VERSION 5.8 ;
BUSBITCHARS "[]" ;
DIVIDERCHAR "/" ;
UNITS
    DATABASE MICRONS 1000 ;
END UNITS

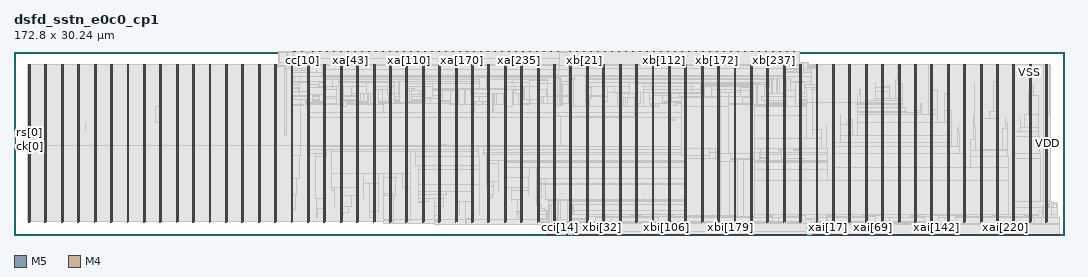
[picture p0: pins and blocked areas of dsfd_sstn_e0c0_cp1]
MACRO dsfd_sstn_e0c0_cp1
  FOREIGN dsfd_sstn_e0c0_cp1 0 0 ;
  CLASS BLOCK ;
  SIZE 172.8 BY 30.24 ;
  PIN c0[0]
    DIRECTION INPUT ;
    USE SIGNAL ;
    PORT
      LAYER M5 ;
        RECT  44.832 30.156 44.856 30.24 ;
    END
  END c0[0]
  PIN c0[1]
    DIRECTION INPUT ;
    USE SIGNAL ;
    PORT
      LAYER M5 ;
        RECT  44.976 30.156 45 30.24 ;
    END
  END c0[1]
  PIN cc[0]
    DIRECTION OUTPUT ;
    USE SIGNAL ;
    PORT
      LAYER M5 ;
        RECT  46.08 30.156 46.104 30.24 ;
    END
  END cc[0]
  PIN cc[10]
    DIRECTION OUTPUT ;
    USE SIGNAL ;
    PORT
      LAYER M5 ;
        RECT  47.52 30.156 47.544 30.24 ;
    END
  END cc[10]
  PIN cc[11]
    DIRECTION OUTPUT ;
    USE SIGNAL ;
    PORT
      LAYER M5 ;
        RECT  47.664 30.156 47.688 30.24 ;
    END
  END cc[11]
  PIN cc[12]
    DIRECTION OUTPUT ;
    USE SIGNAL ;
    PORT
      LAYER M5 ;
        RECT  47.808 30.156 47.832 30.24 ;
    END
  END cc[12]
  PIN cc[13]
    DIRECTION OUTPUT ;
    USE SIGNAL ;
    PORT
      LAYER M5 ;
        RECT  47.952 30.156 47.976 30.24 ;
    END
  END cc[13]
  PIN cc[14]
    DIRECTION OUTPUT ;
    USE SIGNAL ;
    PORT
      LAYER M5 ;
        RECT  48.096 30.156 48.12 30.24 ;
    END
  END cc[14]
  PIN cc[1]
    DIRECTION OUTPUT ;
    USE SIGNAL ;
    PORT
      LAYER M5 ;
        RECT  46.224 30.156 46.248 30.24 ;
    END
  END cc[1]
  PIN cc[2]
    DIRECTION OUTPUT ;
    USE SIGNAL ;
    PORT
      LAYER M5 ;
        RECT  46.368 30.156 46.392 30.24 ;
    END
  END cc[2]
  PIN cc[3]
    DIRECTION OUTPUT ;
    USE SIGNAL ;
    PORT
      LAYER M5 ;
        RECT  46.512 30.156 46.536 30.24 ;
    END
  END cc[3]
  PIN cc[4]
    DIRECTION OUTPUT ;
    USE SIGNAL ;
    PORT
      LAYER M5 ;
        RECT  46.656 30.156 46.68 30.24 ;
    END
  END cc[4]
  PIN cc[5]
    DIRECTION OUTPUT ;
    USE SIGNAL ;
    PORT
      LAYER M5 ;
        RECT  46.8 30.156 46.824 30.24 ;
    END
  END cc[5]
  PIN cc[6]
    DIRECTION OUTPUT ;
    USE SIGNAL ;
    PORT
      LAYER M5 ;
        RECT  46.944 30.156 46.968 30.24 ;
    END
  END cc[6]
  PIN cc[7]
    DIRECTION OUTPUT ;
    USE SIGNAL ;
    PORT
      LAYER M5 ;
        RECT  47.088 30.156 47.112 30.24 ;
    END
  END cc[7]
  PIN cc[8]
    DIRECTION OUTPUT ;
    USE SIGNAL ;
    PORT
      LAYER M5 ;
        RECT  47.232 30.156 47.256 30.24 ;
    END
  END cc[8]
  PIN cc[9]
    DIRECTION OUTPUT ;
    USE SIGNAL ;
    PORT
      LAYER M5 ;
        RECT  47.376 30.156 47.4 30.24 ;
    END
  END cc[9]
  PIN cci[0]
    DIRECTION INPUT ;
    USE SIGNAL ;
    PORT
      LAYER M5 ;
        RECT  87.792 0 87.816 0.084 ;
    END
  END cci[0]
  PIN cci[10]
    DIRECTION INPUT ;
    USE SIGNAL ;
    PORT
      LAYER M5 ;
        RECT  89.232 0 89.256 0.084 ;
    END
  END cci[10]
  PIN cci[11]
    DIRECTION INPUT ;
    USE SIGNAL ;
    PORT
      LAYER M5 ;
        RECT  89.376 0 89.4 0.084 ;
    END
  END cci[11]
  PIN cci[12]
    DIRECTION INPUT ;
    USE SIGNAL ;
    PORT
      LAYER M5 ;
        RECT  89.52 0 89.544 0.084 ;
    END
  END cci[12]
  PIN cci[13]
    DIRECTION INPUT ;
    USE SIGNAL ;
    PORT
      LAYER M5 ;
        RECT  89.664 0 89.688 0.084 ;
    END
  END cci[13]
  PIN cci[14]
    DIRECTION INPUT ;
    USE SIGNAL ;
    PORT
      LAYER M5 ;
        RECT  89.808 0 89.832 0.084 ;
    END
  END cci[14]
  PIN cci[1]
    DIRECTION INPUT ;
    USE SIGNAL ;
    PORT
      LAYER M5 ;
        RECT  87.936 0 87.96 0.084 ;
    END
  END cci[1]
  PIN cci[2]
    DIRECTION INPUT ;
    USE SIGNAL ;
    PORT
      LAYER M5 ;
        RECT  88.08 0 88.104 0.084 ;
    END
  END cci[2]
  PIN cci[3]
    DIRECTION INPUT ;
    USE SIGNAL ;
    PORT
      LAYER M5 ;
        RECT  88.224 0 88.248 0.084 ;
    END
  END cci[3]
  PIN cci[4]
    DIRECTION INPUT ;
    USE SIGNAL ;
    PORT
      LAYER M5 ;
        RECT  88.368 0 88.392 0.084 ;
    END
  END cci[4]
  PIN cci[5]
    DIRECTION INPUT ;
    USE SIGNAL ;
    PORT
      LAYER M5 ;
        RECT  88.512 0 88.536 0.084 ;
    END
  END cci[5]
  PIN cci[6]
    DIRECTION INPUT ;
    USE SIGNAL ;
    PORT
      LAYER M5 ;
        RECT  88.656 0 88.68 0.084 ;
    END
  END cci[6]
  PIN cci[7]
    DIRECTION INPUT ;
    USE SIGNAL ;
    PORT
      LAYER M5 ;
        RECT  88.8 0 88.824 0.084 ;
    END
  END cci[7]
  PIN cci[8]
    DIRECTION INPUT ;
    USE SIGNAL ;
    PORT
      LAYER M5 ;
        RECT  88.944 0 88.968 0.084 ;
    END
  END cci[8]
  PIN cci[9]
    DIRECTION INPUT ;
    USE SIGNAL ;
    PORT
      LAYER M5 ;
        RECT  89.088 0 89.112 0.084 ;
    END
  END cci[9]
  PIN ck[0]
    DIRECTION INPUT ;
    USE SIGNAL ;
    PORT
      LAYER M4 ;
        RECT  0 14.592 0.084 14.616 ;
    END
    PORT
      LAYER M4 ;
        RECT  0.06 14.592 0.097 14.616 ;
    END
  END ck[0]
  PIN e0[0]
    DIRECTION INPUT ;
    USE SIGNAL ;
    PORT
      LAYER M5 ;
        RECT  43.584 30.156 43.608 30.24 ;
    END
  END e0[0]
  PIN e0[1]
    DIRECTION INPUT ;
    USE SIGNAL ;
    PORT
      LAYER M5 ;
        RECT  43.728 30.156 43.752 30.24 ;
    END
  END e0[1]
  PIN rs[0]
    DIRECTION INPUT ;
    USE SIGNAL ;
    PORT
      LAYER M4 ;
        RECT  0 15.6 0.084 15.624 ;
    END
    PORT
      LAYER M4 ;
        RECT  0.06 15.6 0.097 15.624 ;
    END
  END rs[0]
  PIN so[0]
    DIRECTION OUTPUT ;
    USE SIGNAL ;
    PORT
      LAYER M5 ;
        RECT  90.912 0 90.936 0.084 ;
    END
  END so[0]
  PIN so[1]
    DIRECTION OUTPUT ;
    USE SIGNAL ;
    PORT
      LAYER M5 ;
        RECT  91.056 0 91.08 0.084 ;
    END
  END so[1]
  PIN xa[0]
    DIRECTION OUTPUT ;
    USE SIGNAL ;
    PORT
      LAYER M5 ;
        RECT  49.2 30.156 49.224 30.24 ;
    END
  END xa[0]
  PIN xa[100]
    DIRECTION OUTPUT ;
    USE SIGNAL ;
    PORT
      LAYER M5 ;
        RECT  63.6 30.156 63.624 30.24 ;
    END
  END xa[100]
  PIN xa[101]
    DIRECTION OUTPUT ;
    USE SIGNAL ;
    PORT
      LAYER M5 ;
        RECT  63.744 30.156 63.768 30.24 ;
    END
  END xa[101]
  PIN xa[102]
    DIRECTION OUTPUT ;
    USE SIGNAL ;
    PORT
      LAYER M5 ;
        RECT  63.888 30.156 63.912 30.24 ;
    END
  END xa[102]
  PIN xa[103]
    DIRECTION OUTPUT ;
    USE SIGNAL ;
    PORT
      LAYER M5 ;
        RECT  64.032 30.156 64.056 30.24 ;
    END
  END xa[103]
  PIN xa[104]
    DIRECTION OUTPUT ;
    USE SIGNAL ;
    PORT
      LAYER M5 ;
        RECT  64.176 30.156 64.2 30.24 ;
    END
  END xa[104]
  PIN xa[105]
    DIRECTION OUTPUT ;
    USE SIGNAL ;
    PORT
      LAYER M5 ;
        RECT  64.32 30.156 64.344 30.24 ;
    END
  END xa[105]
  PIN xa[106]
    DIRECTION OUTPUT ;
    USE SIGNAL ;
    PORT
      LAYER M5 ;
        RECT  64.464 30.156 64.488 30.24 ;
    END
  END xa[106]
  PIN xa[107]
    DIRECTION OUTPUT ;
    USE SIGNAL ;
    PORT
      LAYER M5 ;
        RECT  64.608 30.156 64.632 30.24 ;
    END
  END xa[107]
  PIN xa[108]
    DIRECTION OUTPUT ;
    USE SIGNAL ;
    PORT
      LAYER M5 ;
        RECT  64.752 30.156 64.776 30.24 ;
    END
  END xa[108]
  PIN xa[109]
    DIRECTION OUTPUT ;
    USE SIGNAL ;
    PORT
      LAYER M5 ;
        RECT  64.896 30.156 64.92 30.24 ;
    END
  END xa[109]
  PIN xa[10]
    DIRECTION OUTPUT ;
    USE SIGNAL ;
    PORT
      LAYER M5 ;
        RECT  50.64 30.156 50.664 30.24 ;
    END
  END xa[10]
  PIN xa[110]
    DIRECTION OUTPUT ;
    USE SIGNAL ;
    PORT
      LAYER M5 ;
        RECT  65.04 30.156 65.064 30.24 ;
    END
  END xa[110]
  PIN xa[111]
    DIRECTION OUTPUT ;
    USE SIGNAL ;
    PORT
      LAYER M5 ;
        RECT  65.184 30.156 65.208 30.24 ;
    END
  END xa[111]
  PIN xa[112]
    DIRECTION OUTPUT ;
    USE SIGNAL ;
    PORT
      LAYER M5 ;
        RECT  65.328 30.156 65.352 30.24 ;
    END
  END xa[112]
  PIN xa[113]
    DIRECTION OUTPUT ;
    USE SIGNAL ;
    PORT
      LAYER M5 ;
        RECT  65.472 30.156 65.496 30.24 ;
    END
  END xa[113]
  PIN xa[114]
    DIRECTION OUTPUT ;
    USE SIGNAL ;
    PORT
      LAYER M5 ;
        RECT  65.616 30.156 65.64 30.24 ;
    END
  END xa[114]
  PIN xa[115]
    DIRECTION OUTPUT ;
    USE SIGNAL ;
    PORT
      LAYER M5 ;
        RECT  65.76 30.156 65.784 30.24 ;
    END
  END xa[115]
  PIN xa[116]
    DIRECTION OUTPUT ;
    USE SIGNAL ;
    PORT
      LAYER M5 ;
        RECT  65.904 30.156 65.928 30.24 ;
    END
  END xa[116]
  PIN xa[117]
    DIRECTION OUTPUT ;
    USE SIGNAL ;
    PORT
      LAYER M5 ;
        RECT  66.048 30.156 66.072 30.24 ;
    END
  END xa[117]
  PIN xa[118]
    DIRECTION OUTPUT ;
    USE SIGNAL ;
    PORT
      LAYER M5 ;
        RECT  66.192 30.156 66.216 30.24 ;
    END
  END xa[118]
  PIN xa[119]
    DIRECTION OUTPUT ;
    USE SIGNAL ;
    PORT
      LAYER M5 ;
        RECT  66.336 30.156 66.36 30.24 ;
    END
  END xa[119]
  PIN xa[11]
    DIRECTION OUTPUT ;
    USE SIGNAL ;
    PORT
      LAYER M5 ;
        RECT  50.784 30.156 50.808 30.24 ;
    END
  END xa[11]
  PIN xa[120]
    DIRECTION OUTPUT ;
    USE SIGNAL ;
    PORT
      LAYER M5 ;
        RECT  66.48 30.156 66.504 30.24 ;
    END
  END xa[120]
  PIN xa[121]
    DIRECTION OUTPUT ;
    USE SIGNAL ;
    PORT
      LAYER M5 ;
        RECT  66.624 30.156 66.648 30.24 ;
    END
  END xa[121]
  PIN xa[122]
    DIRECTION OUTPUT ;
    USE SIGNAL ;
    PORT
      LAYER M5 ;
        RECT  66.768 30.156 66.792 30.24 ;
    END
  END xa[122]
  PIN xa[123]
    DIRECTION OUTPUT ;
    USE SIGNAL ;
    PORT
      LAYER M5 ;
        RECT  66.912 30.156 66.936 30.24 ;
    END
  END xa[123]
  PIN xa[124]
    DIRECTION OUTPUT ;
    USE SIGNAL ;
    PORT
      LAYER M5 ;
        RECT  67.056 30.156 67.08 30.24 ;
    END
  END xa[124]
  PIN xa[125]
    DIRECTION OUTPUT ;
    USE SIGNAL ;
    PORT
      LAYER M5 ;
        RECT  67.2 30.156 67.224 30.24 ;
    END
  END xa[125]
  PIN xa[126]
    DIRECTION OUTPUT ;
    USE SIGNAL ;
    PORT
      LAYER M5 ;
        RECT  67.344 30.156 67.368 30.24 ;
    END
  END xa[126]
  PIN xa[127]
    DIRECTION OUTPUT ;
    USE SIGNAL ;
    PORT
      LAYER M5 ;
        RECT  67.488 30.156 67.512 30.24 ;
    END
  END xa[127]
  PIN xa[128]
    DIRECTION OUTPUT ;
    USE SIGNAL ;
    PORT
      LAYER M5 ;
        RECT  67.632 30.156 67.656 30.24 ;
    END
  END xa[128]
  PIN xa[129]
    DIRECTION OUTPUT ;
    USE SIGNAL ;
    PORT
      LAYER M5 ;
        RECT  67.776 30.156 67.8 30.24 ;
    END
  END xa[129]
  PIN xa[12]
    DIRECTION OUTPUT ;
    USE SIGNAL ;
    PORT
      LAYER M5 ;
        RECT  50.928 30.156 50.952 30.24 ;
    END
  END xa[12]
  PIN xa[130]
    DIRECTION OUTPUT ;
    USE SIGNAL ;
    PORT
      LAYER M5 ;
        RECT  67.92 30.156 67.944 30.24 ;
    END
  END xa[130]
  PIN xa[131]
    DIRECTION OUTPUT ;
    USE SIGNAL ;
    PORT
      LAYER M5 ;
        RECT  68.064 30.156 68.088 30.24 ;
    END
  END xa[131]
  PIN xa[132]
    DIRECTION OUTPUT ;
    USE SIGNAL ;
    PORT
      LAYER M5 ;
        RECT  68.208 30.156 68.232 30.24 ;
    END
  END xa[132]
  PIN xa[133]
    DIRECTION OUTPUT ;
    USE SIGNAL ;
    PORT
      LAYER M5 ;
        RECT  68.352 30.156 68.376 30.24 ;
    END
  END xa[133]
  PIN xa[134]
    DIRECTION OUTPUT ;
    USE SIGNAL ;
    PORT
      LAYER M5 ;
        RECT  68.496 30.156 68.52 30.24 ;
    END
  END xa[134]
  PIN xa[135]
    DIRECTION OUTPUT ;
    USE SIGNAL ;
    PORT
      LAYER M5 ;
        RECT  68.64 30.156 68.664 30.24 ;
    END
  END xa[135]
  PIN xa[136]
    DIRECTION OUTPUT ;
    USE SIGNAL ;
    PORT
      LAYER M5 ;
        RECT  68.784 30.156 68.808 30.24 ;
    END
  END xa[136]
  PIN xa[137]
    DIRECTION OUTPUT ;
    USE SIGNAL ;
    PORT
      LAYER M5 ;
        RECT  68.928 30.156 68.952 30.24 ;
    END
  END xa[137]
  PIN xa[138]
    DIRECTION OUTPUT ;
    USE SIGNAL ;
    PORT
      LAYER M5 ;
        RECT  69.072 30.156 69.096 30.24 ;
    END
  END xa[138]
  PIN xa[139]
    DIRECTION OUTPUT ;
    USE SIGNAL ;
    PORT
      LAYER M5 ;
        RECT  69.216 30.156 69.24 30.24 ;
    END
  END xa[139]
  PIN xa[13]
    DIRECTION OUTPUT ;
    USE SIGNAL ;
    PORT
      LAYER M5 ;
        RECT  51.072 30.156 51.096 30.24 ;
    END
  END xa[13]
  PIN xa[140]
    DIRECTION OUTPUT ;
    USE SIGNAL ;
    PORT
      LAYER M5 ;
        RECT  69.36 30.156 69.384 30.24 ;
    END
  END xa[140]
  PIN xa[141]
    DIRECTION OUTPUT ;
    USE SIGNAL ;
    PORT
      LAYER M5 ;
        RECT  69.504 30.156 69.528 30.24 ;
    END
  END xa[141]
  PIN xa[142]
    DIRECTION OUTPUT ;
    USE SIGNAL ;
    PORT
      LAYER M5 ;
        RECT  69.648 30.156 69.672 30.24 ;
    END
  END xa[142]
  PIN xa[143]
    DIRECTION OUTPUT ;
    USE SIGNAL ;
    PORT
      LAYER M5 ;
        RECT  69.792 30.156 69.816 30.24 ;
    END
  END xa[143]
  PIN xa[144]
    DIRECTION OUTPUT ;
    USE SIGNAL ;
    PORT
      LAYER M5 ;
        RECT  69.936 30.156 69.96 30.24 ;
    END
  END xa[144]
  PIN xa[145]
    DIRECTION OUTPUT ;
    USE SIGNAL ;
    PORT
      LAYER M5 ;
        RECT  70.08 30.156 70.104 30.24 ;
    END
  END xa[145]
  PIN xa[146]
    DIRECTION OUTPUT ;
    USE SIGNAL ;
    PORT
      LAYER M5 ;
        RECT  70.224 30.156 70.248 30.24 ;
    END
  END xa[146]
  PIN xa[147]
    DIRECTION OUTPUT ;
    USE SIGNAL ;
    PORT
      LAYER M5 ;
        RECT  70.368 30.156 70.392 30.24 ;
    END
  END xa[147]
  PIN xa[148]
    DIRECTION OUTPUT ;
    USE SIGNAL ;
    PORT
      LAYER M5 ;
        RECT  70.512 30.156 70.536 30.24 ;
    END
  END xa[148]
  PIN xa[149]
    DIRECTION OUTPUT ;
    USE SIGNAL ;
    PORT
      LAYER M5 ;
        RECT  70.656 30.156 70.68 30.24 ;
    END
  END xa[149]
  PIN xa[14]
    DIRECTION OUTPUT ;
    USE SIGNAL ;
    PORT
      LAYER M5 ;
        RECT  51.216 30.156 51.24 30.24 ;
    END
  END xa[14]
  PIN xa[150]
    DIRECTION OUTPUT ;
    USE SIGNAL ;
    PORT
      LAYER M5 ;
        RECT  70.8 30.156 70.824 30.24 ;
    END
  END xa[150]
  PIN xa[151]
    DIRECTION OUTPUT ;
    USE SIGNAL ;
    PORT
      LAYER M5 ;
        RECT  70.944 30.156 70.968 30.24 ;
    END
  END xa[151]
  PIN xa[152]
    DIRECTION OUTPUT ;
    USE SIGNAL ;
    PORT
      LAYER M5 ;
        RECT  71.088 30.156 71.112 30.24 ;
    END
  END xa[152]
  PIN xa[153]
    DIRECTION OUTPUT ;
    USE SIGNAL ;
    PORT
      LAYER M5 ;
        RECT  71.232 30.156 71.256 30.24 ;
    END
  END xa[153]
  PIN xa[154]
    DIRECTION OUTPUT ;
    USE SIGNAL ;
    PORT
      LAYER M5 ;
        RECT  71.376 30.156 71.4 30.24 ;
    END
  END xa[154]
  PIN xa[155]
    DIRECTION OUTPUT ;
    USE SIGNAL ;
    PORT
      LAYER M5 ;
        RECT  71.52 30.156 71.544 30.24 ;
    END
  END xa[155]
  PIN xa[156]
    DIRECTION OUTPUT ;
    USE SIGNAL ;
    PORT
      LAYER M5 ;
        RECT  71.664 30.156 71.688 30.24 ;
    END
  END xa[156]
  PIN xa[157]
    DIRECTION OUTPUT ;
    USE SIGNAL ;
    PORT
      LAYER M5 ;
        RECT  71.808 30.156 71.832 30.24 ;
    END
  END xa[157]
  PIN xa[158]
    DIRECTION OUTPUT ;
    USE SIGNAL ;
    PORT
      LAYER M5 ;
        RECT  71.952 30.156 71.976 30.24 ;
    END
  END xa[158]
  PIN xa[159]
    DIRECTION OUTPUT ;
    USE SIGNAL ;
    PORT
      LAYER M5 ;
        RECT  72.096 30.156 72.12 30.24 ;
    END
  END xa[159]
  PIN xa[15]
    DIRECTION OUTPUT ;
    USE SIGNAL ;
    PORT
      LAYER M5 ;
        RECT  51.36 30.156 51.384 30.24 ;
    END
  END xa[15]
  PIN xa[160]
    DIRECTION OUTPUT ;
    USE SIGNAL ;
    PORT
      LAYER M5 ;
        RECT  72.24 30.156 72.264 30.24 ;
    END
  END xa[160]
  PIN xa[161]
    DIRECTION OUTPUT ;
    USE SIGNAL ;
    PORT
      LAYER M5 ;
        RECT  72.384 30.156 72.408 30.24 ;
    END
  END xa[161]
  PIN xa[162]
    DIRECTION OUTPUT ;
    USE SIGNAL ;
    PORT
      LAYER M5 ;
        RECT  72.528 30.156 72.552 30.24 ;
    END
  END xa[162]
  PIN xa[163]
    DIRECTION OUTPUT ;
    USE SIGNAL ;
    PORT
      LAYER M5 ;
        RECT  72.672 30.156 72.696 30.24 ;
    END
  END xa[163]
  PIN xa[164]
    DIRECTION OUTPUT ;
    USE SIGNAL ;
    PORT
      LAYER M5 ;
        RECT  72.816 30.156 72.84 30.24 ;
    END
  END xa[164]
  PIN xa[165]
    DIRECTION OUTPUT ;
    USE SIGNAL ;
    PORT
      LAYER M5 ;
        RECT  72.96 30.156 72.984 30.24 ;
    END
  END xa[165]
  PIN xa[166]
    DIRECTION OUTPUT ;
    USE SIGNAL ;
    PORT
      LAYER M5 ;
        RECT  73.104 30.156 73.128 30.24 ;
    END
  END xa[166]
  PIN xa[167]
    DIRECTION OUTPUT ;
    USE SIGNAL ;
    PORT
      LAYER M5 ;
        RECT  73.248 30.156 73.272 30.24 ;
    END
  END xa[167]
  PIN xa[168]
    DIRECTION OUTPUT ;
    USE SIGNAL ;
    PORT
      LAYER M5 ;
        RECT  73.392 30.156 73.416 30.24 ;
    END
  END xa[168]
  PIN xa[169]
    DIRECTION OUTPUT ;
    USE SIGNAL ;
    PORT
      LAYER M5 ;
        RECT  73.536 30.156 73.56 30.24 ;
    END
  END xa[169]
  PIN xa[16]
    DIRECTION OUTPUT ;
    USE SIGNAL ;
    PORT
      LAYER M5 ;
        RECT  51.504 30.156 51.528 30.24 ;
    END
  END xa[16]
  PIN xa[170]
    DIRECTION OUTPUT ;
    USE SIGNAL ;
    PORT
      LAYER M5 ;
        RECT  73.68 30.156 73.704 30.24 ;
    END
  END xa[170]
  PIN xa[171]
    DIRECTION OUTPUT ;
    USE SIGNAL ;
    PORT
      LAYER M5 ;
        RECT  73.824 30.156 73.848 30.24 ;
    END
  END xa[171]
  PIN xa[172]
    DIRECTION OUTPUT ;
    USE SIGNAL ;
    PORT
      LAYER M5 ;
        RECT  73.968 30.156 73.992 30.24 ;
    END
  END xa[172]
  PIN xa[173]
    DIRECTION OUTPUT ;
    USE SIGNAL ;
    PORT
      LAYER M5 ;
        RECT  74.112 30.156 74.136 30.24 ;
    END
  END xa[173]
  PIN xa[174]
    DIRECTION OUTPUT ;
    USE SIGNAL ;
    PORT
      LAYER M5 ;
        RECT  74.256 30.156 74.28 30.24 ;
    END
  END xa[174]
  PIN xa[175]
    DIRECTION OUTPUT ;
    USE SIGNAL ;
    PORT
      LAYER M5 ;
        RECT  74.4 30.156 74.424 30.24 ;
    END
  END xa[175]
  PIN xa[176]
    DIRECTION OUTPUT ;
    USE SIGNAL ;
    PORT
      LAYER M5 ;
        RECT  74.544 30.156 74.568 30.24 ;
    END
  END xa[176]
  PIN xa[177]
    DIRECTION OUTPUT ;
    USE SIGNAL ;
    PORT
      LAYER M5 ;
        RECT  74.688 30.156 74.712 30.24 ;
    END
  END xa[177]
  PIN xa[178]
    DIRECTION OUTPUT ;
    USE SIGNAL ;
    PORT
      LAYER M5 ;
        RECT  74.832 30.156 74.856 30.24 ;
    END
  END xa[178]
  PIN xa[179]
    DIRECTION OUTPUT ;
    USE SIGNAL ;
    PORT
      LAYER M5 ;
        RECT  74.976 30.156 75 30.24 ;
    END
  END xa[179]
  PIN xa[17]
    DIRECTION OUTPUT ;
    USE SIGNAL ;
    PORT
      LAYER M5 ;
        RECT  51.648 30.156 51.672 30.24 ;
    END
  END xa[17]
  PIN xa[180]
    DIRECTION OUTPUT ;
    USE SIGNAL ;
    PORT
      LAYER M5 ;
        RECT  75.12 30.156 75.144 30.24 ;
    END
  END xa[180]
  PIN xa[181]
    DIRECTION OUTPUT ;
    USE SIGNAL ;
    PORT
      LAYER M5 ;
        RECT  75.264 30.156 75.288 30.24 ;
    END
  END xa[181]
  PIN xa[182]
    DIRECTION OUTPUT ;
    USE SIGNAL ;
    PORT
      LAYER M5 ;
        RECT  75.408 30.156 75.432 30.24 ;
    END
  END xa[182]
  PIN xa[183]
    DIRECTION OUTPUT ;
    USE SIGNAL ;
    PORT
      LAYER M5 ;
        RECT  75.552 30.156 75.576 30.24 ;
    END
  END xa[183]
  PIN xa[184]
    DIRECTION OUTPUT ;
    USE SIGNAL ;
    PORT
      LAYER M5 ;
        RECT  75.696 30.156 75.72 30.24 ;
    END
  END xa[184]
  PIN xa[185]
    DIRECTION OUTPUT ;
    USE SIGNAL ;
    PORT
      LAYER M5 ;
        RECT  75.84 30.156 75.864 30.24 ;
    END
  END xa[185]
  PIN xa[186]
    DIRECTION OUTPUT ;
    USE SIGNAL ;
    PORT
      LAYER M5 ;
        RECT  75.984 30.156 76.008 30.24 ;
    END
  END xa[186]
  PIN xa[187]
    DIRECTION OUTPUT ;
    USE SIGNAL ;
    PORT
      LAYER M5 ;
        RECT  76.128 30.156 76.152 30.24 ;
    END
  END xa[187]
  PIN xa[188]
    DIRECTION OUTPUT ;
    USE SIGNAL ;
    PORT
      LAYER M5 ;
        RECT  76.272 30.156 76.296 30.24 ;
    END
  END xa[188]
  PIN xa[189]
    DIRECTION OUTPUT ;
    USE SIGNAL ;
    PORT
      LAYER M5 ;
        RECT  76.416 30.156 76.44 30.24 ;
    END
  END xa[189]
  PIN xa[18]
    DIRECTION OUTPUT ;
    USE SIGNAL ;
    PORT
      LAYER M5 ;
        RECT  51.792 30.156 51.816 30.24 ;
    END
  END xa[18]
  PIN xa[190]
    DIRECTION OUTPUT ;
    USE SIGNAL ;
    PORT
      LAYER M5 ;
        RECT  76.56 30.156 76.584 30.24 ;
    END
  END xa[190]
  PIN xa[191]
    DIRECTION OUTPUT ;
    USE SIGNAL ;
    PORT
      LAYER M5 ;
        RECT  76.704 30.156 76.728 30.24 ;
    END
  END xa[191]
  PIN xa[192]
    DIRECTION OUTPUT ;
    USE SIGNAL ;
    PORT
      LAYER M5 ;
        RECT  76.848 30.156 76.872 30.24 ;
    END
  END xa[192]
  PIN xa[193]
    DIRECTION OUTPUT ;
    USE SIGNAL ;
    PORT
      LAYER M5 ;
        RECT  76.992 30.156 77.016 30.24 ;
    END
  END xa[193]
  PIN xa[194]
    DIRECTION OUTPUT ;
    USE SIGNAL ;
    PORT
      LAYER M5 ;
        RECT  77.136 30.156 77.16 30.24 ;
    END
  END xa[194]
  PIN xa[195]
    DIRECTION OUTPUT ;
    USE SIGNAL ;
    PORT
      LAYER M5 ;
        RECT  77.28 30.156 77.304 30.24 ;
    END
  END xa[195]
  PIN xa[196]
    DIRECTION OUTPUT ;
    USE SIGNAL ;
    PORT
      LAYER M5 ;
        RECT  77.424 30.156 77.448 30.24 ;
    END
  END xa[196]
  PIN xa[197]
    DIRECTION OUTPUT ;
    USE SIGNAL ;
    PORT
      LAYER M5 ;
        RECT  77.568 30.156 77.592 30.24 ;
    END
  END xa[197]
  PIN xa[198]
    DIRECTION OUTPUT ;
    USE SIGNAL ;
    PORT
      LAYER M5 ;
        RECT  77.712 30.156 77.736 30.24 ;
    END
  END xa[198]
  PIN xa[199]
    DIRECTION OUTPUT ;
    USE SIGNAL ;
    PORT
      LAYER M5 ;
        RECT  77.856 30.156 77.88 30.24 ;
    END
  END xa[199]
  PIN xa[19]
    DIRECTION OUTPUT ;
    USE SIGNAL ;
    PORT
      LAYER M5 ;
        RECT  51.936 30.156 51.96 30.24 ;
    END
  END xa[19]
  PIN xa[1]
    DIRECTION OUTPUT ;
    USE SIGNAL ;
    PORT
      LAYER M5 ;
        RECT  49.344 30.156 49.368 30.24 ;
    END
  END xa[1]
  PIN xa[200]
    DIRECTION OUTPUT ;
    USE SIGNAL ;
    PORT
      LAYER M5 ;
        RECT  78 30.156 78.024 30.24 ;
    END
  END xa[200]
  PIN xa[201]
    DIRECTION OUTPUT ;
    USE SIGNAL ;
    PORT
      LAYER M5 ;
        RECT  78.144 30.156 78.168 30.24 ;
    END
  END xa[201]
  PIN xa[202]
    DIRECTION OUTPUT ;
    USE SIGNAL ;
    PORT
      LAYER M5 ;
        RECT  78.288 30.156 78.312 30.24 ;
    END
  END xa[202]
  PIN xa[203]
    DIRECTION OUTPUT ;
    USE SIGNAL ;
    PORT
      LAYER M5 ;
        RECT  78.432 30.156 78.456 30.24 ;
    END
  END xa[203]
  PIN xa[204]
    DIRECTION OUTPUT ;
    USE SIGNAL ;
    PORT
      LAYER M5 ;
        RECT  78.576 30.156 78.6 30.24 ;
    END
  END xa[204]
  PIN xa[205]
    DIRECTION OUTPUT ;
    USE SIGNAL ;
    PORT
      LAYER M5 ;
        RECT  78.72 30.156 78.744 30.24 ;
    END
  END xa[205]
  PIN xa[206]
    DIRECTION OUTPUT ;
    USE SIGNAL ;
    PORT
      LAYER M5 ;
        RECT  78.864 30.156 78.888 30.24 ;
    END
  END xa[206]
  PIN xa[207]
    DIRECTION OUTPUT ;
    USE SIGNAL ;
    PORT
      LAYER M5 ;
        RECT  79.008 30.156 79.032 30.24 ;
    END
  END xa[207]
  PIN xa[208]
    DIRECTION OUTPUT ;
    USE SIGNAL ;
    PORT
      LAYER M5 ;
        RECT  79.152 30.156 79.176 30.24 ;
    END
  END xa[208]
  PIN xa[209]
    DIRECTION OUTPUT ;
    USE SIGNAL ;
    PORT
      LAYER M5 ;
        RECT  79.296 30.156 79.32 30.24 ;
    END
  END xa[209]
  PIN xa[20]
    DIRECTION OUTPUT ;
    USE SIGNAL ;
    PORT
      LAYER M5 ;
        RECT  52.08 30.156 52.104 30.24 ;
    END
  END xa[20]
  PIN xa[210]
    DIRECTION OUTPUT ;
    USE SIGNAL ;
    PORT
      LAYER M5 ;
        RECT  79.44 30.156 79.464 30.24 ;
    END
  END xa[210]
  PIN xa[211]
    DIRECTION OUTPUT ;
    USE SIGNAL ;
    PORT
      LAYER M5 ;
        RECT  79.584 30.156 79.608 30.24 ;
    END
  END xa[211]
  PIN xa[212]
    DIRECTION OUTPUT ;
    USE SIGNAL ;
    PORT
      LAYER M5 ;
        RECT  79.728 30.156 79.752 30.24 ;
    END
  END xa[212]
  PIN xa[213]
    DIRECTION OUTPUT ;
    USE SIGNAL ;
    PORT
      LAYER M5 ;
        RECT  79.872 30.156 79.896 30.24 ;
    END
  END xa[213]
  PIN xa[214]
    DIRECTION OUTPUT ;
    USE SIGNAL ;
    PORT
      LAYER M5 ;
        RECT  80.016 30.156 80.04 30.24 ;
    END
  END xa[214]
  PIN xa[215]
    DIRECTION OUTPUT ;
    USE SIGNAL ;
    PORT
      LAYER M5 ;
        RECT  80.16 30.156 80.184 30.24 ;
    END
  END xa[215]
  PIN xa[216]
    DIRECTION OUTPUT ;
    USE SIGNAL ;
    PORT
      LAYER M5 ;
        RECT  80.304 30.156 80.328 30.24 ;
    END
  END xa[216]
  PIN xa[217]
    DIRECTION OUTPUT ;
    USE SIGNAL ;
    PORT
      LAYER M5 ;
        RECT  80.448 30.156 80.472 30.24 ;
    END
  END xa[217]
  PIN xa[218]
    DIRECTION OUTPUT ;
    USE SIGNAL ;
    PORT
      LAYER M5 ;
        RECT  80.592 30.156 80.616 30.24 ;
    END
  END xa[218]
  PIN xa[219]
    DIRECTION OUTPUT ;
    USE SIGNAL ;
    PORT
      LAYER M5 ;
        RECT  80.736 30.156 80.76 30.24 ;
    END
  END xa[219]
  PIN xa[21]
    DIRECTION OUTPUT ;
    USE SIGNAL ;
    PORT
      LAYER M5 ;
        RECT  52.224 30.156 52.248 30.24 ;
    END
  END xa[21]
  PIN xa[220]
    DIRECTION OUTPUT ;
    USE SIGNAL ;
    PORT
      LAYER M5 ;
        RECT  80.88 30.156 80.904 30.24 ;
    END
  END xa[220]
  PIN xa[221]
    DIRECTION OUTPUT ;
    USE SIGNAL ;
    PORT
      LAYER M5 ;
        RECT  81.024 30.156 81.048 30.24 ;
    END
  END xa[221]
  PIN xa[222]
    DIRECTION OUTPUT ;
    USE SIGNAL ;
    PORT
      LAYER M5 ;
        RECT  81.168 30.156 81.192 30.24 ;
    END
  END xa[222]
  PIN xa[223]
    DIRECTION OUTPUT ;
    USE SIGNAL ;
    PORT
      LAYER M5 ;
        RECT  81.312 30.156 81.336 30.24 ;
    END
  END xa[223]
  PIN xa[224]
    DIRECTION OUTPUT ;
    USE SIGNAL ;
    PORT
      LAYER M5 ;
        RECT  81.456 30.156 81.48 30.24 ;
    END
  END xa[224]
  PIN xa[225]
    DIRECTION OUTPUT ;
    USE SIGNAL ;
    PORT
      LAYER M5 ;
        RECT  81.6 30.156 81.624 30.24 ;
    END
  END xa[225]
  PIN xa[226]
    DIRECTION OUTPUT ;
    USE SIGNAL ;
    PORT
      LAYER M5 ;
        RECT  81.744 30.156 81.768 30.24 ;
    END
  END xa[226]
  PIN xa[227]
    DIRECTION OUTPUT ;
    USE SIGNAL ;
    PORT
      LAYER M5 ;
        RECT  81.888 30.156 81.912 30.24 ;
    END
  END xa[227]
  PIN xa[228]
    DIRECTION OUTPUT ;
    USE SIGNAL ;
    PORT
      LAYER M5 ;
        RECT  82.032 30.156 82.056 30.24 ;
    END
  END xa[228]
  PIN xa[229]
    DIRECTION OUTPUT ;
    USE SIGNAL ;
    PORT
      LAYER M5 ;
        RECT  82.176 30.156 82.2 30.24 ;
    END
  END xa[229]
  PIN xa[22]
    DIRECTION OUTPUT ;
    USE SIGNAL ;
    PORT
      LAYER M5 ;
        RECT  52.368 30.156 52.392 30.24 ;
    END
  END xa[22]
  PIN xa[230]
    DIRECTION OUTPUT ;
    USE SIGNAL ;
    PORT
      LAYER M5 ;
        RECT  82.32 30.156 82.344 30.24 ;
    END
  END xa[230]
  PIN xa[231]
    DIRECTION OUTPUT ;
    USE SIGNAL ;
    PORT
      LAYER M5 ;
        RECT  82.464 30.156 82.488 30.24 ;
    END
  END xa[231]
  PIN xa[232]
    DIRECTION OUTPUT ;
    USE SIGNAL ;
    PORT
      LAYER M5 ;
        RECT  82.608 30.156 82.632 30.24 ;
    END
  END xa[232]
  PIN xa[233]
    DIRECTION OUTPUT ;
    USE SIGNAL ;
    PORT
      LAYER M5 ;
        RECT  82.752 30.156 82.776 30.24 ;
    END
  END xa[233]
  PIN xa[234]
    DIRECTION OUTPUT ;
    USE SIGNAL ;
    PORT
      LAYER M5 ;
        RECT  82.896 30.156 82.92 30.24 ;
    END
  END xa[234]
  PIN xa[235]
    DIRECTION OUTPUT ;
    USE SIGNAL ;
    PORT
      LAYER M5 ;
        RECT  83.04 30.156 83.064 30.24 ;
    END
  END xa[235]
  PIN xa[236]
    DIRECTION OUTPUT ;
    USE SIGNAL ;
    PORT
      LAYER M5 ;
        RECT  83.184 30.156 83.208 30.24 ;
    END
  END xa[236]
  PIN xa[237]
    DIRECTION OUTPUT ;
    USE SIGNAL ;
    PORT
      LAYER M5 ;
        RECT  83.328 30.156 83.352 30.24 ;
    END
  END xa[237]
  PIN xa[238]
    DIRECTION OUTPUT ;
    USE SIGNAL ;
    PORT
      LAYER M5 ;
        RECT  83.472 30.156 83.496 30.24 ;
    END
  END xa[238]
  PIN xa[239]
    DIRECTION OUTPUT ;
    USE SIGNAL ;
    PORT
      LAYER M5 ;
        RECT  83.616 30.156 83.64 30.24 ;
    END
  END xa[239]
  PIN xa[23]
    DIRECTION OUTPUT ;
    USE SIGNAL ;
    PORT
      LAYER M5 ;
        RECT  52.512 30.156 52.536 30.24 ;
    END
  END xa[23]
  PIN xa[240]
    DIRECTION OUTPUT ;
    USE SIGNAL ;
    PORT
      LAYER M5 ;
        RECT  83.76 30.156 83.784 30.24 ;
    END
  END xa[240]
  PIN xa[241]
    DIRECTION OUTPUT ;
    USE SIGNAL ;
    PORT
      LAYER M5 ;
        RECT  83.904 30.156 83.928 30.24 ;
    END
  END xa[241]
  PIN xa[242]
    DIRECTION OUTPUT ;
    USE SIGNAL ;
    PORT
      LAYER M5 ;
        RECT  84.048 30.156 84.072 30.24 ;
    END
  END xa[242]
  PIN xa[243]
    DIRECTION OUTPUT ;
    USE SIGNAL ;
    PORT
      LAYER M5 ;
        RECT  84.192 30.156 84.216 30.24 ;
    END
  END xa[243]
  PIN xa[244]
    DIRECTION OUTPUT ;
    USE SIGNAL ;
    PORT
      LAYER M5 ;
        RECT  84.336 30.156 84.36 30.24 ;
    END
  END xa[244]
  PIN xa[245]
    DIRECTION OUTPUT ;
    USE SIGNAL ;
    PORT
      LAYER M5 ;
        RECT  84.48 30.156 84.504 30.24 ;
    END
  END xa[245]
  PIN xa[246]
    DIRECTION OUTPUT ;
    USE SIGNAL ;
    PORT
      LAYER M5 ;
        RECT  84.624 30.156 84.648 30.24 ;
    END
  END xa[246]
  PIN xa[247]
    DIRECTION OUTPUT ;
    USE SIGNAL ;
    PORT
      LAYER M5 ;
        RECT  84.768 30.156 84.792 30.24 ;
    END
  END xa[247]
  PIN xa[248]
    DIRECTION OUTPUT ;
    USE SIGNAL ;
    PORT
      LAYER M5 ;
        RECT  84.912 30.156 84.936 30.24 ;
    END
  END xa[248]
  PIN xa[249]
    DIRECTION OUTPUT ;
    USE SIGNAL ;
    PORT
      LAYER M5 ;
        RECT  85.056 30.156 85.08 30.24 ;
    END
  END xa[249]
  PIN xa[24]
    DIRECTION OUTPUT ;
    USE SIGNAL ;
    PORT
      LAYER M5 ;
        RECT  52.656 30.156 52.68 30.24 ;
    END
  END xa[24]
  PIN xa[250]
    DIRECTION OUTPUT ;
    USE SIGNAL ;
    PORT
      LAYER M5 ;
        RECT  85.2 30.156 85.224 30.24 ;
    END
  END xa[250]
  PIN xa[251]
    DIRECTION OUTPUT ;
    USE SIGNAL ;
    PORT
      LAYER M5 ;
        RECT  85.344 30.156 85.368 30.24 ;
    END
  END xa[251]
  PIN xa[252]
    DIRECTION OUTPUT ;
    USE SIGNAL ;
    PORT
      LAYER M5 ;
        RECT  85.488 30.156 85.512 30.24 ;
    END
  END xa[252]
  PIN xa[253]
    DIRECTION OUTPUT ;
    USE SIGNAL ;
    PORT
      LAYER M5 ;
        RECT  85.632 30.156 85.656 30.24 ;
    END
  END xa[253]
  PIN xa[254]
    DIRECTION OUTPUT ;
    USE SIGNAL ;
    PORT
      LAYER M5 ;
        RECT  85.776 30.156 85.8 30.24 ;
    END
  END xa[254]
  PIN xa[255]
    DIRECTION OUTPUT ;
    USE SIGNAL ;
    PORT
      LAYER M5 ;
        RECT  85.92 30.156 85.944 30.24 ;
    END
  END xa[255]
  PIN xa[256]
    DIRECTION OUTPUT ;
    USE SIGNAL ;
    PORT
      LAYER M5 ;
        RECT  86.064 30.156 86.088 30.24 ;
    END
  END xa[256]
  PIN xa[257]
    DIRECTION OUTPUT ;
    USE SIGNAL ;
    PORT
      LAYER M5 ;
        RECT  86.208 30.156 86.232 30.24 ;
    END
  END xa[257]
  PIN xa[258]
    DIRECTION OUTPUT ;
    USE SIGNAL ;
    PORT
      LAYER M5 ;
        RECT  86.352 30.156 86.376 30.24 ;
    END
  END xa[258]
  PIN xa[259]
    DIRECTION OUTPUT ;
    USE SIGNAL ;
    PORT
      LAYER M5 ;
        RECT  86.496 30.156 86.52 30.24 ;
    END
  END xa[259]
  PIN xa[25]
    DIRECTION OUTPUT ;
    USE SIGNAL ;
    PORT
      LAYER M5 ;
        RECT  52.8 30.156 52.824 30.24 ;
    END
  END xa[25]
  PIN xa[260]
    DIRECTION OUTPUT ;
    USE SIGNAL ;
    PORT
      LAYER M5 ;
        RECT  86.64 30.156 86.664 30.24 ;
    END
  END xa[260]
  PIN xa[261]
    DIRECTION OUTPUT ;
    USE SIGNAL ;
    PORT
      LAYER M5 ;
        RECT  86.784 30.156 86.808 30.24 ;
    END
  END xa[261]
  PIN xa[262]
    DIRECTION OUTPUT ;
    USE SIGNAL ;
    PORT
      LAYER M5 ;
        RECT  86.928 30.156 86.952 30.24 ;
    END
  END xa[262]
  PIN xa[263]
    DIRECTION OUTPUT ;
    USE SIGNAL ;
    PORT
      LAYER M5 ;
        RECT  87.072 30.156 87.096 30.24 ;
    END
  END xa[263]
  PIN xa[264]
    DIRECTION OUTPUT ;
    USE SIGNAL ;
    PORT
      LAYER M5 ;
        RECT  87.216 30.156 87.24 30.24 ;
    END
  END xa[264]
  PIN xa[265]
    DIRECTION OUTPUT ;
    USE SIGNAL ;
    PORT
      LAYER M5 ;
        RECT  87.36 30.156 87.384 30.24 ;
    END
  END xa[265]
  PIN xa[266]
    DIRECTION OUTPUT ;
    USE SIGNAL ;
    PORT
      LAYER M5 ;
        RECT  87.504 30.156 87.528 30.24 ;
    END
  END xa[266]
  PIN xa[267]
    DIRECTION OUTPUT ;
    USE SIGNAL ;
    PORT
      LAYER M5 ;
        RECT  87.648 30.156 87.672 30.24 ;
    END
  END xa[267]
  PIN xa[268]
    DIRECTION OUTPUT ;
    USE SIGNAL ;
    PORT
      LAYER M5 ;
        RECT  87.792 30.156 87.816 30.24 ;
    END
  END xa[268]
  PIN xa[269]
    DIRECTION OUTPUT ;
    USE SIGNAL ;
    PORT
      LAYER M5 ;
        RECT  87.936 30.156 87.96 30.24 ;
    END
  END xa[269]
  PIN xa[26]
    DIRECTION OUTPUT ;
    USE SIGNAL ;
    PORT
      LAYER M5 ;
        RECT  52.944 30.156 52.968 30.24 ;
    END
  END xa[26]
  PIN xa[270]
    DIRECTION OUTPUT ;
    USE SIGNAL ;
    PORT
      LAYER M5 ;
        RECT  88.08 30.156 88.104 30.24 ;
    END
  END xa[270]
  PIN xa[271]
    DIRECTION OUTPUT ;
    USE SIGNAL ;
    PORT
      LAYER M5 ;
        RECT  88.224 30.156 88.248 30.24 ;
    END
  END xa[271]
  PIN xa[272]
    DIRECTION OUTPUT ;
    USE SIGNAL ;
    PORT
      LAYER M5 ;
        RECT  88.368 30.156 88.392 30.24 ;
    END
  END xa[272]
  PIN xa[273]
    DIRECTION OUTPUT ;
    USE SIGNAL ;
    PORT
      LAYER M5 ;
        RECT  88.512 30.156 88.536 30.24 ;
    END
  END xa[273]
  PIN xa[274]
    DIRECTION OUTPUT ;
    USE SIGNAL ;
    PORT
      LAYER M5 ;
        RECT  88.656 30.156 88.68 30.24 ;
    END
  END xa[274]
  PIN xa[275]
    DIRECTION OUTPUT ;
    USE SIGNAL ;
    PORT
      LAYER M5 ;
        RECT  88.8 30.156 88.824 30.24 ;
    END
  END xa[275]
  PIN xa[276]
    DIRECTION OUTPUT ;
    USE SIGNAL ;
    PORT
      LAYER M5 ;
        RECT  88.944 30.156 88.968 30.24 ;
    END
  END xa[276]
  PIN xa[277]
    DIRECTION OUTPUT ;
    USE SIGNAL ;
    PORT
      LAYER M5 ;
        RECT  89.088 30.156 89.112 30.24 ;
    END
  END xa[277]
  PIN xa[278]
    DIRECTION OUTPUT ;
    USE SIGNAL ;
    PORT
      LAYER M5 ;
        RECT  89.232 30.156 89.256 30.24 ;
    END
  END xa[278]
  PIN xa[279]
    DIRECTION OUTPUT ;
    USE SIGNAL ;
    PORT
      LAYER M5 ;
        RECT  89.376 30.156 89.4 30.24 ;
    END
  END xa[279]
  PIN xa[27]
    DIRECTION OUTPUT ;
    USE SIGNAL ;
    PORT
      LAYER M5 ;
        RECT  53.088 30.156 53.112 30.24 ;
    END
  END xa[27]
  PIN xa[280]
    DIRECTION OUTPUT ;
    USE SIGNAL ;
    PORT
      LAYER M5 ;
        RECT  89.52 30.156 89.544 30.24 ;
    END
  END xa[280]
  PIN xa[281]
    DIRECTION OUTPUT ;
    USE SIGNAL ;
    PORT
      LAYER M5 ;
        RECT  89.664 30.156 89.688 30.24 ;
    END
  END xa[281]
  PIN xa[282]
    DIRECTION OUTPUT ;
    USE SIGNAL ;
    PORT
      LAYER M5 ;
        RECT  89.808 30.156 89.832 30.24 ;
    END
  END xa[282]
  PIN xa[28]
    DIRECTION OUTPUT ;
    USE SIGNAL ;
    PORT
      LAYER M5 ;
        RECT  53.232 30.156 53.256 30.24 ;
    END
  END xa[28]
  PIN xa[29]
    DIRECTION OUTPUT ;
    USE SIGNAL ;
    PORT
      LAYER M5 ;
        RECT  53.376 30.156 53.4 30.24 ;
    END
  END xa[29]
  PIN xa[2]
    DIRECTION OUTPUT ;
    USE SIGNAL ;
    PORT
      LAYER M5 ;
        RECT  49.488 30.156 49.512 30.24 ;
    END
  END xa[2]
  PIN xa[30]
    DIRECTION OUTPUT ;
    USE SIGNAL ;
    PORT
      LAYER M5 ;
        RECT  53.52 30.156 53.544 30.24 ;
    END
  END xa[30]
  PIN xa[31]
    DIRECTION OUTPUT ;
    USE SIGNAL ;
    PORT
      LAYER M5 ;
        RECT  53.664 30.156 53.688 30.24 ;
    END
  END xa[31]
  PIN xa[32]
    DIRECTION OUTPUT ;
    USE SIGNAL ;
    PORT
      LAYER M5 ;
        RECT  53.808 30.156 53.832 30.24 ;
    END
  END xa[32]
  PIN xa[33]
    DIRECTION OUTPUT ;
    USE SIGNAL ;
    PORT
      LAYER M5 ;
        RECT  53.952 30.156 53.976 30.24 ;
    END
  END xa[33]
  PIN xa[34]
    DIRECTION OUTPUT ;
    USE SIGNAL ;
    PORT
      LAYER M5 ;
        RECT  54.096 30.156 54.12 30.24 ;
    END
  END xa[34]
  PIN xa[35]
    DIRECTION OUTPUT ;
    USE SIGNAL ;
    PORT
      LAYER M5 ;
        RECT  54.24 30.156 54.264 30.24 ;
    END
  END xa[35]
  PIN xa[36]
    DIRECTION OUTPUT ;
    USE SIGNAL ;
    PORT
      LAYER M5 ;
        RECT  54.384 30.156 54.408 30.24 ;
    END
  END xa[36]
  PIN xa[37]
    DIRECTION OUTPUT ;
    USE SIGNAL ;
    PORT
      LAYER M5 ;
        RECT  54.528 30.156 54.552 30.24 ;
    END
  END xa[37]
  PIN xa[38]
    DIRECTION OUTPUT ;
    USE SIGNAL ;
    PORT
      LAYER M5 ;
        RECT  54.672 30.156 54.696 30.24 ;
    END
  END xa[38]
  PIN xa[39]
    DIRECTION OUTPUT ;
    USE SIGNAL ;
    PORT
      LAYER M5 ;
        RECT  54.816 30.156 54.84 30.24 ;
    END
  END xa[39]
  PIN xa[3]
    DIRECTION OUTPUT ;
    USE SIGNAL ;
    PORT
      LAYER M5 ;
        RECT  49.632 30.156 49.656 30.24 ;
    END
  END xa[3]
  PIN xa[40]
    DIRECTION OUTPUT ;
    USE SIGNAL ;
    PORT
      LAYER M5 ;
        RECT  54.96 30.156 54.984 30.24 ;
    END
  END xa[40]
  PIN xa[41]
    DIRECTION OUTPUT ;
    USE SIGNAL ;
    PORT
      LAYER M5 ;
        RECT  55.104 30.156 55.128 30.24 ;
    END
  END xa[41]
  PIN xa[42]
    DIRECTION OUTPUT ;
    USE SIGNAL ;
    PORT
      LAYER M5 ;
        RECT  55.248 30.156 55.272 30.24 ;
    END
  END xa[42]
  PIN xa[43]
    DIRECTION OUTPUT ;
    USE SIGNAL ;
    PORT
      LAYER M5 ;
        RECT  55.392 30.156 55.416 30.24 ;
    END
  END xa[43]
  PIN xa[44]
    DIRECTION OUTPUT ;
    USE SIGNAL ;
    PORT
      LAYER M5 ;
        RECT  55.536 30.156 55.56 30.24 ;
    END
  END xa[44]
  PIN xa[45]
    DIRECTION OUTPUT ;
    USE SIGNAL ;
    PORT
      LAYER M5 ;
        RECT  55.68 30.156 55.704 30.24 ;
    END
  END xa[45]
  PIN xa[46]
    DIRECTION OUTPUT ;
    USE SIGNAL ;
    PORT
      LAYER M5 ;
        RECT  55.824 30.156 55.848 30.24 ;
    END
  END xa[46]
  PIN xa[47]
    DIRECTION OUTPUT ;
    USE SIGNAL ;
    PORT
      LAYER M5 ;
        RECT  55.968 30.156 55.992 30.24 ;
    END
  END xa[47]
  PIN xa[48]
    DIRECTION OUTPUT ;
    USE SIGNAL ;
    PORT
      LAYER M5 ;
        RECT  56.112 30.156 56.136 30.24 ;
    END
  END xa[48]
  PIN xa[49]
    DIRECTION OUTPUT ;
    USE SIGNAL ;
    PORT
      LAYER M5 ;
        RECT  56.256 30.156 56.28 30.24 ;
    END
  END xa[49]
  PIN xa[4]
    DIRECTION OUTPUT ;
    USE SIGNAL ;
    PORT
      LAYER M5 ;
        RECT  49.776 30.156 49.8 30.24 ;
    END
  END xa[4]
  PIN xa[50]
    DIRECTION OUTPUT ;
    USE SIGNAL ;
    PORT
      LAYER M5 ;
        RECT  56.4 30.156 56.424 30.24 ;
    END
  END xa[50]
  PIN xa[51]
    DIRECTION OUTPUT ;
    USE SIGNAL ;
    PORT
      LAYER M5 ;
        RECT  56.544 30.156 56.568 30.24 ;
    END
  END xa[51]
  PIN xa[52]
    DIRECTION OUTPUT ;
    USE SIGNAL ;
    PORT
      LAYER M5 ;
        RECT  56.688 30.156 56.712 30.24 ;
    END
  END xa[52]
  PIN xa[53]
    DIRECTION OUTPUT ;
    USE SIGNAL ;
    PORT
      LAYER M5 ;
        RECT  56.832 30.156 56.856 30.24 ;
    END
  END xa[53]
  PIN xa[54]
    DIRECTION OUTPUT ;
    USE SIGNAL ;
    PORT
      LAYER M5 ;
        RECT  56.976 30.156 57 30.24 ;
    END
  END xa[54]
  PIN xa[55]
    DIRECTION OUTPUT ;
    USE SIGNAL ;
    PORT
      LAYER M5 ;
        RECT  57.12 30.156 57.144 30.24 ;
    END
  END xa[55]
  PIN xa[56]
    DIRECTION OUTPUT ;
    USE SIGNAL ;
    PORT
      LAYER M5 ;
        RECT  57.264 30.156 57.288 30.24 ;
    END
  END xa[56]
  PIN xa[57]
    DIRECTION OUTPUT ;
    USE SIGNAL ;
    PORT
      LAYER M5 ;
        RECT  57.408 30.156 57.432 30.24 ;
    END
  END xa[57]
  PIN xa[58]
    DIRECTION OUTPUT ;
    USE SIGNAL ;
    PORT
      LAYER M5 ;
        RECT  57.552 30.156 57.576 30.24 ;
    END
  END xa[58]
  PIN xa[59]
    DIRECTION OUTPUT ;
    USE SIGNAL ;
    PORT
      LAYER M5 ;
        RECT  57.696 30.156 57.72 30.24 ;
    END
  END xa[59]
  PIN xa[5]
    DIRECTION OUTPUT ;
    USE SIGNAL ;
    PORT
      LAYER M5 ;
        RECT  49.92 30.156 49.944 30.24 ;
    END
  END xa[5]
  PIN xa[60]
    DIRECTION OUTPUT ;
    USE SIGNAL ;
    PORT
      LAYER M5 ;
        RECT  57.84 30.156 57.864 30.24 ;
    END
  END xa[60]
  PIN xa[61]
    DIRECTION OUTPUT ;
    USE SIGNAL ;
    PORT
      LAYER M5 ;
        RECT  57.984 30.156 58.008 30.24 ;
    END
  END xa[61]
  PIN xa[62]
    DIRECTION OUTPUT ;
    USE SIGNAL ;
    PORT
      LAYER M5 ;
        RECT  58.128 30.156 58.152 30.24 ;
    END
  END xa[62]
  PIN xa[63]
    DIRECTION OUTPUT ;
    USE SIGNAL ;
    PORT
      LAYER M5 ;
        RECT  58.272 30.156 58.296 30.24 ;
    END
  END xa[63]
  PIN xa[64]
    DIRECTION OUTPUT ;
    USE SIGNAL ;
    PORT
      LAYER M5 ;
        RECT  58.416 30.156 58.44 30.24 ;
    END
  END xa[64]
  PIN xa[65]
    DIRECTION OUTPUT ;
    USE SIGNAL ;
    PORT
      LAYER M5 ;
        RECT  58.56 30.156 58.584 30.24 ;
    END
  END xa[65]
  PIN xa[66]
    DIRECTION OUTPUT ;
    USE SIGNAL ;
    PORT
      LAYER M5 ;
        RECT  58.704 30.156 58.728 30.24 ;
    END
  END xa[66]
  PIN xa[67]
    DIRECTION OUTPUT ;
    USE SIGNAL ;
    PORT
      LAYER M5 ;
        RECT  58.848 30.156 58.872 30.24 ;
    END
  END xa[67]
  PIN xa[68]
    DIRECTION OUTPUT ;
    USE SIGNAL ;
    PORT
      LAYER M5 ;
        RECT  58.992 30.156 59.016 30.24 ;
    END
  END xa[68]
  PIN xa[69]
    DIRECTION OUTPUT ;
    USE SIGNAL ;
    PORT
      LAYER M5 ;
        RECT  59.136 30.156 59.16 30.24 ;
    END
  END xa[69]
  PIN xa[6]
    DIRECTION OUTPUT ;
    USE SIGNAL ;
    PORT
      LAYER M5 ;
        RECT  50.064 30.156 50.088 30.24 ;
    END
  END xa[6]
  PIN xa[70]
    DIRECTION OUTPUT ;
    USE SIGNAL ;
    PORT
      LAYER M5 ;
        RECT  59.28 30.156 59.304 30.24 ;
    END
  END xa[70]
  PIN xa[71]
    DIRECTION OUTPUT ;
    USE SIGNAL ;
    PORT
      LAYER M5 ;
        RECT  59.424 30.156 59.448 30.24 ;
    END
  END xa[71]
  PIN xa[72]
    DIRECTION OUTPUT ;
    USE SIGNAL ;
    PORT
      LAYER M5 ;
        RECT  59.568 30.156 59.592 30.24 ;
    END
  END xa[72]
  PIN xa[73]
    DIRECTION OUTPUT ;
    USE SIGNAL ;
    PORT
      LAYER M5 ;
        RECT  59.712 30.156 59.736 30.24 ;
    END
  END xa[73]
  PIN xa[74]
    DIRECTION OUTPUT ;
    USE SIGNAL ;
    PORT
      LAYER M5 ;
        RECT  59.856 30.156 59.88 30.24 ;
    END
  END xa[74]
  PIN xa[75]
    DIRECTION OUTPUT ;
    USE SIGNAL ;
    PORT
      LAYER M5 ;
        RECT  60 30.156 60.024 30.24 ;
    END
  END xa[75]
  PIN xa[76]
    DIRECTION OUTPUT ;
    USE SIGNAL ;
    PORT
      LAYER M5 ;
        RECT  60.144 30.156 60.168 30.24 ;
    END
  END xa[76]
  PIN xa[77]
    DIRECTION OUTPUT ;
    USE SIGNAL ;
    PORT
      LAYER M5 ;
        RECT  60.288 30.156 60.312 30.24 ;
    END
  END xa[77]
  PIN xa[78]
    DIRECTION OUTPUT ;
    USE SIGNAL ;
    PORT
      LAYER M5 ;
        RECT  60.432 30.156 60.456 30.24 ;
    END
  END xa[78]
  PIN xa[79]
    DIRECTION OUTPUT ;
    USE SIGNAL ;
    PORT
      LAYER M5 ;
        RECT  60.576 30.156 60.6 30.24 ;
    END
  END xa[79]
  PIN xa[7]
    DIRECTION OUTPUT ;
    USE SIGNAL ;
    PORT
      LAYER M5 ;
        RECT  50.208 30.156 50.232 30.24 ;
    END
  END xa[7]
  PIN xa[80]
    DIRECTION OUTPUT ;
    USE SIGNAL ;
    PORT
      LAYER M5 ;
        RECT  60.72 30.156 60.744 30.24 ;
    END
  END xa[80]
  PIN xa[81]
    DIRECTION OUTPUT ;
    USE SIGNAL ;
    PORT
      LAYER M5 ;
        RECT  60.864 30.156 60.888 30.24 ;
    END
  END xa[81]
  PIN xa[82]
    DIRECTION OUTPUT ;
    USE SIGNAL ;
    PORT
      LAYER M5 ;
        RECT  61.008 30.156 61.032 30.24 ;
    END
  END xa[82]
  PIN xa[83]
    DIRECTION OUTPUT ;
    USE SIGNAL ;
    PORT
      LAYER M5 ;
        RECT  61.152 30.156 61.176 30.24 ;
    END
  END xa[83]
  PIN xa[84]
    DIRECTION OUTPUT ;
    USE SIGNAL ;
    PORT
      LAYER M5 ;
        RECT  61.296 30.156 61.32 30.24 ;
    END
  END xa[84]
  PIN xa[85]
    DIRECTION OUTPUT ;
    USE SIGNAL ;
    PORT
      LAYER M5 ;
        RECT  61.44 30.156 61.464 30.24 ;
    END
  END xa[85]
  PIN xa[86]
    DIRECTION OUTPUT ;
    USE SIGNAL ;
    PORT
      LAYER M5 ;
        RECT  61.584 30.156 61.608 30.24 ;
    END
  END xa[86]
  PIN xa[87]
    DIRECTION OUTPUT ;
    USE SIGNAL ;
    PORT
      LAYER M5 ;
        RECT  61.728 30.156 61.752 30.24 ;
    END
  END xa[87]
  PIN xa[88]
    DIRECTION OUTPUT ;
    USE SIGNAL ;
    PORT
      LAYER M5 ;
        RECT  61.872 30.156 61.896 30.24 ;
    END
  END xa[88]
  PIN xa[89]
    DIRECTION OUTPUT ;
    USE SIGNAL ;
    PORT
      LAYER M5 ;
        RECT  62.016 30.156 62.04 30.24 ;
    END
  END xa[89]
  PIN xa[8]
    DIRECTION OUTPUT ;
    USE SIGNAL ;
    PORT
      LAYER M5 ;
        RECT  50.352 30.156 50.376 30.24 ;
    END
  END xa[8]
  PIN xa[90]
    DIRECTION OUTPUT ;
    USE SIGNAL ;
    PORT
      LAYER M5 ;
        RECT  62.16 30.156 62.184 30.24 ;
    END
  END xa[90]
  PIN xa[91]
    DIRECTION OUTPUT ;
    USE SIGNAL ;
    PORT
      LAYER M5 ;
        RECT  62.304 30.156 62.328 30.24 ;
    END
  END xa[91]
  PIN xa[92]
    DIRECTION OUTPUT ;
    USE SIGNAL ;
    PORT
      LAYER M5 ;
        RECT  62.448 30.156 62.472 30.24 ;
    END
  END xa[92]
  PIN xa[93]
    DIRECTION OUTPUT ;
    USE SIGNAL ;
    PORT
      LAYER M5 ;
        RECT  62.592 30.156 62.616 30.24 ;
    END
  END xa[93]
  PIN xa[94]
    DIRECTION OUTPUT ;
    USE SIGNAL ;
    PORT
      LAYER M5 ;
        RECT  62.736 30.156 62.76 30.24 ;
    END
  END xa[94]
  PIN xa[95]
    DIRECTION OUTPUT ;
    USE SIGNAL ;
    PORT
      LAYER M5 ;
        RECT  62.88 30.156 62.904 30.24 ;
    END
  END xa[95]
  PIN xa[96]
    DIRECTION OUTPUT ;
    USE SIGNAL ;
    PORT
      LAYER M5 ;
        RECT  63.024 30.156 63.048 30.24 ;
    END
  END xa[96]
  PIN xa[97]
    DIRECTION OUTPUT ;
    USE SIGNAL ;
    PORT
      LAYER M5 ;
        RECT  63.168 30.156 63.192 30.24 ;
    END
  END xa[97]
  PIN xa[98]
    DIRECTION OUTPUT ;
    USE SIGNAL ;
    PORT
      LAYER M5 ;
        RECT  63.312 30.156 63.336 30.24 ;
    END
  END xa[98]
  PIN xa[99]
    DIRECTION OUTPUT ;
    USE SIGNAL ;
    PORT
      LAYER M5 ;
        RECT  63.456 30.156 63.48 30.24 ;
    END
  END xa[99]
  PIN xa[9]
    DIRECTION OUTPUT ;
    USE SIGNAL ;
    PORT
      LAYER M5 ;
        RECT  50.496 30.156 50.52 30.24 ;
    END
  END xa[9]
  PIN xai[0]
    DIRECTION INPUT ;
    USE SIGNAL ;
    PORT
      LAYER M5 ;
        RECT  131.424 0 131.448 0.084 ;
    END
  END xai[0]
  PIN xai[100]
    DIRECTION INPUT ;
    USE SIGNAL ;
    PORT
      LAYER M5 ;
        RECT  145.824 0 145.848 0.084 ;
    END
  END xai[100]
  PIN xai[101]
    DIRECTION INPUT ;
    USE SIGNAL ;
    PORT
      LAYER M5 ;
        RECT  145.968 0 145.992 0.084 ;
    END
  END xai[101]
  PIN xai[102]
    DIRECTION INPUT ;
    USE SIGNAL ;
    PORT
      LAYER M5 ;
        RECT  146.112 0 146.136 0.084 ;
    END
  END xai[102]
  PIN xai[103]
    DIRECTION INPUT ;
    USE SIGNAL ;
    PORT
      LAYER M5 ;
        RECT  146.256 0 146.28 0.084 ;
    END
  END xai[103]
  PIN xai[104]
    DIRECTION INPUT ;
    USE SIGNAL ;
    PORT
      LAYER M5 ;
        RECT  146.4 0 146.424 0.084 ;
    END
  END xai[104]
  PIN xai[105]
    DIRECTION INPUT ;
    USE SIGNAL ;
    PORT
      LAYER M5 ;
        RECT  146.544 0 146.568 0.084 ;
    END
  END xai[105]
  PIN xai[106]
    DIRECTION INPUT ;
    USE SIGNAL ;
    PORT
      LAYER M5 ;
        RECT  146.688 0 146.712 0.084 ;
    END
  END xai[106]
  PIN xai[107]
    DIRECTION INPUT ;
    USE SIGNAL ;
    PORT
      LAYER M5 ;
        RECT  146.832 0 146.856 0.084 ;
    END
  END xai[107]
  PIN xai[108]
    DIRECTION INPUT ;
    USE SIGNAL ;
    PORT
      LAYER M5 ;
        RECT  146.976 0 147 0.084 ;
    END
  END xai[108]
  PIN xai[109]
    DIRECTION INPUT ;
    USE SIGNAL ;
    PORT
      LAYER M5 ;
        RECT  147.12 0 147.144 0.084 ;
    END
  END xai[109]
  PIN xai[10]
    DIRECTION INPUT ;
    USE SIGNAL ;
    PORT
      LAYER M5 ;
        RECT  132.864 0 132.888 0.084 ;
    END
  END xai[10]
  PIN xai[110]
    DIRECTION INPUT ;
    USE SIGNAL ;
    PORT
      LAYER M5 ;
        RECT  147.264 0 147.288 0.084 ;
    END
  END xai[110]
  PIN xai[111]
    DIRECTION INPUT ;
    USE SIGNAL ;
    PORT
      LAYER M5 ;
        RECT  147.408 0 147.432 0.084 ;
    END
  END xai[111]
  PIN xai[112]
    DIRECTION INPUT ;
    USE SIGNAL ;
    PORT
      LAYER M5 ;
        RECT  147.552 0 147.576 0.084 ;
    END
  END xai[112]
  PIN xai[113]
    DIRECTION INPUT ;
    USE SIGNAL ;
    PORT
      LAYER M5 ;
        RECT  147.696 0 147.72 0.084 ;
    END
  END xai[113]
  PIN xai[114]
    DIRECTION INPUT ;
    USE SIGNAL ;
    PORT
      LAYER M5 ;
        RECT  147.84 0 147.864 0.084 ;
    END
  END xai[114]
  PIN xai[115]
    DIRECTION INPUT ;
    USE SIGNAL ;
    PORT
      LAYER M5 ;
        RECT  147.984 0 148.008 0.084 ;
    END
  END xai[115]
  PIN xai[116]
    DIRECTION INPUT ;
    USE SIGNAL ;
    PORT
      LAYER M5 ;
        RECT  148.128 0 148.152 0.084 ;
    END
  END xai[116]
  PIN xai[117]
    DIRECTION INPUT ;
    USE SIGNAL ;
    PORT
      LAYER M5 ;
        RECT  148.272 0 148.296 0.084 ;
    END
  END xai[117]
  PIN xai[118]
    DIRECTION INPUT ;
    USE SIGNAL ;
    PORT
      LAYER M5 ;
        RECT  148.416 0 148.44 0.084 ;
    END
  END xai[118]
  PIN xai[119]
    DIRECTION INPUT ;
    USE SIGNAL ;
    PORT
      LAYER M5 ;
        RECT  148.56 0 148.584 0.084 ;
    END
  END xai[119]
  PIN xai[11]
    DIRECTION INPUT ;
    USE SIGNAL ;
    PORT
      LAYER M5 ;
        RECT  133.008 0 133.032 0.084 ;
    END
  END xai[11]
  PIN xai[120]
    DIRECTION INPUT ;
    USE SIGNAL ;
    PORT
      LAYER M5 ;
        RECT  148.704 0 148.728 0.084 ;
    END
  END xai[120]
  PIN xai[121]
    DIRECTION INPUT ;
    USE SIGNAL ;
    PORT
      LAYER M5 ;
        RECT  148.848 0 148.872 0.084 ;
    END
  END xai[121]
  PIN xai[122]
    DIRECTION INPUT ;
    USE SIGNAL ;
    PORT
      LAYER M5 ;
        RECT  148.992 0 149.016 0.084 ;
    END
  END xai[122]
  PIN xai[123]
    DIRECTION INPUT ;
    USE SIGNAL ;
    PORT
      LAYER M5 ;
        RECT  149.136 0 149.16 0.084 ;
    END
  END xai[123]
  PIN xai[124]
    DIRECTION INPUT ;
    USE SIGNAL ;
    PORT
      LAYER M5 ;
        RECT  149.28 0 149.304 0.084 ;
    END
  END xai[124]
  PIN xai[125]
    DIRECTION INPUT ;
    USE SIGNAL ;
    PORT
      LAYER M5 ;
        RECT  149.424 0 149.448 0.084 ;
    END
  END xai[125]
  PIN xai[126]
    DIRECTION INPUT ;
    USE SIGNAL ;
    PORT
      LAYER M5 ;
        RECT  149.568 0 149.592 0.084 ;
    END
  END xai[126]
  PIN xai[127]
    DIRECTION INPUT ;
    USE SIGNAL ;
    PORT
      LAYER M5 ;
        RECT  149.712 0 149.736 0.084 ;
    END
  END xai[127]
  PIN xai[128]
    DIRECTION INPUT ;
    USE SIGNAL ;
    PORT
      LAYER M5 ;
        RECT  149.856 0 149.88 0.084 ;
    END
  END xai[128]
  PIN xai[129]
    DIRECTION INPUT ;
    USE SIGNAL ;
    PORT
      LAYER M5 ;
        RECT  150 0 150.024 0.084 ;
    END
  END xai[129]
  PIN xai[12]
    DIRECTION INPUT ;
    USE SIGNAL ;
    PORT
      LAYER M5 ;
        RECT  133.152 0 133.176 0.084 ;
    END
  END xai[12]
  PIN xai[130]
    DIRECTION INPUT ;
    USE SIGNAL ;
    PORT
      LAYER M5 ;
        RECT  150.144 0 150.168 0.084 ;
    END
  END xai[130]
  PIN xai[131]
    DIRECTION INPUT ;
    USE SIGNAL ;
    PORT
      LAYER M5 ;
        RECT  150.288 0 150.312 0.084 ;
    END
  END xai[131]
  PIN xai[132]
    DIRECTION INPUT ;
    USE SIGNAL ;
    PORT
      LAYER M5 ;
        RECT  150.432 0 150.456 0.084 ;
    END
  END xai[132]
  PIN xai[133]
    DIRECTION INPUT ;
    USE SIGNAL ;
    PORT
      LAYER M5 ;
        RECT  150.576 0 150.6 0.084 ;
    END
  END xai[133]
  PIN xai[134]
    DIRECTION INPUT ;
    USE SIGNAL ;
    PORT
      LAYER M5 ;
        RECT  150.72 0 150.744 0.084 ;
    END
  END xai[134]
  PIN xai[135]
    DIRECTION INPUT ;
    USE SIGNAL ;
    PORT
      LAYER M5 ;
        RECT  150.864 0 150.888 0.084 ;
    END
  END xai[135]
  PIN xai[136]
    DIRECTION INPUT ;
    USE SIGNAL ;
    PORT
      LAYER M5 ;
        RECT  151.008 0 151.032 0.084 ;
    END
  END xai[136]
  PIN xai[137]
    DIRECTION INPUT ;
    USE SIGNAL ;
    PORT
      LAYER M5 ;
        RECT  151.152 0 151.176 0.084 ;
    END
  END xai[137]
  PIN xai[138]
    DIRECTION INPUT ;
    USE SIGNAL ;
    PORT
      LAYER M5 ;
        RECT  151.296 0 151.32 0.084 ;
    END
  END xai[138]
  PIN xai[139]
    DIRECTION INPUT ;
    USE SIGNAL ;
    PORT
      LAYER M5 ;
        RECT  151.44 0 151.464 0.084 ;
    END
  END xai[139]
  PIN xai[13]
    DIRECTION INPUT ;
    USE SIGNAL ;
    PORT
      LAYER M5 ;
        RECT  133.296 0 133.32 0.084 ;
    END
  END xai[13]
  PIN xai[140]
    DIRECTION INPUT ;
    USE SIGNAL ;
    PORT
      LAYER M5 ;
        RECT  151.584 0 151.608 0.084 ;
    END
  END xai[140]
  PIN xai[141]
    DIRECTION INPUT ;
    USE SIGNAL ;
    PORT
      LAYER M5 ;
        RECT  151.728 0 151.752 0.084 ;
    END
  END xai[141]
  PIN xai[142]
    DIRECTION INPUT ;
    USE SIGNAL ;
    PORT
      LAYER M5 ;
        RECT  151.872 0 151.896 0.084 ;
    END
  END xai[142]
  PIN xai[143]
    DIRECTION INPUT ;
    USE SIGNAL ;
    PORT
      LAYER M5 ;
        RECT  152.016 0 152.04 0.084 ;
    END
  END xai[143]
  PIN xai[144]
    DIRECTION INPUT ;
    USE SIGNAL ;
    PORT
      LAYER M5 ;
        RECT  152.16 0 152.184 0.084 ;
    END
  END xai[144]
  PIN xai[145]
    DIRECTION INPUT ;
    USE SIGNAL ;
    PORT
      LAYER M5 ;
        RECT  152.304 0 152.328 0.084 ;
    END
  END xai[145]
  PIN xai[146]
    DIRECTION INPUT ;
    USE SIGNAL ;
    PORT
      LAYER M5 ;
        RECT  152.448 0 152.472 0.084 ;
    END
  END xai[146]
  PIN xai[147]
    DIRECTION INPUT ;
    USE SIGNAL ;
    PORT
      LAYER M5 ;
        RECT  152.592 0 152.616 0.084 ;
    END
  END xai[147]
  PIN xai[148]
    DIRECTION INPUT ;
    USE SIGNAL ;
    PORT
      LAYER M5 ;
        RECT  152.736 0 152.76 0.084 ;
    END
  END xai[148]
  PIN xai[149]
    DIRECTION INPUT ;
    USE SIGNAL ;
    PORT
      LAYER M5 ;
        RECT  152.88 0 152.904 0.084 ;
    END
  END xai[149]
  PIN xai[14]
    DIRECTION INPUT ;
    USE SIGNAL ;
    PORT
      LAYER M5 ;
        RECT  133.44 0 133.464 0.084 ;
    END
  END xai[14]
  PIN xai[150]
    DIRECTION INPUT ;
    USE SIGNAL ;
    PORT
      LAYER M5 ;
        RECT  153.024 0 153.048 0.084 ;
    END
  END xai[150]
  PIN xai[151]
    DIRECTION INPUT ;
    USE SIGNAL ;
    PORT
      LAYER M5 ;
        RECT  153.168 0 153.192 0.084 ;
    END
  END xai[151]
  PIN xai[152]
    DIRECTION INPUT ;
    USE SIGNAL ;
    PORT
      LAYER M5 ;
        RECT  153.312 0 153.336 0.084 ;
    END
  END xai[152]
  PIN xai[153]
    DIRECTION INPUT ;
    USE SIGNAL ;
    PORT
      LAYER M5 ;
        RECT  153.456 0 153.48 0.084 ;
    END
  END xai[153]
  PIN xai[154]
    DIRECTION INPUT ;
    USE SIGNAL ;
    PORT
      LAYER M5 ;
        RECT  153.6 0 153.624 0.084 ;
    END
  END xai[154]
  PIN xai[155]
    DIRECTION INPUT ;
    USE SIGNAL ;
    PORT
      LAYER M5 ;
        RECT  153.744 0 153.768 0.084 ;
    END
  END xai[155]
  PIN xai[156]
    DIRECTION INPUT ;
    USE SIGNAL ;
    PORT
      LAYER M5 ;
        RECT  153.888 0 153.912 0.084 ;
    END
  END xai[156]
  PIN xai[157]
    DIRECTION INPUT ;
    USE SIGNAL ;
    PORT
      LAYER M5 ;
        RECT  154.032 0 154.056 0.084 ;
    END
  END xai[157]
  PIN xai[158]
    DIRECTION INPUT ;
    USE SIGNAL ;
    PORT
      LAYER M5 ;
        RECT  154.176 0 154.2 0.084 ;
    END
  END xai[158]
  PIN xai[159]
    DIRECTION INPUT ;
    USE SIGNAL ;
    PORT
      LAYER M5 ;
        RECT  154.32 0 154.344 0.084 ;
    END
  END xai[159]
  PIN xai[15]
    DIRECTION INPUT ;
    USE SIGNAL ;
    PORT
      LAYER M5 ;
        RECT  133.584 0 133.608 0.084 ;
    END
  END xai[15]
  PIN xai[160]
    DIRECTION INPUT ;
    USE SIGNAL ;
    PORT
      LAYER M5 ;
        RECT  154.464 0 154.488 0.084 ;
    END
  END xai[160]
  PIN xai[161]
    DIRECTION INPUT ;
    USE SIGNAL ;
    PORT
      LAYER M5 ;
        RECT  154.608 0 154.632 0.084 ;
    END
  END xai[161]
  PIN xai[162]
    DIRECTION INPUT ;
    USE SIGNAL ;
    PORT
      LAYER M5 ;
        RECT  154.752 0 154.776 0.084 ;
    END
  END xai[162]
  PIN xai[163]
    DIRECTION INPUT ;
    USE SIGNAL ;
    PORT
      LAYER M5 ;
        RECT  154.896 0 154.92 0.084 ;
    END
  END xai[163]
  PIN xai[164]
    DIRECTION INPUT ;
    USE SIGNAL ;
    PORT
      LAYER M5 ;
        RECT  155.04 0 155.064 0.084 ;
    END
  END xai[164]
  PIN xai[165]
    DIRECTION INPUT ;
    USE SIGNAL ;
    PORT
      LAYER M5 ;
        RECT  155.184 0 155.208 0.084 ;
    END
  END xai[165]
  PIN xai[166]
    DIRECTION INPUT ;
    USE SIGNAL ;
    PORT
      LAYER M5 ;
        RECT  155.328 0 155.352 0.084 ;
    END
  END xai[166]
  PIN xai[167]
    DIRECTION INPUT ;
    USE SIGNAL ;
    PORT
      LAYER M5 ;
        RECT  155.472 0 155.496 0.084 ;
    END
  END xai[167]
  PIN xai[168]
    DIRECTION INPUT ;
    USE SIGNAL ;
    PORT
      LAYER M5 ;
        RECT  155.616 0 155.64 0.084 ;
    END
  END xai[168]
  PIN xai[169]
    DIRECTION INPUT ;
    USE SIGNAL ;
    PORT
      LAYER M5 ;
        RECT  155.76 0 155.784 0.084 ;
    END
  END xai[169]
  PIN xai[16]
    DIRECTION INPUT ;
    USE SIGNAL ;
    PORT
      LAYER M5 ;
        RECT  133.728 0 133.752 0.084 ;
    END
  END xai[16]
  PIN xai[170]
    DIRECTION INPUT ;
    USE SIGNAL ;
    PORT
      LAYER M5 ;
        RECT  155.904 0 155.928 0.084 ;
    END
  END xai[170]
  PIN xai[171]
    DIRECTION INPUT ;
    USE SIGNAL ;
    PORT
      LAYER M5 ;
        RECT  156.048 0 156.072 0.084 ;
    END
  END xai[171]
  PIN xai[172]
    DIRECTION INPUT ;
    USE SIGNAL ;
    PORT
      LAYER M5 ;
        RECT  156.192 0 156.216 0.084 ;
    END
  END xai[172]
  PIN xai[173]
    DIRECTION INPUT ;
    USE SIGNAL ;
    PORT
      LAYER M5 ;
        RECT  156.336 0 156.36 0.084 ;
    END
  END xai[173]
  PIN xai[174]
    DIRECTION INPUT ;
    USE SIGNAL ;
    PORT
      LAYER M5 ;
        RECT  156.48 0 156.504 0.084 ;
    END
  END xai[174]
  PIN xai[175]
    DIRECTION INPUT ;
    USE SIGNAL ;
    PORT
      LAYER M5 ;
        RECT  156.624 0 156.648 0.084 ;
    END
  END xai[175]
  PIN xai[176]
    DIRECTION INPUT ;
    USE SIGNAL ;
    PORT
      LAYER M5 ;
        RECT  156.768 0 156.792 0.084 ;
    END
  END xai[176]
  PIN xai[177]
    DIRECTION INPUT ;
    USE SIGNAL ;
    PORT
      LAYER M5 ;
        RECT  156.912 0 156.936 0.084 ;
    END
  END xai[177]
  PIN xai[178]
    DIRECTION INPUT ;
    USE SIGNAL ;
    PORT
      LAYER M5 ;
        RECT  157.056 0 157.08 0.084 ;
    END
  END xai[178]
  PIN xai[179]
    DIRECTION INPUT ;
    USE SIGNAL ;
    PORT
      LAYER M5 ;
        RECT  157.2 0 157.224 0.084 ;
    END
  END xai[179]
  PIN xai[17]
    DIRECTION INPUT ;
    USE SIGNAL ;
    PORT
      LAYER M5 ;
        RECT  133.872 0 133.896 0.084 ;
    END
  END xai[17]
  PIN xai[180]
    DIRECTION INPUT ;
    USE SIGNAL ;
    PORT
      LAYER M5 ;
        RECT  157.344 0 157.368 0.084 ;
    END
  END xai[180]
  PIN xai[181]
    DIRECTION INPUT ;
    USE SIGNAL ;
    PORT
      LAYER M5 ;
        RECT  157.488 0 157.512 0.084 ;
    END
  END xai[181]
  PIN xai[182]
    DIRECTION INPUT ;
    USE SIGNAL ;
    PORT
      LAYER M5 ;
        RECT  157.632 0 157.656 0.084 ;
    END
  END xai[182]
  PIN xai[183]
    DIRECTION INPUT ;
    USE SIGNAL ;
    PORT
      LAYER M5 ;
        RECT  157.776 0 157.8 0.084 ;
    END
  END xai[183]
  PIN xai[184]
    DIRECTION INPUT ;
    USE SIGNAL ;
    PORT
      LAYER M5 ;
        RECT  157.92 0 157.944 0.084 ;
    END
  END xai[184]
  PIN xai[185]
    DIRECTION INPUT ;
    USE SIGNAL ;
    PORT
      LAYER M5 ;
        RECT  158.064 0 158.088 0.084 ;
    END
  END xai[185]
  PIN xai[186]
    DIRECTION INPUT ;
    USE SIGNAL ;
    PORT
      LAYER M5 ;
        RECT  158.208 0 158.232 0.084 ;
    END
  END xai[186]
  PIN xai[187]
    DIRECTION INPUT ;
    USE SIGNAL ;
    PORT
      LAYER M5 ;
        RECT  158.352 0 158.376 0.084 ;
    END
  END xai[187]
  PIN xai[188]
    DIRECTION INPUT ;
    USE SIGNAL ;
    PORT
      LAYER M5 ;
        RECT  158.496 0 158.52 0.084 ;
    END
  END xai[188]
  PIN xai[189]
    DIRECTION INPUT ;
    USE SIGNAL ;
    PORT
      LAYER M5 ;
        RECT  158.64 0 158.664 0.084 ;
    END
  END xai[189]
  PIN xai[18]
    DIRECTION INPUT ;
    USE SIGNAL ;
    PORT
      LAYER M5 ;
        RECT  134.016 0 134.04 0.084 ;
    END
  END xai[18]
  PIN xai[190]
    DIRECTION INPUT ;
    USE SIGNAL ;
    PORT
      LAYER M5 ;
        RECT  158.784 0 158.808 0.084 ;
    END
  END xai[190]
  PIN xai[191]
    DIRECTION INPUT ;
    USE SIGNAL ;
    PORT
      LAYER M5 ;
        RECT  158.928 0 158.952 0.084 ;
    END
  END xai[191]
  PIN xai[192]
    DIRECTION INPUT ;
    USE SIGNAL ;
    PORT
      LAYER M5 ;
        RECT  159.072 0 159.096 0.084 ;
    END
  END xai[192]
  PIN xai[193]
    DIRECTION INPUT ;
    USE SIGNAL ;
    PORT
      LAYER M5 ;
        RECT  159.216 0 159.24 0.084 ;
    END
  END xai[193]
  PIN xai[194]
    DIRECTION INPUT ;
    USE SIGNAL ;
    PORT
      LAYER M5 ;
        RECT  159.36 0 159.384 0.084 ;
    END
  END xai[194]
  PIN xai[195]
    DIRECTION INPUT ;
    USE SIGNAL ;
    PORT
      LAYER M5 ;
        RECT  159.504 0 159.528 0.084 ;
    END
  END xai[195]
  PIN xai[196]
    DIRECTION INPUT ;
    USE SIGNAL ;
    PORT
      LAYER M5 ;
        RECT  159.648 0 159.672 0.084 ;
    END
  END xai[196]
  PIN xai[197]
    DIRECTION INPUT ;
    USE SIGNAL ;
    PORT
      LAYER M5 ;
        RECT  159.792 0 159.816 0.084 ;
    END
  END xai[197]
  PIN xai[198]
    DIRECTION INPUT ;
    USE SIGNAL ;
    PORT
      LAYER M5 ;
        RECT  159.936 0 159.96 0.084 ;
    END
  END xai[198]
  PIN xai[199]
    DIRECTION INPUT ;
    USE SIGNAL ;
    PORT
      LAYER M5 ;
        RECT  160.08 0 160.104 0.084 ;
    END
  END xai[199]
  PIN xai[19]
    DIRECTION INPUT ;
    USE SIGNAL ;
    PORT
      LAYER M5 ;
        RECT  134.16 0 134.184 0.084 ;
    END
  END xai[19]
  PIN xai[1]
    DIRECTION INPUT ;
    USE SIGNAL ;
    PORT
      LAYER M5 ;
        RECT  131.568 0 131.592 0.084 ;
    END
  END xai[1]
  PIN xai[200]
    DIRECTION INPUT ;
    USE SIGNAL ;
    PORT
      LAYER M5 ;
        RECT  160.224 0 160.248 0.084 ;
    END
  END xai[200]
  PIN xai[201]
    DIRECTION INPUT ;
    USE SIGNAL ;
    PORT
      LAYER M5 ;
        RECT  160.368 0 160.392 0.084 ;
    END
  END xai[201]
  PIN xai[202]
    DIRECTION INPUT ;
    USE SIGNAL ;
    PORT
      LAYER M5 ;
        RECT  160.512 0 160.536 0.084 ;
    END
  END xai[202]
  PIN xai[203]
    DIRECTION INPUT ;
    USE SIGNAL ;
    PORT
      LAYER M5 ;
        RECT  160.656 0 160.68 0.084 ;
    END
  END xai[203]
  PIN xai[204]
    DIRECTION INPUT ;
    USE SIGNAL ;
    PORT
      LAYER M5 ;
        RECT  160.8 0 160.824 0.084 ;
    END
  END xai[204]
  PIN xai[205]
    DIRECTION INPUT ;
    USE SIGNAL ;
    PORT
      LAYER M5 ;
        RECT  160.944 0 160.968 0.084 ;
    END
  END xai[205]
  PIN xai[206]
    DIRECTION INPUT ;
    USE SIGNAL ;
    PORT
      LAYER M5 ;
        RECT  161.088 0 161.112 0.084 ;
    END
  END xai[206]
  PIN xai[207]
    DIRECTION INPUT ;
    USE SIGNAL ;
    PORT
      LAYER M5 ;
        RECT  161.232 0 161.256 0.084 ;
    END
  END xai[207]
  PIN xai[208]
    DIRECTION INPUT ;
    USE SIGNAL ;
    PORT
      LAYER M5 ;
        RECT  161.376 0 161.4 0.084 ;
    END
  END xai[208]
  PIN xai[209]
    DIRECTION INPUT ;
    USE SIGNAL ;
    PORT
      LAYER M5 ;
        RECT  161.52 0 161.544 0.084 ;
    END
  END xai[209]
  PIN xai[20]
    DIRECTION INPUT ;
    USE SIGNAL ;
    PORT
      LAYER M5 ;
        RECT  134.304 0 134.328 0.084 ;
    END
  END xai[20]
  PIN xai[210]
    DIRECTION INPUT ;
    USE SIGNAL ;
    PORT
      LAYER M5 ;
        RECT  161.664 0 161.688 0.084 ;
    END
  END xai[210]
  PIN xai[211]
    DIRECTION INPUT ;
    USE SIGNAL ;
    PORT
      LAYER M5 ;
        RECT  161.808 0 161.832 0.084 ;
    END
  END xai[211]
  PIN xai[212]
    DIRECTION INPUT ;
    USE SIGNAL ;
    PORT
      LAYER M5 ;
        RECT  161.952 0 161.976 0.084 ;
    END
  END xai[212]
  PIN xai[213]
    DIRECTION INPUT ;
    USE SIGNAL ;
    PORT
      LAYER M5 ;
        RECT  162.096 0 162.12 0.084 ;
    END
  END xai[213]
  PIN xai[214]
    DIRECTION INPUT ;
    USE SIGNAL ;
    PORT
      LAYER M5 ;
        RECT  162.24 0 162.264 0.084 ;
    END
  END xai[214]
  PIN xai[215]
    DIRECTION INPUT ;
    USE SIGNAL ;
    PORT
      LAYER M5 ;
        RECT  162.384 0 162.408 0.084 ;
    END
  END xai[215]
  PIN xai[216]
    DIRECTION INPUT ;
    USE SIGNAL ;
    PORT
      LAYER M5 ;
        RECT  162.528 0 162.552 0.084 ;
    END
  END xai[216]
  PIN xai[217]
    DIRECTION INPUT ;
    USE SIGNAL ;
    PORT
      LAYER M5 ;
        RECT  162.672 0 162.696 0.084 ;
    END
  END xai[217]
  PIN xai[218]
    DIRECTION INPUT ;
    USE SIGNAL ;
    PORT
      LAYER M5 ;
        RECT  162.816 0 162.84 0.084 ;
    END
  END xai[218]
  PIN xai[219]
    DIRECTION INPUT ;
    USE SIGNAL ;
    PORT
      LAYER M5 ;
        RECT  162.96 0 162.984 0.084 ;
    END
  END xai[219]
  PIN xai[21]
    DIRECTION INPUT ;
    USE SIGNAL ;
    PORT
      LAYER M5 ;
        RECT  134.448 0 134.472 0.084 ;
    END
  END xai[21]
  PIN xai[220]
    DIRECTION INPUT ;
    USE SIGNAL ;
    PORT
      LAYER M5 ;
        RECT  163.104 0 163.128 0.084 ;
    END
  END xai[220]
  PIN xai[221]
    DIRECTION INPUT ;
    USE SIGNAL ;
    PORT
      LAYER M5 ;
        RECT  163.248 0 163.272 0.084 ;
    END
  END xai[221]
  PIN xai[222]
    DIRECTION INPUT ;
    USE SIGNAL ;
    PORT
      LAYER M5 ;
        RECT  163.392 0 163.416 0.084 ;
    END
  END xai[222]
  PIN xai[223]
    DIRECTION INPUT ;
    USE SIGNAL ;
    PORT
      LAYER M5 ;
        RECT  163.536 0 163.56 0.084 ;
    END
  END xai[223]
  PIN xai[224]
    DIRECTION INPUT ;
    USE SIGNAL ;
    PORT
      LAYER M5 ;
        RECT  163.68 0 163.704 0.084 ;
    END
  END xai[224]
  PIN xai[225]
    DIRECTION INPUT ;
    USE SIGNAL ;
    PORT
      LAYER M5 ;
        RECT  163.824 0 163.848 0.084 ;
    END
  END xai[225]
  PIN xai[226]
    DIRECTION INPUT ;
    USE SIGNAL ;
    PORT
      LAYER M5 ;
        RECT  163.968 0 163.992 0.084 ;
    END
  END xai[226]
  PIN xai[227]
    DIRECTION INPUT ;
    USE SIGNAL ;
    PORT
      LAYER M5 ;
        RECT  164.112 0 164.136 0.084 ;
    END
  END xai[227]
  PIN xai[228]
    DIRECTION INPUT ;
    USE SIGNAL ;
    PORT
      LAYER M5 ;
        RECT  164.256 0 164.28 0.084 ;
    END
  END xai[228]
  PIN xai[229]
    DIRECTION INPUT ;
    USE SIGNAL ;
    PORT
      LAYER M5 ;
        RECT  164.4 0 164.424 0.084 ;
    END
  END xai[229]
  PIN xai[22]
    DIRECTION INPUT ;
    USE SIGNAL ;
    PORT
      LAYER M5 ;
        RECT  134.592 0 134.616 0.084 ;
    END
  END xai[22]
  PIN xai[230]
    DIRECTION INPUT ;
    USE SIGNAL ;
    PORT
      LAYER M5 ;
        RECT  164.544 0 164.568 0.084 ;
    END
  END xai[230]
  PIN xai[231]
    DIRECTION INPUT ;
    USE SIGNAL ;
    PORT
      LAYER M5 ;
        RECT  164.688 0 164.712 0.084 ;
    END
  END xai[231]
  PIN xai[232]
    DIRECTION INPUT ;
    USE SIGNAL ;
    PORT
      LAYER M5 ;
        RECT  164.832 0 164.856 0.084 ;
    END
  END xai[232]
  PIN xai[233]
    DIRECTION INPUT ;
    USE SIGNAL ;
    PORT
      LAYER M5 ;
        RECT  164.976 0 165 0.084 ;
    END
  END xai[233]
  PIN xai[234]
    DIRECTION INPUT ;
    USE SIGNAL ;
    PORT
      LAYER M5 ;
        RECT  165.12 0 165.144 0.084 ;
    END
  END xai[234]
  PIN xai[235]
    DIRECTION INPUT ;
    USE SIGNAL ;
    PORT
      LAYER M5 ;
        RECT  165.264 0 165.288 0.084 ;
    END
  END xai[235]
  PIN xai[236]
    DIRECTION INPUT ;
    USE SIGNAL ;
    PORT
      LAYER M5 ;
        RECT  165.408 0 165.432 0.084 ;
    END
  END xai[236]
  PIN xai[237]
    DIRECTION INPUT ;
    USE SIGNAL ;
    PORT
      LAYER M5 ;
        RECT  165.552 0 165.576 0.084 ;
    END
  END xai[237]
  PIN xai[238]
    DIRECTION INPUT ;
    USE SIGNAL ;
    PORT
      LAYER M5 ;
        RECT  165.696 0 165.72 0.084 ;
    END
  END xai[238]
  PIN xai[239]
    DIRECTION INPUT ;
    USE SIGNAL ;
    PORT
      LAYER M5 ;
        RECT  165.84 0 165.864 0.084 ;
    END
  END xai[239]
  PIN xai[23]
    DIRECTION INPUT ;
    USE SIGNAL ;
    PORT
      LAYER M5 ;
        RECT  134.736 0 134.76 0.084 ;
    END
  END xai[23]
  PIN xai[240]
    DIRECTION INPUT ;
    USE SIGNAL ;
    PORT
      LAYER M5 ;
        RECT  165.984 0 166.008 0.084 ;
    END
  END xai[240]
  PIN xai[241]
    DIRECTION INPUT ;
    USE SIGNAL ;
    PORT
      LAYER M5 ;
        RECT  166.128 0 166.152 0.084 ;
    END
  END xai[241]
  PIN xai[242]
    DIRECTION INPUT ;
    USE SIGNAL ;
    PORT
      LAYER M5 ;
        RECT  166.272 0 166.296 0.084 ;
    END
  END xai[242]
  PIN xai[243]
    DIRECTION INPUT ;
    USE SIGNAL ;
    PORT
      LAYER M5 ;
        RECT  166.416 0 166.44 0.084 ;
    END
  END xai[243]
  PIN xai[244]
    DIRECTION INPUT ;
    USE SIGNAL ;
    PORT
      LAYER M5 ;
        RECT  166.56 0 166.584 0.084 ;
    END
  END xai[244]
  PIN xai[245]
    DIRECTION INPUT ;
    USE SIGNAL ;
    PORT
      LAYER M5 ;
        RECT  166.704 0 166.728 0.084 ;
    END
  END xai[245]
  PIN xai[246]
    DIRECTION INPUT ;
    USE SIGNAL ;
    PORT
      LAYER M5 ;
        RECT  166.848 0 166.872 0.084 ;
    END
  END xai[246]
  PIN xai[247]
    DIRECTION INPUT ;
    USE SIGNAL ;
    PORT
      LAYER M5 ;
        RECT  166.992 0 167.016 0.084 ;
    END
  END xai[247]
  PIN xai[248]
    DIRECTION INPUT ;
    USE SIGNAL ;
    PORT
      LAYER M5 ;
        RECT  167.136 0 167.16 0.084 ;
    END
  END xai[248]
  PIN xai[249]
    DIRECTION INPUT ;
    USE SIGNAL ;
    PORT
      LAYER M5 ;
        RECT  167.28 0 167.304 0.084 ;
    END
  END xai[249]
  PIN xai[24]
    DIRECTION INPUT ;
    USE SIGNAL ;
    PORT
      LAYER M5 ;
        RECT  134.88 0 134.904 0.084 ;
    END
  END xai[24]
  PIN xai[250]
    DIRECTION INPUT ;
    USE SIGNAL ;
    PORT
      LAYER M5 ;
        RECT  167.424 0 167.448 0.084 ;
    END
  END xai[250]
  PIN xai[251]
    DIRECTION INPUT ;
    USE SIGNAL ;
    PORT
      LAYER M5 ;
        RECT  167.568 0 167.592 0.084 ;
    END
  END xai[251]
  PIN xai[252]
    DIRECTION INPUT ;
    USE SIGNAL ;
    PORT
      LAYER M5 ;
        RECT  167.712 0 167.736 0.084 ;
    END
  END xai[252]
  PIN xai[253]
    DIRECTION INPUT ;
    USE SIGNAL ;
    PORT
      LAYER M5 ;
        RECT  167.856 0 167.88 0.084 ;
    END
  END xai[253]
  PIN xai[254]
    DIRECTION INPUT ;
    USE SIGNAL ;
    PORT
      LAYER M5 ;
        RECT  168 0 168.024 0.084 ;
    END
  END xai[254]
  PIN xai[255]
    DIRECTION INPUT ;
    USE SIGNAL ;
    PORT
      LAYER M5 ;
        RECT  168.144 0 168.168 0.084 ;
    END
  END xai[255]
  PIN xai[256]
    DIRECTION INPUT ;
    USE SIGNAL ;
    PORT
      LAYER M5 ;
        RECT  168.288 0 168.312 0.084 ;
    END
  END xai[256]
  PIN xai[257]
    DIRECTION INPUT ;
    USE SIGNAL ;
    PORT
      LAYER M5 ;
        RECT  168.432 0 168.456 0.084 ;
    END
  END xai[257]
  PIN xai[258]
    DIRECTION INPUT ;
    USE SIGNAL ;
    PORT
      LAYER M5 ;
        RECT  168.576 0 168.6 0.084 ;
    END
  END xai[258]
  PIN xai[259]
    DIRECTION INPUT ;
    USE SIGNAL ;
    PORT
      LAYER M5 ;
        RECT  168.72 0 168.744 0.084 ;
    END
  END xai[259]
  PIN xai[25]
    DIRECTION INPUT ;
    USE SIGNAL ;
    PORT
      LAYER M5 ;
        RECT  135.024 0 135.048 0.084 ;
    END
  END xai[25]
  PIN xai[260]
    DIRECTION INPUT ;
    USE SIGNAL ;
    PORT
      LAYER M5 ;
        RECT  168.864 0 168.888 0.084 ;
    END
  END xai[260]
  PIN xai[261]
    DIRECTION INPUT ;
    USE SIGNAL ;
    PORT
      LAYER M5 ;
        RECT  169.008 0 169.032 0.084 ;
    END
  END xai[261]
  PIN xai[262]
    DIRECTION INPUT ;
    USE SIGNAL ;
    PORT
      LAYER M5 ;
        RECT  169.152 0 169.176 0.084 ;
    END
  END xai[262]
  PIN xai[263]
    DIRECTION INPUT ;
    USE SIGNAL ;
    PORT
      LAYER M5 ;
        RECT  169.296 0 169.32 0.084 ;
    END
  END xai[263]
  PIN xai[264]
    DIRECTION INPUT ;
    USE SIGNAL ;
    PORT
      LAYER M5 ;
        RECT  169.44 0 169.464 0.084 ;
    END
  END xai[264]
  PIN xai[265]
    DIRECTION INPUT ;
    USE SIGNAL ;
    PORT
      LAYER M5 ;
        RECT  169.584 0 169.608 0.084 ;
    END
  END xai[265]
  PIN xai[266]
    DIRECTION INPUT ;
    USE SIGNAL ;
    PORT
      LAYER M5 ;
        RECT  169.728 0 169.752 0.084 ;
    END
  END xai[266]
  PIN xai[267]
    DIRECTION INPUT ;
    USE SIGNAL ;
    PORT
      LAYER M5 ;
        RECT  169.872 0 169.896 0.084 ;
    END
  END xai[267]
  PIN xai[268]
    DIRECTION INPUT ;
    USE SIGNAL ;
    PORT
      LAYER M5 ;
        RECT  170.016 0 170.04 0.084 ;
    END
  END xai[268]
  PIN xai[269]
    DIRECTION INPUT ;
    USE SIGNAL ;
    PORT
      LAYER M5 ;
        RECT  170.16 0 170.184 0.084 ;
    END
  END xai[269]
  PIN xai[26]
    DIRECTION INPUT ;
    USE SIGNAL ;
    PORT
      LAYER M5 ;
        RECT  135.168 0 135.192 0.084 ;
    END
  END xai[26]
  PIN xai[270]
    DIRECTION INPUT ;
    USE SIGNAL ;
    PORT
      LAYER M5 ;
        RECT  170.304 0 170.328 0.084 ;
    END
  END xai[270]
  PIN xai[271]
    DIRECTION INPUT ;
    USE SIGNAL ;
    PORT
      LAYER M5 ;
        RECT  170.448 0 170.472 0.084 ;
    END
  END xai[271]
  PIN xai[272]
    DIRECTION INPUT ;
    USE SIGNAL ;
    PORT
      LAYER M5 ;
        RECT  170.592 0 170.616 0.084 ;
    END
  END xai[272]
  PIN xai[273]
    DIRECTION INPUT ;
    USE SIGNAL ;
    PORT
      LAYER M5 ;
        RECT  170.736 0 170.76 0.084 ;
    END
  END xai[273]
  PIN xai[274]
    DIRECTION INPUT ;
    USE SIGNAL ;
    PORT
      LAYER M5 ;
        RECT  170.88 0 170.904 0.084 ;
    END
  END xai[274]
  PIN xai[275]
    DIRECTION INPUT ;
    USE SIGNAL ;
    PORT
      LAYER M5 ;
        RECT  171.024 0 171.048 0.084 ;
    END
  END xai[275]
  PIN xai[276]
    DIRECTION INPUT ;
    USE SIGNAL ;
    PORT
      LAYER M5 ;
        RECT  171.168 0 171.192 0.084 ;
    END
  END xai[276]
  PIN xai[277]
    DIRECTION INPUT ;
    USE SIGNAL ;
    PORT
      LAYER M5 ;
        RECT  171.312 0 171.336 0.084 ;
    END
  END xai[277]
  PIN xai[278]
    DIRECTION INPUT ;
    USE SIGNAL ;
    PORT
      LAYER M5 ;
        RECT  171.456 0 171.48 0.084 ;
    END
  END xai[278]
  PIN xai[279]
    DIRECTION INPUT ;
    USE SIGNAL ;
    PORT
      LAYER M5 ;
        RECT  171.6 0 171.624 0.084 ;
    END
  END xai[279]
  PIN xai[27]
    DIRECTION INPUT ;
    USE SIGNAL ;
    PORT
      LAYER M5 ;
        RECT  135.312 0 135.336 0.084 ;
    END
  END xai[27]
  PIN xai[280]
    DIRECTION INPUT ;
    USE SIGNAL ;
    PORT
      LAYER M5 ;
        RECT  171.744 0 171.768 0.084 ;
    END
  END xai[280]
  PIN xai[281]
    DIRECTION INPUT ;
    USE SIGNAL ;
    PORT
      LAYER M5 ;
        RECT  171.888 0 171.912 0.084 ;
    END
  END xai[281]
  PIN xai[282]
    DIRECTION INPUT ;
    USE SIGNAL ;
    PORT
      LAYER M5 ;
        RECT  172.032 0 172.056 0.084 ;
    END
  END xai[282]
  PIN xai[28]
    DIRECTION INPUT ;
    USE SIGNAL ;
    PORT
      LAYER M5 ;
        RECT  135.456 0 135.48 0.084 ;
    END
  END xai[28]
  PIN xai[29]
    DIRECTION INPUT ;
    USE SIGNAL ;
    PORT
      LAYER M5 ;
        RECT  135.6 0 135.624 0.084 ;
    END
  END xai[29]
  PIN xai[2]
    DIRECTION INPUT ;
    USE SIGNAL ;
    PORT
      LAYER M5 ;
        RECT  131.712 0 131.736 0.084 ;
    END
  END xai[2]
  PIN xai[30]
    DIRECTION INPUT ;
    USE SIGNAL ;
    PORT
      LAYER M5 ;
        RECT  135.744 0 135.768 0.084 ;
    END
  END xai[30]
  PIN xai[31]
    DIRECTION INPUT ;
    USE SIGNAL ;
    PORT
      LAYER M5 ;
        RECT  135.888 0 135.912 0.084 ;
    END
  END xai[31]
  PIN xai[32]
    DIRECTION INPUT ;
    USE SIGNAL ;
    PORT
      LAYER M5 ;
        RECT  136.032 0 136.056 0.084 ;
    END
  END xai[32]
  PIN xai[33]
    DIRECTION INPUT ;
    USE SIGNAL ;
    PORT
      LAYER M5 ;
        RECT  136.176 0 136.2 0.084 ;
    END
  END xai[33]
  PIN xai[34]
    DIRECTION INPUT ;
    USE SIGNAL ;
    PORT
      LAYER M5 ;
        RECT  136.32 0 136.344 0.084 ;
    END
  END xai[34]
  PIN xai[35]
    DIRECTION INPUT ;
    USE SIGNAL ;
    PORT
      LAYER M5 ;
        RECT  136.464 0 136.488 0.084 ;
    END
  END xai[35]
  PIN xai[36]
    DIRECTION INPUT ;
    USE SIGNAL ;
    PORT
      LAYER M5 ;
        RECT  136.608 0 136.632 0.084 ;
    END
  END xai[36]
  PIN xai[37]
    DIRECTION INPUT ;
    USE SIGNAL ;
    PORT
      LAYER M5 ;
        RECT  136.752 0 136.776 0.084 ;
    END
  END xai[37]
  PIN xai[38]
    DIRECTION INPUT ;
    USE SIGNAL ;
    PORT
      LAYER M5 ;
        RECT  136.896 0 136.92 0.084 ;
    END
  END xai[38]
  PIN xai[39]
    DIRECTION INPUT ;
    USE SIGNAL ;
    PORT
      LAYER M5 ;
        RECT  137.04 0 137.064 0.084 ;
    END
  END xai[39]
  PIN xai[3]
    DIRECTION INPUT ;
    USE SIGNAL ;
    PORT
      LAYER M5 ;
        RECT  131.856 0 131.88 0.084 ;
    END
  END xai[3]
  PIN xai[40]
    DIRECTION INPUT ;
    USE SIGNAL ;
    PORT
      LAYER M5 ;
        RECT  137.184 0 137.208 0.084 ;
    END
  END xai[40]
  PIN xai[41]
    DIRECTION INPUT ;
    USE SIGNAL ;
    PORT
      LAYER M5 ;
        RECT  137.328 0 137.352 0.084 ;
    END
  END xai[41]
  PIN xai[42]
    DIRECTION INPUT ;
    USE SIGNAL ;
    PORT
      LAYER M5 ;
        RECT  137.472 0 137.496 0.084 ;
    END
  END xai[42]
  PIN xai[43]
    DIRECTION INPUT ;
    USE SIGNAL ;
    PORT
      LAYER M5 ;
        RECT  137.616 0 137.64 0.084 ;
    END
  END xai[43]
  PIN xai[44]
    DIRECTION INPUT ;
    USE SIGNAL ;
    PORT
      LAYER M5 ;
        RECT  137.76 0 137.784 0.084 ;
    END
  END xai[44]
  PIN xai[45]
    DIRECTION INPUT ;
    USE SIGNAL ;
    PORT
      LAYER M5 ;
        RECT  137.904 0 137.928 0.084 ;
    END
  END xai[45]
  PIN xai[46]
    DIRECTION INPUT ;
    USE SIGNAL ;
    PORT
      LAYER M5 ;
        RECT  138.048 0 138.072 0.084 ;
    END
  END xai[46]
  PIN xai[47]
    DIRECTION INPUT ;
    USE SIGNAL ;
    PORT
      LAYER M5 ;
        RECT  138.192 0 138.216 0.084 ;
    END
  END xai[47]
  PIN xai[48]
    DIRECTION INPUT ;
    USE SIGNAL ;
    PORT
      LAYER M5 ;
        RECT  138.336 0 138.36 0.084 ;
    END
  END xai[48]
  PIN xai[49]
    DIRECTION INPUT ;
    USE SIGNAL ;
    PORT
      LAYER M5 ;
        RECT  138.48 0 138.504 0.084 ;
    END
  END xai[49]
  PIN xai[4]
    DIRECTION INPUT ;
    USE SIGNAL ;
    PORT
      LAYER M5 ;
        RECT  132 0 132.024 0.084 ;
    END
  END xai[4]
  PIN xai[50]
    DIRECTION INPUT ;
    USE SIGNAL ;
    PORT
      LAYER M5 ;
        RECT  138.624 0 138.648 0.084 ;
    END
  END xai[50]
  PIN xai[51]
    DIRECTION INPUT ;
    USE SIGNAL ;
    PORT
      LAYER M5 ;
        RECT  138.768 0 138.792 0.084 ;
    END
  END xai[51]
  PIN xai[52]
    DIRECTION INPUT ;
    USE SIGNAL ;
    PORT
      LAYER M5 ;
        RECT  138.912 0 138.936 0.084 ;
    END
  END xai[52]
  PIN xai[53]
    DIRECTION INPUT ;
    USE SIGNAL ;
    PORT
      LAYER M5 ;
        RECT  139.056 0 139.08 0.084 ;
    END
  END xai[53]
  PIN xai[54]
    DIRECTION INPUT ;
    USE SIGNAL ;
    PORT
      LAYER M5 ;
        RECT  139.2 0 139.224 0.084 ;
    END
  END xai[54]
  PIN xai[55]
    DIRECTION INPUT ;
    USE SIGNAL ;
    PORT
      LAYER M5 ;
        RECT  139.344 0 139.368 0.084 ;
    END
  END xai[55]
  PIN xai[56]
    DIRECTION INPUT ;
    USE SIGNAL ;
    PORT
      LAYER M5 ;
        RECT  139.488 0 139.512 0.084 ;
    END
  END xai[56]
  PIN xai[57]
    DIRECTION INPUT ;
    USE SIGNAL ;
    PORT
      LAYER M5 ;
        RECT  139.632 0 139.656 0.084 ;
    END
  END xai[57]
  PIN xai[58]
    DIRECTION INPUT ;
    USE SIGNAL ;
    PORT
      LAYER M5 ;
        RECT  139.776 0 139.8 0.084 ;
    END
  END xai[58]
  PIN xai[59]
    DIRECTION INPUT ;
    USE SIGNAL ;
    PORT
      LAYER M5 ;
        RECT  139.92 0 139.944 0.084 ;
    END
  END xai[59]
  PIN xai[5]
    DIRECTION INPUT ;
    USE SIGNAL ;
    PORT
      LAYER M5 ;
        RECT  132.144 0 132.168 0.084 ;
    END
  END xai[5]
  PIN xai[60]
    DIRECTION INPUT ;
    USE SIGNAL ;
    PORT
      LAYER M5 ;
        RECT  140.064 0 140.088 0.084 ;
    END
  END xai[60]
  PIN xai[61]
    DIRECTION INPUT ;
    USE SIGNAL ;
    PORT
      LAYER M5 ;
        RECT  140.208 0 140.232 0.084 ;
    END
  END xai[61]
  PIN xai[62]
    DIRECTION INPUT ;
    USE SIGNAL ;
    PORT
      LAYER M5 ;
        RECT  140.352 0 140.376 0.084 ;
    END
  END xai[62]
  PIN xai[63]
    DIRECTION INPUT ;
    USE SIGNAL ;
    PORT
      LAYER M5 ;
        RECT  140.496 0 140.52 0.084 ;
    END
  END xai[63]
  PIN xai[64]
    DIRECTION INPUT ;
    USE SIGNAL ;
    PORT
      LAYER M5 ;
        RECT  140.64 0 140.664 0.084 ;
    END
  END xai[64]
  PIN xai[65]
    DIRECTION INPUT ;
    USE SIGNAL ;
    PORT
      LAYER M5 ;
        RECT  140.784 0 140.808 0.084 ;
    END
  END xai[65]
  PIN xai[66]
    DIRECTION INPUT ;
    USE SIGNAL ;
    PORT
      LAYER M5 ;
        RECT  140.928 0 140.952 0.084 ;
    END
  END xai[66]
  PIN xai[67]
    DIRECTION INPUT ;
    USE SIGNAL ;
    PORT
      LAYER M5 ;
        RECT  141.072 0 141.096 0.084 ;
    END
  END xai[67]
  PIN xai[68]
    DIRECTION INPUT ;
    USE SIGNAL ;
    PORT
      LAYER M5 ;
        RECT  141.216 0 141.24 0.084 ;
    END
  END xai[68]
  PIN xai[69]
    DIRECTION INPUT ;
    USE SIGNAL ;
    PORT
      LAYER M5 ;
        RECT  141.36 0 141.384 0.084 ;
    END
  END xai[69]
  PIN xai[6]
    DIRECTION INPUT ;
    USE SIGNAL ;
    PORT
      LAYER M5 ;
        RECT  132.288 0 132.312 0.084 ;
    END
  END xai[6]
  PIN xai[70]
    DIRECTION INPUT ;
    USE SIGNAL ;
    PORT
      LAYER M5 ;
        RECT  141.504 0 141.528 0.084 ;
    END
  END xai[70]
  PIN xai[71]
    DIRECTION INPUT ;
    USE SIGNAL ;
    PORT
      LAYER M5 ;
        RECT  141.648 0 141.672 0.084 ;
    END
  END xai[71]
  PIN xai[72]
    DIRECTION INPUT ;
    USE SIGNAL ;
    PORT
      LAYER M5 ;
        RECT  141.792 0 141.816 0.084 ;
    END
  END xai[72]
  PIN xai[73]
    DIRECTION INPUT ;
    USE SIGNAL ;
    PORT
      LAYER M5 ;
        RECT  141.936 0 141.96 0.084 ;
    END
  END xai[73]
  PIN xai[74]
    DIRECTION INPUT ;
    USE SIGNAL ;
    PORT
      LAYER M5 ;
        RECT  142.08 0 142.104 0.084 ;
    END
  END xai[74]
  PIN xai[75]
    DIRECTION INPUT ;
    USE SIGNAL ;
    PORT
      LAYER M5 ;
        RECT  142.224 0 142.248 0.084 ;
    END
  END xai[75]
  PIN xai[76]
    DIRECTION INPUT ;
    USE SIGNAL ;
    PORT
      LAYER M5 ;
        RECT  142.368 0 142.392 0.084 ;
    END
  END xai[76]
  PIN xai[77]
    DIRECTION INPUT ;
    USE SIGNAL ;
    PORT
      LAYER M5 ;
        RECT  142.512 0 142.536 0.084 ;
    END
  END xai[77]
  PIN xai[78]
    DIRECTION INPUT ;
    USE SIGNAL ;
    PORT
      LAYER M5 ;
        RECT  142.656 0 142.68 0.084 ;
    END
  END xai[78]
  PIN xai[79]
    DIRECTION INPUT ;
    USE SIGNAL ;
    PORT
      LAYER M5 ;
        RECT  142.8 0 142.824 0.084 ;
    END
  END xai[79]
  PIN xai[7]
    DIRECTION INPUT ;
    USE SIGNAL ;
    PORT
      LAYER M5 ;
        RECT  132.432 0 132.456 0.084 ;
    END
  END xai[7]
  PIN xai[80]
    DIRECTION INPUT ;
    USE SIGNAL ;
    PORT
      LAYER M5 ;
        RECT  142.944 0 142.968 0.084 ;
    END
  END xai[80]
  PIN xai[81]
    DIRECTION INPUT ;
    USE SIGNAL ;
    PORT
      LAYER M5 ;
        RECT  143.088 0 143.112 0.084 ;
    END
  END xai[81]
  PIN xai[82]
    DIRECTION INPUT ;
    USE SIGNAL ;
    PORT
      LAYER M5 ;
        RECT  143.232 0 143.256 0.084 ;
    END
  END xai[82]
  PIN xai[83]
    DIRECTION INPUT ;
    USE SIGNAL ;
    PORT
      LAYER M5 ;
        RECT  143.376 0 143.4 0.084 ;
    END
  END xai[83]
  PIN xai[84]
    DIRECTION INPUT ;
    USE SIGNAL ;
    PORT
      LAYER M5 ;
        RECT  143.52 0 143.544 0.084 ;
    END
  END xai[84]
  PIN xai[85]
    DIRECTION INPUT ;
    USE SIGNAL ;
    PORT
      LAYER M5 ;
        RECT  143.664 0 143.688 0.084 ;
    END
  END xai[85]
  PIN xai[86]
    DIRECTION INPUT ;
    USE SIGNAL ;
    PORT
      LAYER M5 ;
        RECT  143.808 0 143.832 0.084 ;
    END
  END xai[86]
  PIN xai[87]
    DIRECTION INPUT ;
    USE SIGNAL ;
    PORT
      LAYER M5 ;
        RECT  143.952 0 143.976 0.084 ;
    END
  END xai[87]
  PIN xai[88]
    DIRECTION INPUT ;
    USE SIGNAL ;
    PORT
      LAYER M5 ;
        RECT  144.096 0 144.12 0.084 ;
    END
  END xai[88]
  PIN xai[89]
    DIRECTION INPUT ;
    USE SIGNAL ;
    PORT
      LAYER M5 ;
        RECT  144.24 0 144.264 0.084 ;
    END
  END xai[89]
  PIN xai[8]
    DIRECTION INPUT ;
    USE SIGNAL ;
    PORT
      LAYER M5 ;
        RECT  132.576 0 132.6 0.084 ;
    END
  END xai[8]
  PIN xai[90]
    DIRECTION INPUT ;
    USE SIGNAL ;
    PORT
      LAYER M5 ;
        RECT  144.384 0 144.408 0.084 ;
    END
  END xai[90]
  PIN xai[91]
    DIRECTION INPUT ;
    USE SIGNAL ;
    PORT
      LAYER M5 ;
        RECT  144.528 0 144.552 0.084 ;
    END
  END xai[91]
  PIN xai[92]
    DIRECTION INPUT ;
    USE SIGNAL ;
    PORT
      LAYER M5 ;
        RECT  144.672 0 144.696 0.084 ;
    END
  END xai[92]
  PIN xai[93]
    DIRECTION INPUT ;
    USE SIGNAL ;
    PORT
      LAYER M5 ;
        RECT  144.816 0 144.84 0.084 ;
    END
  END xai[93]
  PIN xai[94]
    DIRECTION INPUT ;
    USE SIGNAL ;
    PORT
      LAYER M5 ;
        RECT  144.96 0 144.984 0.084 ;
    END
  END xai[94]
  PIN xai[95]
    DIRECTION INPUT ;
    USE SIGNAL ;
    PORT
      LAYER M5 ;
        RECT  145.104 0 145.128 0.084 ;
    END
  END xai[95]
  PIN xai[96]
    DIRECTION INPUT ;
    USE SIGNAL ;
    PORT
      LAYER M5 ;
        RECT  145.248 0 145.272 0.084 ;
    END
  END xai[96]
  PIN xai[97]
    DIRECTION INPUT ;
    USE SIGNAL ;
    PORT
      LAYER M5 ;
        RECT  145.392 0 145.416 0.084 ;
    END
  END xai[97]
  PIN xai[98]
    DIRECTION INPUT ;
    USE SIGNAL ;
    PORT
      LAYER M5 ;
        RECT  145.536 0 145.56 0.084 ;
    END
  END xai[98]
  PIN xai[99]
    DIRECTION INPUT ;
    USE SIGNAL ;
    PORT
      LAYER M5 ;
        RECT  145.68 0 145.704 0.084 ;
    END
  END xai[99]
  PIN xai[9]
    DIRECTION INPUT ;
    USE SIGNAL ;
    PORT
      LAYER M5 ;
        RECT  132.72 0 132.744 0.084 ;
    END
  END xai[9]
  PIN xb[0]
    DIRECTION OUTPUT ;
    USE SIGNAL ;
    PORT
      LAYER M5 ;
        RECT  90.912 30.156 90.936 30.24 ;
    END
  END xb[0]
  PIN xb[100]
    DIRECTION OUTPUT ;
    USE SIGNAL ;
    PORT
      LAYER M5 ;
        RECT  105.312 30.156 105.336 30.24 ;
    END
  END xb[100]
  PIN xb[101]
    DIRECTION OUTPUT ;
    USE SIGNAL ;
    PORT
      LAYER M5 ;
        RECT  105.456 30.156 105.48 30.24 ;
    END
  END xb[101]
  PIN xb[102]
    DIRECTION OUTPUT ;
    USE SIGNAL ;
    PORT
      LAYER M5 ;
        RECT  105.6 30.156 105.624 30.24 ;
    END
  END xb[102]
  PIN xb[103]
    DIRECTION OUTPUT ;
    USE SIGNAL ;
    PORT
      LAYER M5 ;
        RECT  105.744 30.156 105.768 30.24 ;
    END
  END xb[103]
  PIN xb[104]
    DIRECTION OUTPUT ;
    USE SIGNAL ;
    PORT
      LAYER M5 ;
        RECT  105.888 30.156 105.912 30.24 ;
    END
  END xb[104]
  PIN xb[105]
    DIRECTION OUTPUT ;
    USE SIGNAL ;
    PORT
      LAYER M5 ;
        RECT  106.032 30.156 106.056 30.24 ;
    END
  END xb[105]
  PIN xb[106]
    DIRECTION OUTPUT ;
    USE SIGNAL ;
    PORT
      LAYER M5 ;
        RECT  106.176 30.156 106.2 30.24 ;
    END
  END xb[106]
  PIN xb[107]
    DIRECTION OUTPUT ;
    USE SIGNAL ;
    PORT
      LAYER M5 ;
        RECT  106.32 30.156 106.344 30.24 ;
    END
  END xb[107]
  PIN xb[108]
    DIRECTION OUTPUT ;
    USE SIGNAL ;
    PORT
      LAYER M5 ;
        RECT  106.464 30.156 106.488 30.24 ;
    END
  END xb[108]
  PIN xb[109]
    DIRECTION OUTPUT ;
    USE SIGNAL ;
    PORT
      LAYER M5 ;
        RECT  106.608 30.156 106.632 30.24 ;
    END
  END xb[109]
  PIN xb[10]
    DIRECTION OUTPUT ;
    USE SIGNAL ;
    PORT
      LAYER M5 ;
        RECT  92.352 30.156 92.376 30.24 ;
    END
  END xb[10]
  PIN xb[110]
    DIRECTION OUTPUT ;
    USE SIGNAL ;
    PORT
      LAYER M5 ;
        RECT  106.752 30.156 106.776 30.24 ;
    END
  END xb[110]
  PIN xb[111]
    DIRECTION OUTPUT ;
    USE SIGNAL ;
    PORT
      LAYER M5 ;
        RECT  106.896 30.156 106.92 30.24 ;
    END
  END xb[111]
  PIN xb[112]
    DIRECTION OUTPUT ;
    USE SIGNAL ;
    PORT
      LAYER M5 ;
        RECT  107.04 30.156 107.064 30.24 ;
    END
  END xb[112]
  PIN xb[113]
    DIRECTION OUTPUT ;
    USE SIGNAL ;
    PORT
      LAYER M5 ;
        RECT  107.184 30.156 107.208 30.24 ;
    END
  END xb[113]
  PIN xb[114]
    DIRECTION OUTPUT ;
    USE SIGNAL ;
    PORT
      LAYER M5 ;
        RECT  107.328 30.156 107.352 30.24 ;
    END
  END xb[114]
  PIN xb[115]
    DIRECTION OUTPUT ;
    USE SIGNAL ;
    PORT
      LAYER M5 ;
        RECT  107.472 30.156 107.496 30.24 ;
    END
  END xb[115]
  PIN xb[116]
    DIRECTION OUTPUT ;
    USE SIGNAL ;
    PORT
      LAYER M5 ;
        RECT  107.616 30.156 107.64 30.24 ;
    END
  END xb[116]
  PIN xb[117]
    DIRECTION OUTPUT ;
    USE SIGNAL ;
    PORT
      LAYER M5 ;
        RECT  107.76 30.156 107.784 30.24 ;
    END
  END xb[117]
  PIN xb[118]
    DIRECTION OUTPUT ;
    USE SIGNAL ;
    PORT
      LAYER M5 ;
        RECT  107.904 30.156 107.928 30.24 ;
    END
  END xb[118]
  PIN xb[119]
    DIRECTION OUTPUT ;
    USE SIGNAL ;
    PORT
      LAYER M5 ;
        RECT  108.048 30.156 108.072 30.24 ;
    END
  END xb[119]
  PIN xb[11]
    DIRECTION OUTPUT ;
    USE SIGNAL ;
    PORT
      LAYER M5 ;
        RECT  92.496 30.156 92.52 30.24 ;
    END
  END xb[11]
  PIN xb[120]
    DIRECTION OUTPUT ;
    USE SIGNAL ;
    PORT
      LAYER M5 ;
        RECT  108.192 30.156 108.216 30.24 ;
    END
  END xb[120]
  PIN xb[121]
    DIRECTION OUTPUT ;
    USE SIGNAL ;
    PORT
      LAYER M5 ;
        RECT  108.336 30.156 108.36 30.24 ;
    END
  END xb[121]
  PIN xb[122]
    DIRECTION OUTPUT ;
    USE SIGNAL ;
    PORT
      LAYER M5 ;
        RECT  108.48 30.156 108.504 30.24 ;
    END
  END xb[122]
  PIN xb[123]
    DIRECTION OUTPUT ;
    USE SIGNAL ;
    PORT
      LAYER M5 ;
        RECT  108.624 30.156 108.648 30.24 ;
    END
  END xb[123]
  PIN xb[124]
    DIRECTION OUTPUT ;
    USE SIGNAL ;
    PORT
      LAYER M5 ;
        RECT  108.768 30.156 108.792 30.24 ;
    END
  END xb[124]
  PIN xb[125]
    DIRECTION OUTPUT ;
    USE SIGNAL ;
    PORT
      LAYER M5 ;
        RECT  108.912 30.156 108.936 30.24 ;
    END
  END xb[125]
  PIN xb[126]
    DIRECTION OUTPUT ;
    USE SIGNAL ;
    PORT
      LAYER M5 ;
        RECT  109.056 30.156 109.08 30.24 ;
    END
  END xb[126]
  PIN xb[127]
    DIRECTION OUTPUT ;
    USE SIGNAL ;
    PORT
      LAYER M5 ;
        RECT  109.2 30.156 109.224 30.24 ;
    END
  END xb[127]
  PIN xb[128]
    DIRECTION OUTPUT ;
    USE SIGNAL ;
    PORT
      LAYER M5 ;
        RECT  109.344 30.156 109.368 30.24 ;
    END
  END xb[128]
  PIN xb[129]
    DIRECTION OUTPUT ;
    USE SIGNAL ;
    PORT
      LAYER M5 ;
        RECT  109.488 30.156 109.512 30.24 ;
    END
  END xb[129]
  PIN xb[12]
    DIRECTION OUTPUT ;
    USE SIGNAL ;
    PORT
      LAYER M5 ;
        RECT  92.64 30.156 92.664 30.24 ;
    END
  END xb[12]
  PIN xb[130]
    DIRECTION OUTPUT ;
    USE SIGNAL ;
    PORT
      LAYER M5 ;
        RECT  109.632 30.156 109.656 30.24 ;
    END
  END xb[130]
  PIN xb[131]
    DIRECTION OUTPUT ;
    USE SIGNAL ;
    PORT
      LAYER M5 ;
        RECT  109.776 30.156 109.8 30.24 ;
    END
  END xb[131]
  PIN xb[132]
    DIRECTION OUTPUT ;
    USE SIGNAL ;
    PORT
      LAYER M5 ;
        RECT  109.92 30.156 109.944 30.24 ;
    END
  END xb[132]
  PIN xb[133]
    DIRECTION OUTPUT ;
    USE SIGNAL ;
    PORT
      LAYER M5 ;
        RECT  110.064 30.156 110.088 30.24 ;
    END
  END xb[133]
  PIN xb[134]
    DIRECTION OUTPUT ;
    USE SIGNAL ;
    PORT
      LAYER M5 ;
        RECT  110.208 30.156 110.232 30.24 ;
    END
  END xb[134]
  PIN xb[135]
    DIRECTION OUTPUT ;
    USE SIGNAL ;
    PORT
      LAYER M5 ;
        RECT  110.352 30.156 110.376 30.24 ;
    END
  END xb[135]
  PIN xb[136]
    DIRECTION OUTPUT ;
    USE SIGNAL ;
    PORT
      LAYER M5 ;
        RECT  110.496 30.156 110.52 30.24 ;
    END
  END xb[136]
  PIN xb[137]
    DIRECTION OUTPUT ;
    USE SIGNAL ;
    PORT
      LAYER M5 ;
        RECT  110.64 30.156 110.664 30.24 ;
    END
  END xb[137]
  PIN xb[138]
    DIRECTION OUTPUT ;
    USE SIGNAL ;
    PORT
      LAYER M5 ;
        RECT  110.784 30.156 110.808 30.24 ;
    END
  END xb[138]
  PIN xb[139]
    DIRECTION OUTPUT ;
    USE SIGNAL ;
    PORT
      LAYER M5 ;
        RECT  110.928 30.156 110.952 30.24 ;
    END
  END xb[139]
  PIN xb[13]
    DIRECTION OUTPUT ;
    USE SIGNAL ;
    PORT
      LAYER M5 ;
        RECT  92.784 30.156 92.808 30.24 ;
    END
  END xb[13]
  PIN xb[140]
    DIRECTION OUTPUT ;
    USE SIGNAL ;
    PORT
      LAYER M5 ;
        RECT  111.072 30.156 111.096 30.24 ;
    END
  END xb[140]
  PIN xb[141]
    DIRECTION OUTPUT ;
    USE SIGNAL ;
    PORT
      LAYER M5 ;
        RECT  111.216 30.156 111.24 30.24 ;
    END
  END xb[141]
  PIN xb[142]
    DIRECTION OUTPUT ;
    USE SIGNAL ;
    PORT
      LAYER M5 ;
        RECT  111.36 30.156 111.384 30.24 ;
    END
  END xb[142]
  PIN xb[143]
    DIRECTION OUTPUT ;
    USE SIGNAL ;
    PORT
      LAYER M5 ;
        RECT  111.504 30.156 111.528 30.24 ;
    END
  END xb[143]
  PIN xb[144]
    DIRECTION OUTPUT ;
    USE SIGNAL ;
    PORT
      LAYER M5 ;
        RECT  111.648 30.156 111.672 30.24 ;
    END
  END xb[144]
  PIN xb[145]
    DIRECTION OUTPUT ;
    USE SIGNAL ;
    PORT
      LAYER M5 ;
        RECT  111.792 30.156 111.816 30.24 ;
    END
  END xb[145]
  PIN xb[146]
    DIRECTION OUTPUT ;
    USE SIGNAL ;
    PORT
      LAYER M5 ;
        RECT  111.936 30.156 111.96 30.24 ;
    END
  END xb[146]
  PIN xb[147]
    DIRECTION OUTPUT ;
    USE SIGNAL ;
    PORT
      LAYER M5 ;
        RECT  112.08 30.156 112.104 30.24 ;
    END
  END xb[147]
  PIN xb[148]
    DIRECTION OUTPUT ;
    USE SIGNAL ;
    PORT
      LAYER M5 ;
        RECT  112.224 30.156 112.248 30.24 ;
    END
  END xb[148]
  PIN xb[149]
    DIRECTION OUTPUT ;
    USE SIGNAL ;
    PORT
      LAYER M5 ;
        RECT  112.368 30.156 112.392 30.24 ;
    END
  END xb[149]
  PIN xb[14]
    DIRECTION OUTPUT ;
    USE SIGNAL ;
    PORT
      LAYER M5 ;
        RECT  92.928 30.156 92.952 30.24 ;
    END
  END xb[14]
  PIN xb[150]
    DIRECTION OUTPUT ;
    USE SIGNAL ;
    PORT
      LAYER M5 ;
        RECT  112.512 30.156 112.536 30.24 ;
    END
  END xb[150]
  PIN xb[151]
    DIRECTION OUTPUT ;
    USE SIGNAL ;
    PORT
      LAYER M5 ;
        RECT  112.656 30.156 112.68 30.24 ;
    END
  END xb[151]
  PIN xb[152]
    DIRECTION OUTPUT ;
    USE SIGNAL ;
    PORT
      LAYER M5 ;
        RECT  112.8 30.156 112.824 30.24 ;
    END
  END xb[152]
  PIN xb[153]
    DIRECTION OUTPUT ;
    USE SIGNAL ;
    PORT
      LAYER M5 ;
        RECT  112.944 30.156 112.968 30.24 ;
    END
  END xb[153]
  PIN xb[154]
    DIRECTION OUTPUT ;
    USE SIGNAL ;
    PORT
      LAYER M5 ;
        RECT  113.088 30.156 113.112 30.24 ;
    END
  END xb[154]
  PIN xb[155]
    DIRECTION OUTPUT ;
    USE SIGNAL ;
    PORT
      LAYER M5 ;
        RECT  113.232 30.156 113.256 30.24 ;
    END
  END xb[155]
  PIN xb[156]
    DIRECTION OUTPUT ;
    USE SIGNAL ;
    PORT
      LAYER M5 ;
        RECT  113.376 30.156 113.4 30.24 ;
    END
  END xb[156]
  PIN xb[157]
    DIRECTION OUTPUT ;
    USE SIGNAL ;
    PORT
      LAYER M5 ;
        RECT  113.52 30.156 113.544 30.24 ;
    END
  END xb[157]
  PIN xb[158]
    DIRECTION OUTPUT ;
    USE SIGNAL ;
    PORT
      LAYER M5 ;
        RECT  113.664 30.156 113.688 30.24 ;
    END
  END xb[158]
  PIN xb[159]
    DIRECTION OUTPUT ;
    USE SIGNAL ;
    PORT
      LAYER M5 ;
        RECT  113.808 30.156 113.832 30.24 ;
    END
  END xb[159]
  PIN xb[15]
    DIRECTION OUTPUT ;
    USE SIGNAL ;
    PORT
      LAYER M5 ;
        RECT  93.072 30.156 93.096 30.24 ;
    END
  END xb[15]
  PIN xb[160]
    DIRECTION OUTPUT ;
    USE SIGNAL ;
    PORT
      LAYER M5 ;
        RECT  113.952 30.156 113.976 30.24 ;
    END
  END xb[160]
  PIN xb[161]
    DIRECTION OUTPUT ;
    USE SIGNAL ;
    PORT
      LAYER M5 ;
        RECT  114.096 30.156 114.12 30.24 ;
    END
  END xb[161]
  PIN xb[162]
    DIRECTION OUTPUT ;
    USE SIGNAL ;
    PORT
      LAYER M5 ;
        RECT  114.24 30.156 114.264 30.24 ;
    END
  END xb[162]
  PIN xb[163]
    DIRECTION OUTPUT ;
    USE SIGNAL ;
    PORT
      LAYER M5 ;
        RECT  114.384 30.156 114.408 30.24 ;
    END
  END xb[163]
  PIN xb[164]
    DIRECTION OUTPUT ;
    USE SIGNAL ;
    PORT
      LAYER M5 ;
        RECT  114.528 30.156 114.552 30.24 ;
    END
  END xb[164]
  PIN xb[165]
    DIRECTION OUTPUT ;
    USE SIGNAL ;
    PORT
      LAYER M5 ;
        RECT  114.672 30.156 114.696 30.24 ;
    END
  END xb[165]
  PIN xb[166]
    DIRECTION OUTPUT ;
    USE SIGNAL ;
    PORT
      LAYER M5 ;
        RECT  114.816 30.156 114.84 30.24 ;
    END
  END xb[166]
  PIN xb[167]
    DIRECTION OUTPUT ;
    USE SIGNAL ;
    PORT
      LAYER M5 ;
        RECT  114.96 30.156 114.984 30.24 ;
    END
  END xb[167]
  PIN xb[168]
    DIRECTION OUTPUT ;
    USE SIGNAL ;
    PORT
      LAYER M5 ;
        RECT  115.104 30.156 115.128 30.24 ;
    END
  END xb[168]
  PIN xb[169]
    DIRECTION OUTPUT ;
    USE SIGNAL ;
    PORT
      LAYER M5 ;
        RECT  115.248 30.156 115.272 30.24 ;
    END
  END xb[169]
  PIN xb[16]
    DIRECTION OUTPUT ;
    USE SIGNAL ;
    PORT
      LAYER M5 ;
        RECT  93.216 30.156 93.24 30.24 ;
    END
  END xb[16]
  PIN xb[170]
    DIRECTION OUTPUT ;
    USE SIGNAL ;
    PORT
      LAYER M5 ;
        RECT  115.392 30.156 115.416 30.24 ;
    END
  END xb[170]
  PIN xb[171]
    DIRECTION OUTPUT ;
    USE SIGNAL ;
    PORT
      LAYER M5 ;
        RECT  115.536 30.156 115.56 30.24 ;
    END
  END xb[171]
  PIN xb[172]
    DIRECTION OUTPUT ;
    USE SIGNAL ;
    PORT
      LAYER M5 ;
        RECT  115.68 30.156 115.704 30.24 ;
    END
  END xb[172]
  PIN xb[173]
    DIRECTION OUTPUT ;
    USE SIGNAL ;
    PORT
      LAYER M5 ;
        RECT  115.824 30.156 115.848 30.24 ;
    END
  END xb[173]
  PIN xb[174]
    DIRECTION OUTPUT ;
    USE SIGNAL ;
    PORT
      LAYER M5 ;
        RECT  115.968 30.156 115.992 30.24 ;
    END
  END xb[174]
  PIN xb[175]
    DIRECTION OUTPUT ;
    USE SIGNAL ;
    PORT
      LAYER M5 ;
        RECT  116.112 30.156 116.136 30.24 ;
    END
  END xb[175]
  PIN xb[176]
    DIRECTION OUTPUT ;
    USE SIGNAL ;
    PORT
      LAYER M5 ;
        RECT  116.256 30.156 116.28 30.24 ;
    END
  END xb[176]
  PIN xb[177]
    DIRECTION OUTPUT ;
    USE SIGNAL ;
    PORT
      LAYER M5 ;
        RECT  116.4 30.156 116.424 30.24 ;
    END
  END xb[177]
  PIN xb[178]
    DIRECTION OUTPUT ;
    USE SIGNAL ;
    PORT
      LAYER M5 ;
        RECT  116.544 30.156 116.568 30.24 ;
    END
  END xb[178]
  PIN xb[179]
    DIRECTION OUTPUT ;
    USE SIGNAL ;
    PORT
      LAYER M5 ;
        RECT  116.688 30.156 116.712 30.24 ;
    END
  END xb[179]
  PIN xb[17]
    DIRECTION OUTPUT ;
    USE SIGNAL ;
    PORT
      LAYER M5 ;
        RECT  93.36 30.156 93.384 30.24 ;
    END
  END xb[17]
  PIN xb[180]
    DIRECTION OUTPUT ;
    USE SIGNAL ;
    PORT
      LAYER M5 ;
        RECT  116.832 30.156 116.856 30.24 ;
    END
  END xb[180]
  PIN xb[181]
    DIRECTION OUTPUT ;
    USE SIGNAL ;
    PORT
      LAYER M5 ;
        RECT  116.976 30.156 117 30.24 ;
    END
  END xb[181]
  PIN xb[182]
    DIRECTION OUTPUT ;
    USE SIGNAL ;
    PORT
      LAYER M5 ;
        RECT  117.12 30.156 117.144 30.24 ;
    END
  END xb[182]
  PIN xb[183]
    DIRECTION OUTPUT ;
    USE SIGNAL ;
    PORT
      LAYER M5 ;
        RECT  117.264 30.156 117.288 30.24 ;
    END
  END xb[183]
  PIN xb[184]
    DIRECTION OUTPUT ;
    USE SIGNAL ;
    PORT
      LAYER M5 ;
        RECT  117.408 30.156 117.432 30.24 ;
    END
  END xb[184]
  PIN xb[185]
    DIRECTION OUTPUT ;
    USE SIGNAL ;
    PORT
      LAYER M5 ;
        RECT  117.552 30.156 117.576 30.24 ;
    END
  END xb[185]
  PIN xb[186]
    DIRECTION OUTPUT ;
    USE SIGNAL ;
    PORT
      LAYER M5 ;
        RECT  117.696 30.156 117.72 30.24 ;
    END
  END xb[186]
  PIN xb[187]
    DIRECTION OUTPUT ;
    USE SIGNAL ;
    PORT
      LAYER M5 ;
        RECT  117.84 30.156 117.864 30.24 ;
    END
  END xb[187]
  PIN xb[188]
    DIRECTION OUTPUT ;
    USE SIGNAL ;
    PORT
      LAYER M5 ;
        RECT  117.984 30.156 118.008 30.24 ;
    END
  END xb[188]
  PIN xb[189]
    DIRECTION OUTPUT ;
    USE SIGNAL ;
    PORT
      LAYER M5 ;
        RECT  118.128 30.156 118.152 30.24 ;
    END
  END xb[189]
  PIN xb[18]
    DIRECTION OUTPUT ;
    USE SIGNAL ;
    PORT
      LAYER M5 ;
        RECT  93.504 30.156 93.528 30.24 ;
    END
  END xb[18]
  PIN xb[190]
    DIRECTION OUTPUT ;
    USE SIGNAL ;
    PORT
      LAYER M5 ;
        RECT  118.272 30.156 118.296 30.24 ;
    END
  END xb[190]
  PIN xb[191]
    DIRECTION OUTPUT ;
    USE SIGNAL ;
    PORT
      LAYER M5 ;
        RECT  118.416 30.156 118.44 30.24 ;
    END
  END xb[191]
  PIN xb[192]
    DIRECTION OUTPUT ;
    USE SIGNAL ;
    PORT
      LAYER M5 ;
        RECT  118.56 30.156 118.584 30.24 ;
    END
  END xb[192]
  PIN xb[193]
    DIRECTION OUTPUT ;
    USE SIGNAL ;
    PORT
      LAYER M5 ;
        RECT  118.704 30.156 118.728 30.24 ;
    END
  END xb[193]
  PIN xb[194]
    DIRECTION OUTPUT ;
    USE SIGNAL ;
    PORT
      LAYER M5 ;
        RECT  118.848 30.156 118.872 30.24 ;
    END
  END xb[194]
  PIN xb[195]
    DIRECTION OUTPUT ;
    USE SIGNAL ;
    PORT
      LAYER M5 ;
        RECT  118.992 30.156 119.016 30.24 ;
    END
  END xb[195]
  PIN xb[196]
    DIRECTION OUTPUT ;
    USE SIGNAL ;
    PORT
      LAYER M5 ;
        RECT  119.136 30.156 119.16 30.24 ;
    END
  END xb[196]
  PIN xb[197]
    DIRECTION OUTPUT ;
    USE SIGNAL ;
    PORT
      LAYER M5 ;
        RECT  119.28 30.156 119.304 30.24 ;
    END
  END xb[197]
  PIN xb[198]
    DIRECTION OUTPUT ;
    USE SIGNAL ;
    PORT
      LAYER M5 ;
        RECT  119.424 30.156 119.448 30.24 ;
    END
  END xb[198]
  PIN xb[199]
    DIRECTION OUTPUT ;
    USE SIGNAL ;
    PORT
      LAYER M5 ;
        RECT  119.568 30.156 119.592 30.24 ;
    END
  END xb[199]
  PIN xb[19]
    DIRECTION OUTPUT ;
    USE SIGNAL ;
    PORT
      LAYER M5 ;
        RECT  93.648 30.156 93.672 30.24 ;
    END
  END xb[19]
  PIN xb[1]
    DIRECTION OUTPUT ;
    USE SIGNAL ;
    PORT
      LAYER M5 ;
        RECT  91.056 30.156 91.08 30.24 ;
    END
  END xb[1]
  PIN xb[200]
    DIRECTION OUTPUT ;
    USE SIGNAL ;
    PORT
      LAYER M5 ;
        RECT  119.712 30.156 119.736 30.24 ;
    END
  END xb[200]
  PIN xb[201]
    DIRECTION OUTPUT ;
    USE SIGNAL ;
    PORT
      LAYER M5 ;
        RECT  119.856 30.156 119.88 30.24 ;
    END
  END xb[201]
  PIN xb[202]
    DIRECTION OUTPUT ;
    USE SIGNAL ;
    PORT
      LAYER M5 ;
        RECT  120 30.156 120.024 30.24 ;
    END
  END xb[202]
  PIN xb[203]
    DIRECTION OUTPUT ;
    USE SIGNAL ;
    PORT
      LAYER M5 ;
        RECT  120.144 30.156 120.168 30.24 ;
    END
  END xb[203]
  PIN xb[204]
    DIRECTION OUTPUT ;
    USE SIGNAL ;
    PORT
      LAYER M5 ;
        RECT  120.288 30.156 120.312 30.24 ;
    END
  END xb[204]
  PIN xb[205]
    DIRECTION OUTPUT ;
    USE SIGNAL ;
    PORT
      LAYER M5 ;
        RECT  120.432 30.156 120.456 30.24 ;
    END
  END xb[205]
  PIN xb[206]
    DIRECTION OUTPUT ;
    USE SIGNAL ;
    PORT
      LAYER M5 ;
        RECT  120.576 30.156 120.6 30.24 ;
    END
  END xb[206]
  PIN xb[207]
    DIRECTION OUTPUT ;
    USE SIGNAL ;
    PORT
      LAYER M5 ;
        RECT  120.72 30.156 120.744 30.24 ;
    END
  END xb[207]
  PIN xb[208]
    DIRECTION OUTPUT ;
    USE SIGNAL ;
    PORT
      LAYER M5 ;
        RECT  120.864 30.156 120.888 30.24 ;
    END
  END xb[208]
  PIN xb[209]
    DIRECTION OUTPUT ;
    USE SIGNAL ;
    PORT
      LAYER M5 ;
        RECT  121.008 30.156 121.032 30.24 ;
    END
  END xb[209]
  PIN xb[20]
    DIRECTION OUTPUT ;
    USE SIGNAL ;
    PORT
      LAYER M5 ;
        RECT  93.792 30.156 93.816 30.24 ;
    END
  END xb[20]
  PIN xb[210]
    DIRECTION OUTPUT ;
    USE SIGNAL ;
    PORT
      LAYER M5 ;
        RECT  121.152 30.156 121.176 30.24 ;
    END
  END xb[210]
  PIN xb[211]
    DIRECTION OUTPUT ;
    USE SIGNAL ;
    PORT
      LAYER M5 ;
        RECT  121.296 30.156 121.32 30.24 ;
    END
  END xb[211]
  PIN xb[212]
    DIRECTION OUTPUT ;
    USE SIGNAL ;
    PORT
      LAYER M5 ;
        RECT  121.44 30.156 121.464 30.24 ;
    END
  END xb[212]
  PIN xb[213]
    DIRECTION OUTPUT ;
    USE SIGNAL ;
    PORT
      LAYER M5 ;
        RECT  121.584 30.156 121.608 30.24 ;
    END
  END xb[213]
  PIN xb[214]
    DIRECTION OUTPUT ;
    USE SIGNAL ;
    PORT
      LAYER M5 ;
        RECT  121.728 30.156 121.752 30.24 ;
    END
  END xb[214]
  PIN xb[215]
    DIRECTION OUTPUT ;
    USE SIGNAL ;
    PORT
      LAYER M5 ;
        RECT  121.872 30.156 121.896 30.24 ;
    END
  END xb[215]
  PIN xb[216]
    DIRECTION OUTPUT ;
    USE SIGNAL ;
    PORT
      LAYER M5 ;
        RECT  122.016 30.156 122.04 30.24 ;
    END
  END xb[216]
  PIN xb[217]
    DIRECTION OUTPUT ;
    USE SIGNAL ;
    PORT
      LAYER M5 ;
        RECT  122.16 30.156 122.184 30.24 ;
    END
  END xb[217]
  PIN xb[218]
    DIRECTION OUTPUT ;
    USE SIGNAL ;
    PORT
      LAYER M5 ;
        RECT  122.304 30.156 122.328 30.24 ;
    END
  END xb[218]
  PIN xb[219]
    DIRECTION OUTPUT ;
    USE SIGNAL ;
    PORT
      LAYER M5 ;
        RECT  122.448 30.156 122.472 30.24 ;
    END
  END xb[219]
  PIN xb[21]
    DIRECTION OUTPUT ;
    USE SIGNAL ;
    PORT
      LAYER M5 ;
        RECT  93.936 30.156 93.96 30.24 ;
    END
  END xb[21]
  PIN xb[220]
    DIRECTION OUTPUT ;
    USE SIGNAL ;
    PORT
      LAYER M5 ;
        RECT  122.592 30.156 122.616 30.24 ;
    END
  END xb[220]
  PIN xb[221]
    DIRECTION OUTPUT ;
    USE SIGNAL ;
    PORT
      LAYER M5 ;
        RECT  122.736 30.156 122.76 30.24 ;
    END
  END xb[221]
  PIN xb[222]
    DIRECTION OUTPUT ;
    USE SIGNAL ;
    PORT
      LAYER M5 ;
        RECT  122.88 30.156 122.904 30.24 ;
    END
  END xb[222]
  PIN xb[223]
    DIRECTION OUTPUT ;
    USE SIGNAL ;
    PORT
      LAYER M5 ;
        RECT  123.024 30.156 123.048 30.24 ;
    END
  END xb[223]
  PIN xb[224]
    DIRECTION OUTPUT ;
    USE SIGNAL ;
    PORT
      LAYER M5 ;
        RECT  123.168 30.156 123.192 30.24 ;
    END
  END xb[224]
  PIN xb[225]
    DIRECTION OUTPUT ;
    USE SIGNAL ;
    PORT
      LAYER M5 ;
        RECT  123.312 30.156 123.336 30.24 ;
    END
  END xb[225]
  PIN xb[226]
    DIRECTION OUTPUT ;
    USE SIGNAL ;
    PORT
      LAYER M5 ;
        RECT  123.456 30.156 123.48 30.24 ;
    END
  END xb[226]
  PIN xb[227]
    DIRECTION OUTPUT ;
    USE SIGNAL ;
    PORT
      LAYER M5 ;
        RECT  123.6 30.156 123.624 30.24 ;
    END
  END xb[227]
  PIN xb[228]
    DIRECTION OUTPUT ;
    USE SIGNAL ;
    PORT
      LAYER M5 ;
        RECT  123.744 30.156 123.768 30.24 ;
    END
  END xb[228]
  PIN xb[229]
    DIRECTION OUTPUT ;
    USE SIGNAL ;
    PORT
      LAYER M5 ;
        RECT  123.888 30.156 123.912 30.24 ;
    END
  END xb[229]
  PIN xb[22]
    DIRECTION OUTPUT ;
    USE SIGNAL ;
    PORT
      LAYER M5 ;
        RECT  94.08 30.156 94.104 30.24 ;
    END
  END xb[22]
  PIN xb[230]
    DIRECTION OUTPUT ;
    USE SIGNAL ;
    PORT
      LAYER M5 ;
        RECT  124.032 30.156 124.056 30.24 ;
    END
  END xb[230]
  PIN xb[231]
    DIRECTION OUTPUT ;
    USE SIGNAL ;
    PORT
      LAYER M5 ;
        RECT  124.176 30.156 124.2 30.24 ;
    END
  END xb[231]
  PIN xb[232]
    DIRECTION OUTPUT ;
    USE SIGNAL ;
    PORT
      LAYER M5 ;
        RECT  124.32 30.156 124.344 30.24 ;
    END
  END xb[232]
  PIN xb[233]
    DIRECTION OUTPUT ;
    USE SIGNAL ;
    PORT
      LAYER M5 ;
        RECT  124.464 30.156 124.488 30.24 ;
    END
  END xb[233]
  PIN xb[234]
    DIRECTION OUTPUT ;
    USE SIGNAL ;
    PORT
      LAYER M5 ;
        RECT  124.608 30.156 124.632 30.24 ;
    END
  END xb[234]
  PIN xb[235]
    DIRECTION OUTPUT ;
    USE SIGNAL ;
    PORT
      LAYER M5 ;
        RECT  124.752 30.156 124.776 30.24 ;
    END
  END xb[235]
  PIN xb[236]
    DIRECTION OUTPUT ;
    USE SIGNAL ;
    PORT
      LAYER M5 ;
        RECT  124.896 30.156 124.92 30.24 ;
    END
  END xb[236]
  PIN xb[237]
    DIRECTION OUTPUT ;
    USE SIGNAL ;
    PORT
      LAYER M5 ;
        RECT  125.04 30.156 125.064 30.24 ;
    END
  END xb[237]
  PIN xb[238]
    DIRECTION OUTPUT ;
    USE SIGNAL ;
    PORT
      LAYER M5 ;
        RECT  125.184 30.156 125.208 30.24 ;
    END
  END xb[238]
  PIN xb[239]
    DIRECTION OUTPUT ;
    USE SIGNAL ;
    PORT
      LAYER M5 ;
        RECT  125.328 30.156 125.352 30.24 ;
    END
  END xb[239]
  PIN xb[23]
    DIRECTION OUTPUT ;
    USE SIGNAL ;
    PORT
      LAYER M5 ;
        RECT  94.224 30.156 94.248 30.24 ;
    END
  END xb[23]
  PIN xb[240]
    DIRECTION OUTPUT ;
    USE SIGNAL ;
    PORT
      LAYER M5 ;
        RECT  125.472 30.156 125.496 30.24 ;
    END
  END xb[240]
  PIN xb[241]
    DIRECTION OUTPUT ;
    USE SIGNAL ;
    PORT
      LAYER M5 ;
        RECT  125.616 30.156 125.64 30.24 ;
    END
  END xb[241]
  PIN xb[242]
    DIRECTION OUTPUT ;
    USE SIGNAL ;
    PORT
      LAYER M5 ;
        RECT  125.76 30.156 125.784 30.24 ;
    END
  END xb[242]
  PIN xb[243]
    DIRECTION OUTPUT ;
    USE SIGNAL ;
    PORT
      LAYER M5 ;
        RECT  125.904 30.156 125.928 30.24 ;
    END
  END xb[243]
  PIN xb[244]
    DIRECTION OUTPUT ;
    USE SIGNAL ;
    PORT
      LAYER M5 ;
        RECT  126.048 30.156 126.072 30.24 ;
    END
  END xb[244]
  PIN xb[245]
    DIRECTION OUTPUT ;
    USE SIGNAL ;
    PORT
      LAYER M5 ;
        RECT  126.192 30.156 126.216 30.24 ;
    END
  END xb[245]
  PIN xb[246]
    DIRECTION OUTPUT ;
    USE SIGNAL ;
    PORT
      LAYER M5 ;
        RECT  126.336 30.156 126.36 30.24 ;
    END
  END xb[246]
  PIN xb[247]
    DIRECTION OUTPUT ;
    USE SIGNAL ;
    PORT
      LAYER M5 ;
        RECT  126.48 30.156 126.504 30.24 ;
    END
  END xb[247]
  PIN xb[248]
    DIRECTION OUTPUT ;
    USE SIGNAL ;
    PORT
      LAYER M5 ;
        RECT  126.624 30.156 126.648 30.24 ;
    END
  END xb[248]
  PIN xb[249]
    DIRECTION OUTPUT ;
    USE SIGNAL ;
    PORT
      LAYER M5 ;
        RECT  126.768 30.156 126.792 30.24 ;
    END
  END xb[249]
  PIN xb[24]
    DIRECTION OUTPUT ;
    USE SIGNAL ;
    PORT
      LAYER M5 ;
        RECT  94.368 30.156 94.392 30.24 ;
    END
  END xb[24]
  PIN xb[250]
    DIRECTION OUTPUT ;
    USE SIGNAL ;
    PORT
      LAYER M5 ;
        RECT  126.912 30.156 126.936 30.24 ;
    END
  END xb[250]
  PIN xb[251]
    DIRECTION OUTPUT ;
    USE SIGNAL ;
    PORT
      LAYER M5 ;
        RECT  127.056 30.156 127.08 30.24 ;
    END
  END xb[251]
  PIN xb[252]
    DIRECTION OUTPUT ;
    USE SIGNAL ;
    PORT
      LAYER M5 ;
        RECT  127.2 30.156 127.224 30.24 ;
    END
  END xb[252]
  PIN xb[253]
    DIRECTION OUTPUT ;
    USE SIGNAL ;
    PORT
      LAYER M5 ;
        RECT  127.344 30.156 127.368 30.24 ;
    END
  END xb[253]
  PIN xb[254]
    DIRECTION OUTPUT ;
    USE SIGNAL ;
    PORT
      LAYER M5 ;
        RECT  127.488 30.156 127.512 30.24 ;
    END
  END xb[254]
  PIN xb[255]
    DIRECTION OUTPUT ;
    USE SIGNAL ;
    PORT
      LAYER M5 ;
        RECT  127.632 30.156 127.656 30.24 ;
    END
  END xb[255]
  PIN xb[256]
    DIRECTION OUTPUT ;
    USE SIGNAL ;
    PORT
      LAYER M5 ;
        RECT  127.776 30.156 127.8 30.24 ;
    END
  END xb[256]
  PIN xb[257]
    DIRECTION OUTPUT ;
    USE SIGNAL ;
    PORT
      LAYER M5 ;
        RECT  127.92 30.156 127.944 30.24 ;
    END
  END xb[257]
  PIN xb[258]
    DIRECTION OUTPUT ;
    USE SIGNAL ;
    PORT
      LAYER M5 ;
        RECT  128.064 30.156 128.088 30.24 ;
    END
  END xb[258]
  PIN xb[259]
    DIRECTION OUTPUT ;
    USE SIGNAL ;
    PORT
      LAYER M5 ;
        RECT  128.208 30.156 128.232 30.24 ;
    END
  END xb[259]
  PIN xb[25]
    DIRECTION OUTPUT ;
    USE SIGNAL ;
    PORT
      LAYER M5 ;
        RECT  94.512 30.156 94.536 30.24 ;
    END
  END xb[25]
  PIN xb[260]
    DIRECTION OUTPUT ;
    USE SIGNAL ;
    PORT
      LAYER M5 ;
        RECT  128.352 30.156 128.376 30.24 ;
    END
  END xb[260]
  PIN xb[261]
    DIRECTION OUTPUT ;
    USE SIGNAL ;
    PORT
      LAYER M5 ;
        RECT  128.496 30.156 128.52 30.24 ;
    END
  END xb[261]
  PIN xb[262]
    DIRECTION OUTPUT ;
    USE SIGNAL ;
    PORT
      LAYER M5 ;
        RECT  128.64 30.156 128.664 30.24 ;
    END
  END xb[262]
  PIN xb[263]
    DIRECTION OUTPUT ;
    USE SIGNAL ;
    PORT
      LAYER M5 ;
        RECT  128.784 30.156 128.808 30.24 ;
    END
  END xb[263]
  PIN xb[264]
    DIRECTION OUTPUT ;
    USE SIGNAL ;
    PORT
      LAYER M5 ;
        RECT  128.928 30.156 128.952 30.24 ;
    END
  END xb[264]
  PIN xb[265]
    DIRECTION OUTPUT ;
    USE SIGNAL ;
    PORT
      LAYER M5 ;
        RECT  129.072 30.156 129.096 30.24 ;
    END
  END xb[265]
  PIN xb[26]
    DIRECTION OUTPUT ;
    USE SIGNAL ;
    PORT
      LAYER M5 ;
        RECT  94.656 30.156 94.68 30.24 ;
    END
  END xb[26]
  PIN xb[27]
    DIRECTION OUTPUT ;
    USE SIGNAL ;
    PORT
      LAYER M5 ;
        RECT  94.8 30.156 94.824 30.24 ;
    END
  END xb[27]
  PIN xb[28]
    DIRECTION OUTPUT ;
    USE SIGNAL ;
    PORT
      LAYER M5 ;
        RECT  94.944 30.156 94.968 30.24 ;
    END
  END xb[28]
  PIN xb[29]
    DIRECTION OUTPUT ;
    USE SIGNAL ;
    PORT
      LAYER M5 ;
        RECT  95.088 30.156 95.112 30.24 ;
    END
  END xb[29]
  PIN xb[2]
    DIRECTION OUTPUT ;
    USE SIGNAL ;
    PORT
      LAYER M5 ;
        RECT  91.2 30.156 91.224 30.24 ;
    END
  END xb[2]
  PIN xb[30]
    DIRECTION OUTPUT ;
    USE SIGNAL ;
    PORT
      LAYER M5 ;
        RECT  95.232 30.156 95.256 30.24 ;
    END
  END xb[30]
  PIN xb[31]
    DIRECTION OUTPUT ;
    USE SIGNAL ;
    PORT
      LAYER M5 ;
        RECT  95.376 30.156 95.4 30.24 ;
    END
  END xb[31]
  PIN xb[32]
    DIRECTION OUTPUT ;
    USE SIGNAL ;
    PORT
      LAYER M5 ;
        RECT  95.52 30.156 95.544 30.24 ;
    END
  END xb[32]
  PIN xb[33]
    DIRECTION OUTPUT ;
    USE SIGNAL ;
    PORT
      LAYER M5 ;
        RECT  95.664 30.156 95.688 30.24 ;
    END
  END xb[33]
  PIN xb[34]
    DIRECTION OUTPUT ;
    USE SIGNAL ;
    PORT
      LAYER M5 ;
        RECT  95.808 30.156 95.832 30.24 ;
    END
  END xb[34]
  PIN xb[35]
    DIRECTION OUTPUT ;
    USE SIGNAL ;
    PORT
      LAYER M5 ;
        RECT  95.952 30.156 95.976 30.24 ;
    END
  END xb[35]
  PIN xb[36]
    DIRECTION OUTPUT ;
    USE SIGNAL ;
    PORT
      LAYER M5 ;
        RECT  96.096 30.156 96.12 30.24 ;
    END
  END xb[36]
  PIN xb[37]
    DIRECTION OUTPUT ;
    USE SIGNAL ;
    PORT
      LAYER M5 ;
        RECT  96.24 30.156 96.264 30.24 ;
    END
  END xb[37]
  PIN xb[38]
    DIRECTION OUTPUT ;
    USE SIGNAL ;
    PORT
      LAYER M5 ;
        RECT  96.384 30.156 96.408 30.24 ;
    END
  END xb[38]
  PIN xb[39]
    DIRECTION OUTPUT ;
    USE SIGNAL ;
    PORT
      LAYER M5 ;
        RECT  96.528 30.156 96.552 30.24 ;
    END
  END xb[39]
  PIN xb[3]
    DIRECTION OUTPUT ;
    USE SIGNAL ;
    PORT
      LAYER M5 ;
        RECT  91.344 30.156 91.368 30.24 ;
    END
  END xb[3]
  PIN xb[40]
    DIRECTION OUTPUT ;
    USE SIGNAL ;
    PORT
      LAYER M5 ;
        RECT  96.672 30.156 96.696 30.24 ;
    END
  END xb[40]
  PIN xb[41]
    DIRECTION OUTPUT ;
    USE SIGNAL ;
    PORT
      LAYER M5 ;
        RECT  96.816 30.156 96.84 30.24 ;
    END
  END xb[41]
  PIN xb[42]
    DIRECTION OUTPUT ;
    USE SIGNAL ;
    PORT
      LAYER M5 ;
        RECT  96.96 30.156 96.984 30.24 ;
    END
  END xb[42]
  PIN xb[43]
    DIRECTION OUTPUT ;
    USE SIGNAL ;
    PORT
      LAYER M5 ;
        RECT  97.104 30.156 97.128 30.24 ;
    END
  END xb[43]
  PIN xb[44]
    DIRECTION OUTPUT ;
    USE SIGNAL ;
    PORT
      LAYER M5 ;
        RECT  97.248 30.156 97.272 30.24 ;
    END
  END xb[44]
  PIN xb[45]
    DIRECTION OUTPUT ;
    USE SIGNAL ;
    PORT
      LAYER M5 ;
        RECT  97.392 30.156 97.416 30.24 ;
    END
  END xb[45]
  PIN xb[46]
    DIRECTION OUTPUT ;
    USE SIGNAL ;
    PORT
      LAYER M5 ;
        RECT  97.536 30.156 97.56 30.24 ;
    END
  END xb[46]
  PIN xb[47]
    DIRECTION OUTPUT ;
    USE SIGNAL ;
    PORT
      LAYER M5 ;
        RECT  97.68 30.156 97.704 30.24 ;
    END
  END xb[47]
  PIN xb[48]
    DIRECTION OUTPUT ;
    USE SIGNAL ;
    PORT
      LAYER M5 ;
        RECT  97.824 30.156 97.848 30.24 ;
    END
  END xb[48]
  PIN xb[49]
    DIRECTION OUTPUT ;
    USE SIGNAL ;
    PORT
      LAYER M5 ;
        RECT  97.968 30.156 97.992 30.24 ;
    END
  END xb[49]
  PIN xb[4]
    DIRECTION OUTPUT ;
    USE SIGNAL ;
    PORT
      LAYER M5 ;
        RECT  91.488 30.156 91.512 30.24 ;
    END
  END xb[4]
  PIN xb[50]
    DIRECTION OUTPUT ;
    USE SIGNAL ;
    PORT
      LAYER M5 ;
        RECT  98.112 30.156 98.136 30.24 ;
    END
  END xb[50]
  PIN xb[51]
    DIRECTION OUTPUT ;
    USE SIGNAL ;
    PORT
      LAYER M5 ;
        RECT  98.256 30.156 98.28 30.24 ;
    END
  END xb[51]
  PIN xb[52]
    DIRECTION OUTPUT ;
    USE SIGNAL ;
    PORT
      LAYER M5 ;
        RECT  98.4 30.156 98.424 30.24 ;
    END
  END xb[52]
  PIN xb[53]
    DIRECTION OUTPUT ;
    USE SIGNAL ;
    PORT
      LAYER M5 ;
        RECT  98.544 30.156 98.568 30.24 ;
    END
  END xb[53]
  PIN xb[54]
    DIRECTION OUTPUT ;
    USE SIGNAL ;
    PORT
      LAYER M5 ;
        RECT  98.688 30.156 98.712 30.24 ;
    END
  END xb[54]
  PIN xb[55]
    DIRECTION OUTPUT ;
    USE SIGNAL ;
    PORT
      LAYER M5 ;
        RECT  98.832 30.156 98.856 30.24 ;
    END
  END xb[55]
  PIN xb[56]
    DIRECTION OUTPUT ;
    USE SIGNAL ;
    PORT
      LAYER M5 ;
        RECT  98.976 30.156 99 30.24 ;
    END
  END xb[56]
  PIN xb[57]
    DIRECTION OUTPUT ;
    USE SIGNAL ;
    PORT
      LAYER M5 ;
        RECT  99.12 30.156 99.144 30.24 ;
    END
  END xb[57]
  PIN xb[58]
    DIRECTION OUTPUT ;
    USE SIGNAL ;
    PORT
      LAYER M5 ;
        RECT  99.264 30.156 99.288 30.24 ;
    END
  END xb[58]
  PIN xb[59]
    DIRECTION OUTPUT ;
    USE SIGNAL ;
    PORT
      LAYER M5 ;
        RECT  99.408 30.156 99.432 30.24 ;
    END
  END xb[59]
  PIN xb[5]
    DIRECTION OUTPUT ;
    USE SIGNAL ;
    PORT
      LAYER M5 ;
        RECT  91.632 30.156 91.656 30.24 ;
    END
  END xb[5]
  PIN xb[60]
    DIRECTION OUTPUT ;
    USE SIGNAL ;
    PORT
      LAYER M5 ;
        RECT  99.552 30.156 99.576 30.24 ;
    END
  END xb[60]
  PIN xb[61]
    DIRECTION OUTPUT ;
    USE SIGNAL ;
    PORT
      LAYER M5 ;
        RECT  99.696 30.156 99.72 30.24 ;
    END
  END xb[61]
  PIN xb[62]
    DIRECTION OUTPUT ;
    USE SIGNAL ;
    PORT
      LAYER M5 ;
        RECT  99.84 30.156 99.864 30.24 ;
    END
  END xb[62]
  PIN xb[63]
    DIRECTION OUTPUT ;
    USE SIGNAL ;
    PORT
      LAYER M5 ;
        RECT  99.984 30.156 100.008 30.24 ;
    END
  END xb[63]
  PIN xb[64]
    DIRECTION OUTPUT ;
    USE SIGNAL ;
    PORT
      LAYER M5 ;
        RECT  100.128 30.156 100.152 30.24 ;
    END
  END xb[64]
  PIN xb[65]
    DIRECTION OUTPUT ;
    USE SIGNAL ;
    PORT
      LAYER M5 ;
        RECT  100.272 30.156 100.296 30.24 ;
    END
  END xb[65]
  PIN xb[66]
    DIRECTION OUTPUT ;
    USE SIGNAL ;
    PORT
      LAYER M5 ;
        RECT  100.416 30.156 100.44 30.24 ;
    END
  END xb[66]
  PIN xb[67]
    DIRECTION OUTPUT ;
    USE SIGNAL ;
    PORT
      LAYER M5 ;
        RECT  100.56 30.156 100.584 30.24 ;
    END
  END xb[67]
  PIN xb[68]
    DIRECTION OUTPUT ;
    USE SIGNAL ;
    PORT
      LAYER M5 ;
        RECT  100.704 30.156 100.728 30.24 ;
    END
  END xb[68]
  PIN xb[69]
    DIRECTION OUTPUT ;
    USE SIGNAL ;
    PORT
      LAYER M5 ;
        RECT  100.848 30.156 100.872 30.24 ;
    END
  END xb[69]
  PIN xb[6]
    DIRECTION OUTPUT ;
    USE SIGNAL ;
    PORT
      LAYER M5 ;
        RECT  91.776 30.156 91.8 30.24 ;
    END
  END xb[6]
  PIN xb[70]
    DIRECTION OUTPUT ;
    USE SIGNAL ;
    PORT
      LAYER M5 ;
        RECT  100.992 30.156 101.016 30.24 ;
    END
  END xb[70]
  PIN xb[71]
    DIRECTION OUTPUT ;
    USE SIGNAL ;
    PORT
      LAYER M5 ;
        RECT  101.136 30.156 101.16 30.24 ;
    END
  END xb[71]
  PIN xb[72]
    DIRECTION OUTPUT ;
    USE SIGNAL ;
    PORT
      LAYER M5 ;
        RECT  101.28 30.156 101.304 30.24 ;
    END
  END xb[72]
  PIN xb[73]
    DIRECTION OUTPUT ;
    USE SIGNAL ;
    PORT
      LAYER M5 ;
        RECT  101.424 30.156 101.448 30.24 ;
    END
  END xb[73]
  PIN xb[74]
    DIRECTION OUTPUT ;
    USE SIGNAL ;
    PORT
      LAYER M5 ;
        RECT  101.568 30.156 101.592 30.24 ;
    END
  END xb[74]
  PIN xb[75]
    DIRECTION OUTPUT ;
    USE SIGNAL ;
    PORT
      LAYER M5 ;
        RECT  101.712 30.156 101.736 30.24 ;
    END
  END xb[75]
  PIN xb[76]
    DIRECTION OUTPUT ;
    USE SIGNAL ;
    PORT
      LAYER M5 ;
        RECT  101.856 30.156 101.88 30.24 ;
    END
  END xb[76]
  PIN xb[77]
    DIRECTION OUTPUT ;
    USE SIGNAL ;
    PORT
      LAYER M5 ;
        RECT  102 30.156 102.024 30.24 ;
    END
  END xb[77]
  PIN xb[78]
    DIRECTION OUTPUT ;
    USE SIGNAL ;
    PORT
      LAYER M5 ;
        RECT  102.144 30.156 102.168 30.24 ;
    END
  END xb[78]
  PIN xb[79]
    DIRECTION OUTPUT ;
    USE SIGNAL ;
    PORT
      LAYER M5 ;
        RECT  102.288 30.156 102.312 30.24 ;
    END
  END xb[79]
  PIN xb[7]
    DIRECTION OUTPUT ;
    USE SIGNAL ;
    PORT
      LAYER M5 ;
        RECT  91.92 30.156 91.944 30.24 ;
    END
  END xb[7]
  PIN xb[80]
    DIRECTION OUTPUT ;
    USE SIGNAL ;
    PORT
      LAYER M5 ;
        RECT  102.432 30.156 102.456 30.24 ;
    END
  END xb[80]
  PIN xb[81]
    DIRECTION OUTPUT ;
    USE SIGNAL ;
    PORT
      LAYER M5 ;
        RECT  102.576 30.156 102.6 30.24 ;
    END
  END xb[81]
  PIN xb[82]
    DIRECTION OUTPUT ;
    USE SIGNAL ;
    PORT
      LAYER M5 ;
        RECT  102.72 30.156 102.744 30.24 ;
    END
  END xb[82]
  PIN xb[83]
    DIRECTION OUTPUT ;
    USE SIGNAL ;
    PORT
      LAYER M5 ;
        RECT  102.864 30.156 102.888 30.24 ;
    END
  END xb[83]
  PIN xb[84]
    DIRECTION OUTPUT ;
    USE SIGNAL ;
    PORT
      LAYER M5 ;
        RECT  103.008 30.156 103.032 30.24 ;
    END
  END xb[84]
  PIN xb[85]
    DIRECTION OUTPUT ;
    USE SIGNAL ;
    PORT
      LAYER M5 ;
        RECT  103.152 30.156 103.176 30.24 ;
    END
  END xb[85]
  PIN xb[86]
    DIRECTION OUTPUT ;
    USE SIGNAL ;
    PORT
      LAYER M5 ;
        RECT  103.296 30.156 103.32 30.24 ;
    END
  END xb[86]
  PIN xb[87]
    DIRECTION OUTPUT ;
    USE SIGNAL ;
    PORT
      LAYER M5 ;
        RECT  103.44 30.156 103.464 30.24 ;
    END
  END xb[87]
  PIN xb[88]
    DIRECTION OUTPUT ;
    USE SIGNAL ;
    PORT
      LAYER M5 ;
        RECT  103.584 30.156 103.608 30.24 ;
    END
  END xb[88]
  PIN xb[89]
    DIRECTION OUTPUT ;
    USE SIGNAL ;
    PORT
      LAYER M5 ;
        RECT  103.728 30.156 103.752 30.24 ;
    END
  END xb[89]
  PIN xb[8]
    DIRECTION OUTPUT ;
    USE SIGNAL ;
    PORT
      LAYER M5 ;
        RECT  92.064 30.156 92.088 30.24 ;
    END
  END xb[8]
  PIN xb[90]
    DIRECTION OUTPUT ;
    USE SIGNAL ;
    PORT
      LAYER M5 ;
        RECT  103.872 30.156 103.896 30.24 ;
    END
  END xb[90]
  PIN xb[91]
    DIRECTION OUTPUT ;
    USE SIGNAL ;
    PORT
      LAYER M5 ;
        RECT  104.016 30.156 104.04 30.24 ;
    END
  END xb[91]
  PIN xb[92]
    DIRECTION OUTPUT ;
    USE SIGNAL ;
    PORT
      LAYER M5 ;
        RECT  104.16 30.156 104.184 30.24 ;
    END
  END xb[92]
  PIN xb[93]
    DIRECTION OUTPUT ;
    USE SIGNAL ;
    PORT
      LAYER M5 ;
        RECT  104.304 30.156 104.328 30.24 ;
    END
  END xb[93]
  PIN xb[94]
    DIRECTION OUTPUT ;
    USE SIGNAL ;
    PORT
      LAYER M5 ;
        RECT  104.448 30.156 104.472 30.24 ;
    END
  END xb[94]
  PIN xb[95]
    DIRECTION OUTPUT ;
    USE SIGNAL ;
    PORT
      LAYER M5 ;
        RECT  104.592 30.156 104.616 30.24 ;
    END
  END xb[95]
  PIN xb[96]
    DIRECTION OUTPUT ;
    USE SIGNAL ;
    PORT
      LAYER M5 ;
        RECT  104.736 30.156 104.76 30.24 ;
    END
  END xb[96]
  PIN xb[97]
    DIRECTION OUTPUT ;
    USE SIGNAL ;
    PORT
      LAYER M5 ;
        RECT  104.88 30.156 104.904 30.24 ;
    END
  END xb[97]
  PIN xb[98]
    DIRECTION OUTPUT ;
    USE SIGNAL ;
    PORT
      LAYER M5 ;
        RECT  105.024 30.156 105.048 30.24 ;
    END
  END xb[98]
  PIN xb[99]
    DIRECTION OUTPUT ;
    USE SIGNAL ;
    PORT
      LAYER M5 ;
        RECT  105.168 30.156 105.192 30.24 ;
    END
  END xb[99]
  PIN xb[9]
    DIRECTION OUTPUT ;
    USE SIGNAL ;
    PORT
      LAYER M5 ;
        RECT  92.208 30.156 92.232 30.24 ;
    END
  END xb[9]
  PIN xbi[0]
    DIRECTION INPUT ;
    USE SIGNAL ;
    PORT
      LAYER M5 ;
        RECT  92.16 0 92.184 0.084 ;
    END
  END xbi[0]
  PIN xbi[100]
    DIRECTION INPUT ;
    USE SIGNAL ;
    PORT
      LAYER M5 ;
        RECT  106.56 0 106.584 0.084 ;
    END
  END xbi[100]
  PIN xbi[101]
    DIRECTION INPUT ;
    USE SIGNAL ;
    PORT
      LAYER M5 ;
        RECT  106.704 0 106.728 0.084 ;
    END
  END xbi[101]
  PIN xbi[102]
    DIRECTION INPUT ;
    USE SIGNAL ;
    PORT
      LAYER M5 ;
        RECT  106.848 0 106.872 0.084 ;
    END
  END xbi[102]
  PIN xbi[103]
    DIRECTION INPUT ;
    USE SIGNAL ;
    PORT
      LAYER M5 ;
        RECT  106.992 0 107.016 0.084 ;
    END
  END xbi[103]
  PIN xbi[104]
    DIRECTION INPUT ;
    USE SIGNAL ;
    PORT
      LAYER M5 ;
        RECT  107.136 0 107.16 0.084 ;
    END
  END xbi[104]
  PIN xbi[105]
    DIRECTION INPUT ;
    USE SIGNAL ;
    PORT
      LAYER M5 ;
        RECT  107.28 0 107.304 0.084 ;
    END
  END xbi[105]
  PIN xbi[106]
    DIRECTION INPUT ;
    USE SIGNAL ;
    PORT
      LAYER M5 ;
        RECT  107.424 0 107.448 0.084 ;
    END
  END xbi[106]
  PIN xbi[107]
    DIRECTION INPUT ;
    USE SIGNAL ;
    PORT
      LAYER M5 ;
        RECT  107.568 0 107.592 0.084 ;
    END
  END xbi[107]
  PIN xbi[108]
    DIRECTION INPUT ;
    USE SIGNAL ;
    PORT
      LAYER M5 ;
        RECT  107.712 0 107.736 0.084 ;
    END
  END xbi[108]
  PIN xbi[109]
    DIRECTION INPUT ;
    USE SIGNAL ;
    PORT
      LAYER M5 ;
        RECT  107.856 0 107.88 0.084 ;
    END
  END xbi[109]
  PIN xbi[10]
    DIRECTION INPUT ;
    USE SIGNAL ;
    PORT
      LAYER M5 ;
        RECT  93.6 0 93.624 0.084 ;
    END
  END xbi[10]
  PIN xbi[110]
    DIRECTION INPUT ;
    USE SIGNAL ;
    PORT
      LAYER M5 ;
        RECT  108 0 108.024 0.084 ;
    END
  END xbi[110]
  PIN xbi[111]
    DIRECTION INPUT ;
    USE SIGNAL ;
    PORT
      LAYER M5 ;
        RECT  108.144 0 108.168 0.084 ;
    END
  END xbi[111]
  PIN xbi[112]
    DIRECTION INPUT ;
    USE SIGNAL ;
    PORT
      LAYER M5 ;
        RECT  108.288 0 108.312 0.084 ;
    END
  END xbi[112]
  PIN xbi[113]
    DIRECTION INPUT ;
    USE SIGNAL ;
    PORT
      LAYER M5 ;
        RECT  108.432 0 108.456 0.084 ;
    END
  END xbi[113]
  PIN xbi[114]
    DIRECTION INPUT ;
    USE SIGNAL ;
    PORT
      LAYER M5 ;
        RECT  108.576 0 108.6 0.084 ;
    END
  END xbi[114]
  PIN xbi[115]
    DIRECTION INPUT ;
    USE SIGNAL ;
    PORT
      LAYER M5 ;
        RECT  108.72 0 108.744 0.084 ;
    END
  END xbi[115]
  PIN xbi[116]
    DIRECTION INPUT ;
    USE SIGNAL ;
    PORT
      LAYER M5 ;
        RECT  108.864 0 108.888 0.084 ;
    END
  END xbi[116]
  PIN xbi[117]
    DIRECTION INPUT ;
    USE SIGNAL ;
    PORT
      LAYER M5 ;
        RECT  109.008 0 109.032 0.084 ;
    END
  END xbi[117]
  PIN xbi[118]
    DIRECTION INPUT ;
    USE SIGNAL ;
    PORT
      LAYER M5 ;
        RECT  109.152 0 109.176 0.084 ;
    END
  END xbi[118]
  PIN xbi[119]
    DIRECTION INPUT ;
    USE SIGNAL ;
    PORT
      LAYER M5 ;
        RECT  109.296 0 109.32 0.084 ;
    END
  END xbi[119]
  PIN xbi[11]
    DIRECTION INPUT ;
    USE SIGNAL ;
    PORT
      LAYER M5 ;
        RECT  93.744 0 93.768 0.084 ;
    END
  END xbi[11]
  PIN xbi[120]
    DIRECTION INPUT ;
    USE SIGNAL ;
    PORT
      LAYER M5 ;
        RECT  109.44 0 109.464 0.084 ;
    END
  END xbi[120]
  PIN xbi[121]
    DIRECTION INPUT ;
    USE SIGNAL ;
    PORT
      LAYER M5 ;
        RECT  109.584 0 109.608 0.084 ;
    END
  END xbi[121]
  PIN xbi[122]
    DIRECTION INPUT ;
    USE SIGNAL ;
    PORT
      LAYER M5 ;
        RECT  109.728 0 109.752 0.084 ;
    END
  END xbi[122]
  PIN xbi[123]
    DIRECTION INPUT ;
    USE SIGNAL ;
    PORT
      LAYER M5 ;
        RECT  109.872 0 109.896 0.084 ;
    END
  END xbi[123]
  PIN xbi[124]
    DIRECTION INPUT ;
    USE SIGNAL ;
    PORT
      LAYER M5 ;
        RECT  110.016 0 110.04 0.084 ;
    END
  END xbi[124]
  PIN xbi[125]
    DIRECTION INPUT ;
    USE SIGNAL ;
    PORT
      LAYER M5 ;
        RECT  110.16 0 110.184 0.084 ;
    END
  END xbi[125]
  PIN xbi[126]
    DIRECTION INPUT ;
    USE SIGNAL ;
    PORT
      LAYER M5 ;
        RECT  110.304 0 110.328 0.084 ;
    END
  END xbi[126]
  PIN xbi[127]
    DIRECTION INPUT ;
    USE SIGNAL ;
    PORT
      LAYER M5 ;
        RECT  110.448 0 110.472 0.084 ;
    END
  END xbi[127]
  PIN xbi[128]
    DIRECTION INPUT ;
    USE SIGNAL ;
    PORT
      LAYER M5 ;
        RECT  110.592 0 110.616 0.084 ;
    END
  END xbi[128]
  PIN xbi[129]
    DIRECTION INPUT ;
    USE SIGNAL ;
    PORT
      LAYER M5 ;
        RECT  110.736 0 110.76 0.084 ;
    END
  END xbi[129]
  PIN xbi[12]
    DIRECTION INPUT ;
    USE SIGNAL ;
    PORT
      LAYER M5 ;
        RECT  93.888 0 93.912 0.084 ;
    END
  END xbi[12]
  PIN xbi[130]
    DIRECTION INPUT ;
    USE SIGNAL ;
    PORT
      LAYER M5 ;
        RECT  110.88 0 110.904 0.084 ;
    END
  END xbi[130]
  PIN xbi[131]
    DIRECTION INPUT ;
    USE SIGNAL ;
    PORT
      LAYER M5 ;
        RECT  111.024 0 111.048 0.084 ;
    END
  END xbi[131]
  PIN xbi[132]
    DIRECTION INPUT ;
    USE SIGNAL ;
    PORT
      LAYER M5 ;
        RECT  111.168 0 111.192 0.084 ;
    END
  END xbi[132]
  PIN xbi[133]
    DIRECTION INPUT ;
    USE SIGNAL ;
    PORT
      LAYER M5 ;
        RECT  111.312 0 111.336 0.084 ;
    END
  END xbi[133]
  PIN xbi[134]
    DIRECTION INPUT ;
    USE SIGNAL ;
    PORT
      LAYER M5 ;
        RECT  111.456 0 111.48 0.084 ;
    END
  END xbi[134]
  PIN xbi[135]
    DIRECTION INPUT ;
    USE SIGNAL ;
    PORT
      LAYER M5 ;
        RECT  111.6 0 111.624 0.084 ;
    END
  END xbi[135]
  PIN xbi[136]
    DIRECTION INPUT ;
    USE SIGNAL ;
    PORT
      LAYER M5 ;
        RECT  111.744 0 111.768 0.084 ;
    END
  END xbi[136]
  PIN xbi[137]
    DIRECTION INPUT ;
    USE SIGNAL ;
    PORT
      LAYER M5 ;
        RECT  111.888 0 111.912 0.084 ;
    END
  END xbi[137]
  PIN xbi[138]
    DIRECTION INPUT ;
    USE SIGNAL ;
    PORT
      LAYER M5 ;
        RECT  112.032 0 112.056 0.084 ;
    END
  END xbi[138]
  PIN xbi[139]
    DIRECTION INPUT ;
    USE SIGNAL ;
    PORT
      LAYER M5 ;
        RECT  112.176 0 112.2 0.084 ;
    END
  END xbi[139]
  PIN xbi[13]
    DIRECTION INPUT ;
    USE SIGNAL ;
    PORT
      LAYER M5 ;
        RECT  94.032 0 94.056 0.084 ;
    END
  END xbi[13]
  PIN xbi[140]
    DIRECTION INPUT ;
    USE SIGNAL ;
    PORT
      LAYER M5 ;
        RECT  112.32 0 112.344 0.084 ;
    END
  END xbi[140]
  PIN xbi[141]
    DIRECTION INPUT ;
    USE SIGNAL ;
    PORT
      LAYER M5 ;
        RECT  112.464 0 112.488 0.084 ;
    END
  END xbi[141]
  PIN xbi[142]
    DIRECTION INPUT ;
    USE SIGNAL ;
    PORT
      LAYER M5 ;
        RECT  112.608 0 112.632 0.084 ;
    END
  END xbi[142]
  PIN xbi[143]
    DIRECTION INPUT ;
    USE SIGNAL ;
    PORT
      LAYER M5 ;
        RECT  112.752 0 112.776 0.084 ;
    END
  END xbi[143]
  PIN xbi[144]
    DIRECTION INPUT ;
    USE SIGNAL ;
    PORT
      LAYER M5 ;
        RECT  112.896 0 112.92 0.084 ;
    END
  END xbi[144]
  PIN xbi[145]
    DIRECTION INPUT ;
    USE SIGNAL ;
    PORT
      LAYER M5 ;
        RECT  113.04 0 113.064 0.084 ;
    END
  END xbi[145]
  PIN xbi[146]
    DIRECTION INPUT ;
    USE SIGNAL ;
    PORT
      LAYER M5 ;
        RECT  113.184 0 113.208 0.084 ;
    END
  END xbi[146]
  PIN xbi[147]
    DIRECTION INPUT ;
    USE SIGNAL ;
    PORT
      LAYER M5 ;
        RECT  113.328 0 113.352 0.084 ;
    END
  END xbi[147]
  PIN xbi[148]
    DIRECTION INPUT ;
    USE SIGNAL ;
    PORT
      LAYER M5 ;
        RECT  113.472 0 113.496 0.084 ;
    END
  END xbi[148]
  PIN xbi[149]
    DIRECTION INPUT ;
    USE SIGNAL ;
    PORT
      LAYER M5 ;
        RECT  113.616 0 113.64 0.084 ;
    END
  END xbi[149]
  PIN xbi[14]
    DIRECTION INPUT ;
    USE SIGNAL ;
    PORT
      LAYER M5 ;
        RECT  94.176 0 94.2 0.084 ;
    END
  END xbi[14]
  PIN xbi[150]
    DIRECTION INPUT ;
    USE SIGNAL ;
    PORT
      LAYER M5 ;
        RECT  113.76 0 113.784 0.084 ;
    END
  END xbi[150]
  PIN xbi[151]
    DIRECTION INPUT ;
    USE SIGNAL ;
    PORT
      LAYER M5 ;
        RECT  113.904 0 113.928 0.084 ;
    END
  END xbi[151]
  PIN xbi[152]
    DIRECTION INPUT ;
    USE SIGNAL ;
    PORT
      LAYER M5 ;
        RECT  114.048 0 114.072 0.084 ;
    END
  END xbi[152]
  PIN xbi[153]
    DIRECTION INPUT ;
    USE SIGNAL ;
    PORT
      LAYER M5 ;
        RECT  114.192 0 114.216 0.084 ;
    END
  END xbi[153]
  PIN xbi[154]
    DIRECTION INPUT ;
    USE SIGNAL ;
    PORT
      LAYER M5 ;
        RECT  114.336 0 114.36 0.084 ;
    END
  END xbi[154]
  PIN xbi[155]
    DIRECTION INPUT ;
    USE SIGNAL ;
    PORT
      LAYER M5 ;
        RECT  114.48 0 114.504 0.084 ;
    END
  END xbi[155]
  PIN xbi[156]
    DIRECTION INPUT ;
    USE SIGNAL ;
    PORT
      LAYER M5 ;
        RECT  114.624 0 114.648 0.084 ;
    END
  END xbi[156]
  PIN xbi[157]
    DIRECTION INPUT ;
    USE SIGNAL ;
    PORT
      LAYER M5 ;
        RECT  114.768 0 114.792 0.084 ;
    END
  END xbi[157]
  PIN xbi[158]
    DIRECTION INPUT ;
    USE SIGNAL ;
    PORT
      LAYER M5 ;
        RECT  114.912 0 114.936 0.084 ;
    END
  END xbi[158]
  PIN xbi[159]
    DIRECTION INPUT ;
    USE SIGNAL ;
    PORT
      LAYER M5 ;
        RECT  115.056 0 115.08 0.084 ;
    END
  END xbi[159]
  PIN xbi[15]
    DIRECTION INPUT ;
    USE SIGNAL ;
    PORT
      LAYER M5 ;
        RECT  94.32 0 94.344 0.084 ;
    END
  END xbi[15]
  PIN xbi[160]
    DIRECTION INPUT ;
    USE SIGNAL ;
    PORT
      LAYER M5 ;
        RECT  115.2 0 115.224 0.084 ;
    END
  END xbi[160]
  PIN xbi[161]
    DIRECTION INPUT ;
    USE SIGNAL ;
    PORT
      LAYER M5 ;
        RECT  115.344 0 115.368 0.084 ;
    END
  END xbi[161]
  PIN xbi[162]
    DIRECTION INPUT ;
    USE SIGNAL ;
    PORT
      LAYER M5 ;
        RECT  115.488 0 115.512 0.084 ;
    END
  END xbi[162]
  PIN xbi[163]
    DIRECTION INPUT ;
    USE SIGNAL ;
    PORT
      LAYER M5 ;
        RECT  115.632 0 115.656 0.084 ;
    END
  END xbi[163]
  PIN xbi[164]
    DIRECTION INPUT ;
    USE SIGNAL ;
    PORT
      LAYER M5 ;
        RECT  115.776 0 115.8 0.084 ;
    END
  END xbi[164]
  PIN xbi[165]
    DIRECTION INPUT ;
    USE SIGNAL ;
    PORT
      LAYER M5 ;
        RECT  115.92 0 115.944 0.084 ;
    END
  END xbi[165]
  PIN xbi[166]
    DIRECTION INPUT ;
    USE SIGNAL ;
    PORT
      LAYER M5 ;
        RECT  116.064 0 116.088 0.084 ;
    END
  END xbi[166]
  PIN xbi[167]
    DIRECTION INPUT ;
    USE SIGNAL ;
    PORT
      LAYER M5 ;
        RECT  116.208 0 116.232 0.084 ;
    END
  END xbi[167]
  PIN xbi[168]
    DIRECTION INPUT ;
    USE SIGNAL ;
    PORT
      LAYER M5 ;
        RECT  116.352 0 116.376 0.084 ;
    END
  END xbi[168]
  PIN xbi[169]
    DIRECTION INPUT ;
    USE SIGNAL ;
    PORT
      LAYER M5 ;
        RECT  116.496 0 116.52 0.084 ;
    END
  END xbi[169]
  PIN xbi[16]
    DIRECTION INPUT ;
    USE SIGNAL ;
    PORT
      LAYER M5 ;
        RECT  94.464 0 94.488 0.084 ;
    END
  END xbi[16]
  PIN xbi[170]
    DIRECTION INPUT ;
    USE SIGNAL ;
    PORT
      LAYER M5 ;
        RECT  116.64 0 116.664 0.084 ;
    END
  END xbi[170]
  PIN xbi[171]
    DIRECTION INPUT ;
    USE SIGNAL ;
    PORT
      LAYER M5 ;
        RECT  116.784 0 116.808 0.084 ;
    END
  END xbi[171]
  PIN xbi[172]
    DIRECTION INPUT ;
    USE SIGNAL ;
    PORT
      LAYER M5 ;
        RECT  116.928 0 116.952 0.084 ;
    END
  END xbi[172]
  PIN xbi[173]
    DIRECTION INPUT ;
    USE SIGNAL ;
    PORT
      LAYER M5 ;
        RECT  117.072 0 117.096 0.084 ;
    END
  END xbi[173]
  PIN xbi[174]
    DIRECTION INPUT ;
    USE SIGNAL ;
    PORT
      LAYER M5 ;
        RECT  117.216 0 117.24 0.084 ;
    END
  END xbi[174]
  PIN xbi[175]
    DIRECTION INPUT ;
    USE SIGNAL ;
    PORT
      LAYER M5 ;
        RECT  117.36 0 117.384 0.084 ;
    END
  END xbi[175]
  PIN xbi[176]
    DIRECTION INPUT ;
    USE SIGNAL ;
    PORT
      LAYER M5 ;
        RECT  117.504 0 117.528 0.084 ;
    END
  END xbi[176]
  PIN xbi[177]
    DIRECTION INPUT ;
    USE SIGNAL ;
    PORT
      LAYER M5 ;
        RECT  117.648 0 117.672 0.084 ;
    END
  END xbi[177]
  PIN xbi[178]
    DIRECTION INPUT ;
    USE SIGNAL ;
    PORT
      LAYER M5 ;
        RECT  117.792 0 117.816 0.084 ;
    END
  END xbi[178]
  PIN xbi[179]
    DIRECTION INPUT ;
    USE SIGNAL ;
    PORT
      LAYER M5 ;
        RECT  117.936 0 117.96 0.084 ;
    END
  END xbi[179]
  PIN xbi[17]
    DIRECTION INPUT ;
    USE SIGNAL ;
    PORT
      LAYER M5 ;
        RECT  94.608 0 94.632 0.084 ;
    END
  END xbi[17]
  PIN xbi[180]
    DIRECTION INPUT ;
    USE SIGNAL ;
    PORT
      LAYER M5 ;
        RECT  118.08 0 118.104 0.084 ;
    END
  END xbi[180]
  PIN xbi[181]
    DIRECTION INPUT ;
    USE SIGNAL ;
    PORT
      LAYER M5 ;
        RECT  118.224 0 118.248 0.084 ;
    END
  END xbi[181]
  PIN xbi[182]
    DIRECTION INPUT ;
    USE SIGNAL ;
    PORT
      LAYER M5 ;
        RECT  118.368 0 118.392 0.084 ;
    END
  END xbi[182]
  PIN xbi[183]
    DIRECTION INPUT ;
    USE SIGNAL ;
    PORT
      LAYER M5 ;
        RECT  118.512 0 118.536 0.084 ;
    END
  END xbi[183]
  PIN xbi[184]
    DIRECTION INPUT ;
    USE SIGNAL ;
    PORT
      LAYER M5 ;
        RECT  118.656 0 118.68 0.084 ;
    END
  END xbi[184]
  PIN xbi[185]
    DIRECTION INPUT ;
    USE SIGNAL ;
    PORT
      LAYER M5 ;
        RECT  118.8 0 118.824 0.084 ;
    END
  END xbi[185]
  PIN xbi[186]
    DIRECTION INPUT ;
    USE SIGNAL ;
    PORT
      LAYER M5 ;
        RECT  118.944 0 118.968 0.084 ;
    END
  END xbi[186]
  PIN xbi[187]
    DIRECTION INPUT ;
    USE SIGNAL ;
    PORT
      LAYER M5 ;
        RECT  119.088 0 119.112 0.084 ;
    END
  END xbi[187]
  PIN xbi[188]
    DIRECTION INPUT ;
    USE SIGNAL ;
    PORT
      LAYER M5 ;
        RECT  119.232 0 119.256 0.084 ;
    END
  END xbi[188]
  PIN xbi[189]
    DIRECTION INPUT ;
    USE SIGNAL ;
    PORT
      LAYER M5 ;
        RECT  119.376 0 119.4 0.084 ;
    END
  END xbi[189]
  PIN xbi[18]
    DIRECTION INPUT ;
    USE SIGNAL ;
    PORT
      LAYER M5 ;
        RECT  94.752 0 94.776 0.084 ;
    END
  END xbi[18]
  PIN xbi[190]
    DIRECTION INPUT ;
    USE SIGNAL ;
    PORT
      LAYER M5 ;
        RECT  119.52 0 119.544 0.084 ;
    END
  END xbi[190]
  PIN xbi[191]
    DIRECTION INPUT ;
    USE SIGNAL ;
    PORT
      LAYER M5 ;
        RECT  119.664 0 119.688 0.084 ;
    END
  END xbi[191]
  PIN xbi[192]
    DIRECTION INPUT ;
    USE SIGNAL ;
    PORT
      LAYER M5 ;
        RECT  119.808 0 119.832 0.084 ;
    END
  END xbi[192]
  PIN xbi[193]
    DIRECTION INPUT ;
    USE SIGNAL ;
    PORT
      LAYER M5 ;
        RECT  119.952 0 119.976 0.084 ;
    END
  END xbi[193]
  PIN xbi[194]
    DIRECTION INPUT ;
    USE SIGNAL ;
    PORT
      LAYER M5 ;
        RECT  120.096 0 120.12 0.084 ;
    END
  END xbi[194]
  PIN xbi[195]
    DIRECTION INPUT ;
    USE SIGNAL ;
    PORT
      LAYER M5 ;
        RECT  120.24 0 120.264 0.084 ;
    END
  END xbi[195]
  PIN xbi[196]
    DIRECTION INPUT ;
    USE SIGNAL ;
    PORT
      LAYER M5 ;
        RECT  120.384 0 120.408 0.084 ;
    END
  END xbi[196]
  PIN xbi[197]
    DIRECTION INPUT ;
    USE SIGNAL ;
    PORT
      LAYER M5 ;
        RECT  120.528 0 120.552 0.084 ;
    END
  END xbi[197]
  PIN xbi[198]
    DIRECTION INPUT ;
    USE SIGNAL ;
    PORT
      LAYER M5 ;
        RECT  120.672 0 120.696 0.084 ;
    END
  END xbi[198]
  PIN xbi[199]
    DIRECTION INPUT ;
    USE SIGNAL ;
    PORT
      LAYER M5 ;
        RECT  120.816 0 120.84 0.084 ;
    END
  END xbi[199]
  PIN xbi[19]
    DIRECTION INPUT ;
    USE SIGNAL ;
    PORT
      LAYER M5 ;
        RECT  94.896 0 94.92 0.084 ;
    END
  END xbi[19]
  PIN xbi[1]
    DIRECTION INPUT ;
    USE SIGNAL ;
    PORT
      LAYER M5 ;
        RECT  92.304 0 92.328 0.084 ;
    END
  END xbi[1]
  PIN xbi[200]
    DIRECTION INPUT ;
    USE SIGNAL ;
    PORT
      LAYER M5 ;
        RECT  120.96 0 120.984 0.084 ;
    END
  END xbi[200]
  PIN xbi[201]
    DIRECTION INPUT ;
    USE SIGNAL ;
    PORT
      LAYER M5 ;
        RECT  121.104 0 121.128 0.084 ;
    END
  END xbi[201]
  PIN xbi[202]
    DIRECTION INPUT ;
    USE SIGNAL ;
    PORT
      LAYER M5 ;
        RECT  121.248 0 121.272 0.084 ;
    END
  END xbi[202]
  PIN xbi[203]
    DIRECTION INPUT ;
    USE SIGNAL ;
    PORT
      LAYER M5 ;
        RECT  121.392 0 121.416 0.084 ;
    END
  END xbi[203]
  PIN xbi[204]
    DIRECTION INPUT ;
    USE SIGNAL ;
    PORT
      LAYER M5 ;
        RECT  121.536 0 121.56 0.084 ;
    END
  END xbi[204]
  PIN xbi[205]
    DIRECTION INPUT ;
    USE SIGNAL ;
    PORT
      LAYER M5 ;
        RECT  121.68 0 121.704 0.084 ;
    END
  END xbi[205]
  PIN xbi[206]
    DIRECTION INPUT ;
    USE SIGNAL ;
    PORT
      LAYER M5 ;
        RECT  121.824 0 121.848 0.084 ;
    END
  END xbi[206]
  PIN xbi[207]
    DIRECTION INPUT ;
    USE SIGNAL ;
    PORT
      LAYER M5 ;
        RECT  121.968 0 121.992 0.084 ;
    END
  END xbi[207]
  PIN xbi[208]
    DIRECTION INPUT ;
    USE SIGNAL ;
    PORT
      LAYER M5 ;
        RECT  122.112 0 122.136 0.084 ;
    END
  END xbi[208]
  PIN xbi[209]
    DIRECTION INPUT ;
    USE SIGNAL ;
    PORT
      LAYER M5 ;
        RECT  122.256 0 122.28 0.084 ;
    END
  END xbi[209]
  PIN xbi[20]
    DIRECTION INPUT ;
    USE SIGNAL ;
    PORT
      LAYER M5 ;
        RECT  95.04 0 95.064 0.084 ;
    END
  END xbi[20]
  PIN xbi[210]
    DIRECTION INPUT ;
    USE SIGNAL ;
    PORT
      LAYER M5 ;
        RECT  122.4 0 122.424 0.084 ;
    END
  END xbi[210]
  PIN xbi[211]
    DIRECTION INPUT ;
    USE SIGNAL ;
    PORT
      LAYER M5 ;
        RECT  122.544 0 122.568 0.084 ;
    END
  END xbi[211]
  PIN xbi[212]
    DIRECTION INPUT ;
    USE SIGNAL ;
    PORT
      LAYER M5 ;
        RECT  122.688 0 122.712 0.084 ;
    END
  END xbi[212]
  PIN xbi[213]
    DIRECTION INPUT ;
    USE SIGNAL ;
    PORT
      LAYER M5 ;
        RECT  122.832 0 122.856 0.084 ;
    END
  END xbi[213]
  PIN xbi[214]
    DIRECTION INPUT ;
    USE SIGNAL ;
    PORT
      LAYER M5 ;
        RECT  122.976 0 123 0.084 ;
    END
  END xbi[214]
  PIN xbi[215]
    DIRECTION INPUT ;
    USE SIGNAL ;
    PORT
      LAYER M5 ;
        RECT  123.12 0 123.144 0.084 ;
    END
  END xbi[215]
  PIN xbi[216]
    DIRECTION INPUT ;
    USE SIGNAL ;
    PORT
      LAYER M5 ;
        RECT  123.264 0 123.288 0.084 ;
    END
  END xbi[216]
  PIN xbi[217]
    DIRECTION INPUT ;
    USE SIGNAL ;
    PORT
      LAYER M5 ;
        RECT  123.408 0 123.432 0.084 ;
    END
  END xbi[217]
  PIN xbi[218]
    DIRECTION INPUT ;
    USE SIGNAL ;
    PORT
      LAYER M5 ;
        RECT  123.552 0 123.576 0.084 ;
    END
  END xbi[218]
  PIN xbi[219]
    DIRECTION INPUT ;
    USE SIGNAL ;
    PORT
      LAYER M5 ;
        RECT  123.696 0 123.72 0.084 ;
    END
  END xbi[219]
  PIN xbi[21]
    DIRECTION INPUT ;
    USE SIGNAL ;
    PORT
      LAYER M5 ;
        RECT  95.184 0 95.208 0.084 ;
    END
  END xbi[21]
  PIN xbi[220]
    DIRECTION INPUT ;
    USE SIGNAL ;
    PORT
      LAYER M5 ;
        RECT  123.84 0 123.864 0.084 ;
    END
  END xbi[220]
  PIN xbi[221]
    DIRECTION INPUT ;
    USE SIGNAL ;
    PORT
      LAYER M5 ;
        RECT  123.984 0 124.008 0.084 ;
    END
  END xbi[221]
  PIN xbi[222]
    DIRECTION INPUT ;
    USE SIGNAL ;
    PORT
      LAYER M5 ;
        RECT  124.128 0 124.152 0.084 ;
    END
  END xbi[222]
  PIN xbi[223]
    DIRECTION INPUT ;
    USE SIGNAL ;
    PORT
      LAYER M5 ;
        RECT  124.272 0 124.296 0.084 ;
    END
  END xbi[223]
  PIN xbi[224]
    DIRECTION INPUT ;
    USE SIGNAL ;
    PORT
      LAYER M5 ;
        RECT  124.416 0 124.44 0.084 ;
    END
  END xbi[224]
  PIN xbi[225]
    DIRECTION INPUT ;
    USE SIGNAL ;
    PORT
      LAYER M5 ;
        RECT  124.56 0 124.584 0.084 ;
    END
  END xbi[225]
  PIN xbi[226]
    DIRECTION INPUT ;
    USE SIGNAL ;
    PORT
      LAYER M5 ;
        RECT  124.704 0 124.728 0.084 ;
    END
  END xbi[226]
  PIN xbi[227]
    DIRECTION INPUT ;
    USE SIGNAL ;
    PORT
      LAYER M5 ;
        RECT  124.848 0 124.872 0.084 ;
    END
  END xbi[227]
  PIN xbi[228]
    DIRECTION INPUT ;
    USE SIGNAL ;
    PORT
      LAYER M5 ;
        RECT  124.992 0 125.016 0.084 ;
    END
  END xbi[228]
  PIN xbi[229]
    DIRECTION INPUT ;
    USE SIGNAL ;
    PORT
      LAYER M5 ;
        RECT  125.136 0 125.16 0.084 ;
    END
  END xbi[229]
  PIN xbi[22]
    DIRECTION INPUT ;
    USE SIGNAL ;
    PORT
      LAYER M5 ;
        RECT  95.328 0 95.352 0.084 ;
    END
  END xbi[22]
  PIN xbi[230]
    DIRECTION INPUT ;
    USE SIGNAL ;
    PORT
      LAYER M5 ;
        RECT  125.28 0 125.304 0.084 ;
    END
  END xbi[230]
  PIN xbi[231]
    DIRECTION INPUT ;
    USE SIGNAL ;
    PORT
      LAYER M5 ;
        RECT  125.424 0 125.448 0.084 ;
    END
  END xbi[231]
  PIN xbi[232]
    DIRECTION INPUT ;
    USE SIGNAL ;
    PORT
      LAYER M5 ;
        RECT  125.568 0 125.592 0.084 ;
    END
  END xbi[232]
  PIN xbi[233]
    DIRECTION INPUT ;
    USE SIGNAL ;
    PORT
      LAYER M5 ;
        RECT  125.712 0 125.736 0.084 ;
    END
  END xbi[233]
  PIN xbi[234]
    DIRECTION INPUT ;
    USE SIGNAL ;
    PORT
      LAYER M5 ;
        RECT  125.856 0 125.88 0.084 ;
    END
  END xbi[234]
  PIN xbi[235]
    DIRECTION INPUT ;
    USE SIGNAL ;
    PORT
      LAYER M5 ;
        RECT  126 0 126.024 0.084 ;
    END
  END xbi[235]
  PIN xbi[236]
    DIRECTION INPUT ;
    USE SIGNAL ;
    PORT
      LAYER M5 ;
        RECT  126.144 0 126.168 0.084 ;
    END
  END xbi[236]
  PIN xbi[237]
    DIRECTION INPUT ;
    USE SIGNAL ;
    PORT
      LAYER M5 ;
        RECT  126.288 0 126.312 0.084 ;
    END
  END xbi[237]
  PIN xbi[238]
    DIRECTION INPUT ;
    USE SIGNAL ;
    PORT
      LAYER M5 ;
        RECT  126.432 0 126.456 0.084 ;
    END
  END xbi[238]
  PIN xbi[239]
    DIRECTION INPUT ;
    USE SIGNAL ;
    PORT
      LAYER M5 ;
        RECT  126.576 0 126.6 0.084 ;
    END
  END xbi[239]
  PIN xbi[23]
    DIRECTION INPUT ;
    USE SIGNAL ;
    PORT
      LAYER M5 ;
        RECT  95.472 0 95.496 0.084 ;
    END
  END xbi[23]
  PIN xbi[240]
    DIRECTION INPUT ;
    USE SIGNAL ;
    PORT
      LAYER M5 ;
        RECT  126.72 0 126.744 0.084 ;
    END
  END xbi[240]
  PIN xbi[241]
    DIRECTION INPUT ;
    USE SIGNAL ;
    PORT
      LAYER M5 ;
        RECT  126.864 0 126.888 0.084 ;
    END
  END xbi[241]
  PIN xbi[242]
    DIRECTION INPUT ;
    USE SIGNAL ;
    PORT
      LAYER M5 ;
        RECT  127.008 0 127.032 0.084 ;
    END
  END xbi[242]
  PIN xbi[243]
    DIRECTION INPUT ;
    USE SIGNAL ;
    PORT
      LAYER M5 ;
        RECT  127.152 0 127.176 0.084 ;
    END
  END xbi[243]
  PIN xbi[244]
    DIRECTION INPUT ;
    USE SIGNAL ;
    PORT
      LAYER M5 ;
        RECT  127.296 0 127.32 0.084 ;
    END
  END xbi[244]
  PIN xbi[245]
    DIRECTION INPUT ;
    USE SIGNAL ;
    PORT
      LAYER M5 ;
        RECT  127.44 0 127.464 0.084 ;
    END
  END xbi[245]
  PIN xbi[246]
    DIRECTION INPUT ;
    USE SIGNAL ;
    PORT
      LAYER M5 ;
        RECT  127.584 0 127.608 0.084 ;
    END
  END xbi[246]
  PIN xbi[247]
    DIRECTION INPUT ;
    USE SIGNAL ;
    PORT
      LAYER M5 ;
        RECT  127.728 0 127.752 0.084 ;
    END
  END xbi[247]
  PIN xbi[248]
    DIRECTION INPUT ;
    USE SIGNAL ;
    PORT
      LAYER M5 ;
        RECT  127.872 0 127.896 0.084 ;
    END
  END xbi[248]
  PIN xbi[249]
    DIRECTION INPUT ;
    USE SIGNAL ;
    PORT
      LAYER M5 ;
        RECT  128.016 0 128.04 0.084 ;
    END
  END xbi[249]
  PIN xbi[24]
    DIRECTION INPUT ;
    USE SIGNAL ;
    PORT
      LAYER M5 ;
        RECT  95.616 0 95.64 0.084 ;
    END
  END xbi[24]
  PIN xbi[250]
    DIRECTION INPUT ;
    USE SIGNAL ;
    PORT
      LAYER M5 ;
        RECT  128.16 0 128.184 0.084 ;
    END
  END xbi[250]
  PIN xbi[251]
    DIRECTION INPUT ;
    USE SIGNAL ;
    PORT
      LAYER M5 ;
        RECT  128.304 0 128.328 0.084 ;
    END
  END xbi[251]
  PIN xbi[252]
    DIRECTION INPUT ;
    USE SIGNAL ;
    PORT
      LAYER M5 ;
        RECT  128.448 0 128.472 0.084 ;
    END
  END xbi[252]
  PIN xbi[253]
    DIRECTION INPUT ;
    USE SIGNAL ;
    PORT
      LAYER M5 ;
        RECT  128.592 0 128.616 0.084 ;
    END
  END xbi[253]
  PIN xbi[254]
    DIRECTION INPUT ;
    USE SIGNAL ;
    PORT
      LAYER M5 ;
        RECT  128.736 0 128.76 0.084 ;
    END
  END xbi[254]
  PIN xbi[255]
    DIRECTION INPUT ;
    USE SIGNAL ;
    PORT
      LAYER M5 ;
        RECT  128.88 0 128.904 0.084 ;
    END
  END xbi[255]
  PIN xbi[256]
    DIRECTION INPUT ;
    USE SIGNAL ;
    PORT
      LAYER M5 ;
        RECT  129.024 0 129.048 0.084 ;
    END
  END xbi[256]
  PIN xbi[257]
    DIRECTION INPUT ;
    USE SIGNAL ;
    PORT
      LAYER M5 ;
        RECT  129.168 0 129.192 0.084 ;
    END
  END xbi[257]
  PIN xbi[258]
    DIRECTION INPUT ;
    USE SIGNAL ;
    PORT
      LAYER M5 ;
        RECT  129.312 0 129.336 0.084 ;
    END
  END xbi[258]
  PIN xbi[259]
    DIRECTION INPUT ;
    USE SIGNAL ;
    PORT
      LAYER M5 ;
        RECT  129.456 0 129.48 0.084 ;
    END
  END xbi[259]
  PIN xbi[25]
    DIRECTION INPUT ;
    USE SIGNAL ;
    PORT
      LAYER M5 ;
        RECT  95.76 0 95.784 0.084 ;
    END
  END xbi[25]
  PIN xbi[260]
    DIRECTION INPUT ;
    USE SIGNAL ;
    PORT
      LAYER M5 ;
        RECT  129.6 0 129.624 0.084 ;
    END
  END xbi[260]
  PIN xbi[261]
    DIRECTION INPUT ;
    USE SIGNAL ;
    PORT
      LAYER M5 ;
        RECT  129.744 0 129.768 0.084 ;
    END
  END xbi[261]
  PIN xbi[262]
    DIRECTION INPUT ;
    USE SIGNAL ;
    PORT
      LAYER M5 ;
        RECT  129.888 0 129.912 0.084 ;
    END
  END xbi[262]
  PIN xbi[263]
    DIRECTION INPUT ;
    USE SIGNAL ;
    PORT
      LAYER M5 ;
        RECT  130.032 0 130.056 0.084 ;
    END
  END xbi[263]
  PIN xbi[264]
    DIRECTION INPUT ;
    USE SIGNAL ;
    PORT
      LAYER M5 ;
        RECT  130.176 0 130.2 0.084 ;
    END
  END xbi[264]
  PIN xbi[265]
    DIRECTION INPUT ;
    USE SIGNAL ;
    PORT
      LAYER M5 ;
        RECT  130.32 0 130.344 0.084 ;
    END
  END xbi[265]
  PIN xbi[26]
    DIRECTION INPUT ;
    USE SIGNAL ;
    PORT
      LAYER M5 ;
        RECT  95.904 0 95.928 0.084 ;
    END
  END xbi[26]
  PIN xbi[27]
    DIRECTION INPUT ;
    USE SIGNAL ;
    PORT
      LAYER M5 ;
        RECT  96.048 0 96.072 0.084 ;
    END
  END xbi[27]
  PIN xbi[28]
    DIRECTION INPUT ;
    USE SIGNAL ;
    PORT
      LAYER M5 ;
        RECT  96.192 0 96.216 0.084 ;
    END
  END xbi[28]
  PIN xbi[29]
    DIRECTION INPUT ;
    USE SIGNAL ;
    PORT
      LAYER M5 ;
        RECT  96.336 0 96.36 0.084 ;
    END
  END xbi[29]
  PIN xbi[2]
    DIRECTION INPUT ;
    USE SIGNAL ;
    PORT
      LAYER M5 ;
        RECT  92.448 0 92.472 0.084 ;
    END
  END xbi[2]
  PIN xbi[30]
    DIRECTION INPUT ;
    USE SIGNAL ;
    PORT
      LAYER M5 ;
        RECT  96.48 0 96.504 0.084 ;
    END
  END xbi[30]
  PIN xbi[31]
    DIRECTION INPUT ;
    USE SIGNAL ;
    PORT
      LAYER M5 ;
        RECT  96.624 0 96.648 0.084 ;
    END
  END xbi[31]
  PIN xbi[32]
    DIRECTION INPUT ;
    USE SIGNAL ;
    PORT
      LAYER M5 ;
        RECT  96.768 0 96.792 0.084 ;
    END
  END xbi[32]
  PIN xbi[33]
    DIRECTION INPUT ;
    USE SIGNAL ;
    PORT
      LAYER M5 ;
        RECT  96.912 0 96.936 0.084 ;
    END
  END xbi[33]
  PIN xbi[34]
    DIRECTION INPUT ;
    USE SIGNAL ;
    PORT
      LAYER M5 ;
        RECT  97.056 0 97.08 0.084 ;
    END
  END xbi[34]
  PIN xbi[35]
    DIRECTION INPUT ;
    USE SIGNAL ;
    PORT
      LAYER M5 ;
        RECT  97.2 0 97.224 0.084 ;
    END
  END xbi[35]
  PIN xbi[36]
    DIRECTION INPUT ;
    USE SIGNAL ;
    PORT
      LAYER M5 ;
        RECT  97.344 0 97.368 0.084 ;
    END
  END xbi[36]
  PIN xbi[37]
    DIRECTION INPUT ;
    USE SIGNAL ;
    PORT
      LAYER M5 ;
        RECT  97.488 0 97.512 0.084 ;
    END
  END xbi[37]
  PIN xbi[38]
    DIRECTION INPUT ;
    USE SIGNAL ;
    PORT
      LAYER M5 ;
        RECT  97.632 0 97.656 0.084 ;
    END
  END xbi[38]
  PIN xbi[39]
    DIRECTION INPUT ;
    USE SIGNAL ;
    PORT
      LAYER M5 ;
        RECT  97.776 0 97.8 0.084 ;
    END
  END xbi[39]
  PIN xbi[3]
    DIRECTION INPUT ;
    USE SIGNAL ;
    PORT
      LAYER M5 ;
        RECT  92.592 0 92.616 0.084 ;
    END
  END xbi[3]
  PIN xbi[40]
    DIRECTION INPUT ;
    USE SIGNAL ;
    PORT
      LAYER M5 ;
        RECT  97.92 0 97.944 0.084 ;
    END
  END xbi[40]
  PIN xbi[41]
    DIRECTION INPUT ;
    USE SIGNAL ;
    PORT
      LAYER M5 ;
        RECT  98.064 0 98.088 0.084 ;
    END
  END xbi[41]
  PIN xbi[42]
    DIRECTION INPUT ;
    USE SIGNAL ;
    PORT
      LAYER M5 ;
        RECT  98.208 0 98.232 0.084 ;
    END
  END xbi[42]
  PIN xbi[43]
    DIRECTION INPUT ;
    USE SIGNAL ;
    PORT
      LAYER M5 ;
        RECT  98.352 0 98.376 0.084 ;
    END
  END xbi[43]
  PIN xbi[44]
    DIRECTION INPUT ;
    USE SIGNAL ;
    PORT
      LAYER M5 ;
        RECT  98.496 0 98.52 0.084 ;
    END
  END xbi[44]
  PIN xbi[45]
    DIRECTION INPUT ;
    USE SIGNAL ;
    PORT
      LAYER M5 ;
        RECT  98.64 0 98.664 0.084 ;
    END
  END xbi[45]
  PIN xbi[46]
    DIRECTION INPUT ;
    USE SIGNAL ;
    PORT
      LAYER M5 ;
        RECT  98.784 0 98.808 0.084 ;
    END
  END xbi[46]
  PIN xbi[47]
    DIRECTION INPUT ;
    USE SIGNAL ;
    PORT
      LAYER M5 ;
        RECT  98.928 0 98.952 0.084 ;
    END
  END xbi[47]
  PIN xbi[48]
    DIRECTION INPUT ;
    USE SIGNAL ;
    PORT
      LAYER M5 ;
        RECT  99.072 0 99.096 0.084 ;
    END
  END xbi[48]
  PIN xbi[49]
    DIRECTION INPUT ;
    USE SIGNAL ;
    PORT
      LAYER M5 ;
        RECT  99.216 0 99.24 0.084 ;
    END
  END xbi[49]
  PIN xbi[4]
    DIRECTION INPUT ;
    USE SIGNAL ;
    PORT
      LAYER M5 ;
        RECT  92.736 0 92.76 0.084 ;
    END
  END xbi[4]
  PIN xbi[50]
    DIRECTION INPUT ;
    USE SIGNAL ;
    PORT
      LAYER M5 ;
        RECT  99.36 0 99.384 0.084 ;
    END
  END xbi[50]
  PIN xbi[51]
    DIRECTION INPUT ;
    USE SIGNAL ;
    PORT
      LAYER M5 ;
        RECT  99.504 0 99.528 0.084 ;
    END
  END xbi[51]
  PIN xbi[52]
    DIRECTION INPUT ;
    USE SIGNAL ;
    PORT
      LAYER M5 ;
        RECT  99.648 0 99.672 0.084 ;
    END
  END xbi[52]
  PIN xbi[53]
    DIRECTION INPUT ;
    USE SIGNAL ;
    PORT
      LAYER M5 ;
        RECT  99.792 0 99.816 0.084 ;
    END
  END xbi[53]
  PIN xbi[54]
    DIRECTION INPUT ;
    USE SIGNAL ;
    PORT
      LAYER M5 ;
        RECT  99.936 0 99.96 0.084 ;
    END
  END xbi[54]
  PIN xbi[55]
    DIRECTION INPUT ;
    USE SIGNAL ;
    PORT
      LAYER M5 ;
        RECT  100.08 0 100.104 0.084 ;
    END
  END xbi[55]
  PIN xbi[56]
    DIRECTION INPUT ;
    USE SIGNAL ;
    PORT
      LAYER M5 ;
        RECT  100.224 0 100.248 0.084 ;
    END
  END xbi[56]
  PIN xbi[57]
    DIRECTION INPUT ;
    USE SIGNAL ;
    PORT
      LAYER M5 ;
        RECT  100.368 0 100.392 0.084 ;
    END
  END xbi[57]
  PIN xbi[58]
    DIRECTION INPUT ;
    USE SIGNAL ;
    PORT
      LAYER M5 ;
        RECT  100.512 0 100.536 0.084 ;
    END
  END xbi[58]
  PIN xbi[59]
    DIRECTION INPUT ;
    USE SIGNAL ;
    PORT
      LAYER M5 ;
        RECT  100.656 0 100.68 0.084 ;
    END
  END xbi[59]
  PIN xbi[5]
    DIRECTION INPUT ;
    USE SIGNAL ;
    PORT
      LAYER M5 ;
        RECT  92.88 0 92.904 0.084 ;
    END
  END xbi[5]
  PIN xbi[60]
    DIRECTION INPUT ;
    USE SIGNAL ;
    PORT
      LAYER M5 ;
        RECT  100.8 0 100.824 0.084 ;
    END
  END xbi[60]
  PIN xbi[61]
    DIRECTION INPUT ;
    USE SIGNAL ;
    PORT
      LAYER M5 ;
        RECT  100.944 0 100.968 0.084 ;
    END
  END xbi[61]
  PIN xbi[62]
    DIRECTION INPUT ;
    USE SIGNAL ;
    PORT
      LAYER M5 ;
        RECT  101.088 0 101.112 0.084 ;
    END
  END xbi[62]
  PIN xbi[63]
    DIRECTION INPUT ;
    USE SIGNAL ;
    PORT
      LAYER M5 ;
        RECT  101.232 0 101.256 0.084 ;
    END
  END xbi[63]
  PIN xbi[64]
    DIRECTION INPUT ;
    USE SIGNAL ;
    PORT
      LAYER M5 ;
        RECT  101.376 0 101.4 0.084 ;
    END
  END xbi[64]
  PIN xbi[65]
    DIRECTION INPUT ;
    USE SIGNAL ;
    PORT
      LAYER M5 ;
        RECT  101.52 0 101.544 0.084 ;
    END
  END xbi[65]
  PIN xbi[66]
    DIRECTION INPUT ;
    USE SIGNAL ;
    PORT
      LAYER M5 ;
        RECT  101.664 0 101.688 0.084 ;
    END
  END xbi[66]
  PIN xbi[67]
    DIRECTION INPUT ;
    USE SIGNAL ;
    PORT
      LAYER M5 ;
        RECT  101.808 0 101.832 0.084 ;
    END
  END xbi[67]
  PIN xbi[68]
    DIRECTION INPUT ;
    USE SIGNAL ;
    PORT
      LAYER M5 ;
        RECT  101.952 0 101.976 0.084 ;
    END
  END xbi[68]
  PIN xbi[69]
    DIRECTION INPUT ;
    USE SIGNAL ;
    PORT
      LAYER M5 ;
        RECT  102.096 0 102.12 0.084 ;
    END
  END xbi[69]
  PIN xbi[6]
    DIRECTION INPUT ;
    USE SIGNAL ;
    PORT
      LAYER M5 ;
        RECT  93.024 0 93.048 0.084 ;
    END
  END xbi[6]
  PIN xbi[70]
    DIRECTION INPUT ;
    USE SIGNAL ;
    PORT
      LAYER M5 ;
        RECT  102.24 0 102.264 0.084 ;
    END
  END xbi[70]
  PIN xbi[71]
    DIRECTION INPUT ;
    USE SIGNAL ;
    PORT
      LAYER M5 ;
        RECT  102.384 0 102.408 0.084 ;
    END
  END xbi[71]
  PIN xbi[72]
    DIRECTION INPUT ;
    USE SIGNAL ;
    PORT
      LAYER M5 ;
        RECT  102.528 0 102.552 0.084 ;
    END
  END xbi[72]
  PIN xbi[73]
    DIRECTION INPUT ;
    USE SIGNAL ;
    PORT
      LAYER M5 ;
        RECT  102.672 0 102.696 0.084 ;
    END
  END xbi[73]
  PIN xbi[74]
    DIRECTION INPUT ;
    USE SIGNAL ;
    PORT
      LAYER M5 ;
        RECT  102.816 0 102.84 0.084 ;
    END
  END xbi[74]
  PIN xbi[75]
    DIRECTION INPUT ;
    USE SIGNAL ;
    PORT
      LAYER M5 ;
        RECT  102.96 0 102.984 0.084 ;
    END
  END xbi[75]
  PIN xbi[76]
    DIRECTION INPUT ;
    USE SIGNAL ;
    PORT
      LAYER M5 ;
        RECT  103.104 0 103.128 0.084 ;
    END
  END xbi[76]
  PIN xbi[77]
    DIRECTION INPUT ;
    USE SIGNAL ;
    PORT
      LAYER M5 ;
        RECT  103.248 0 103.272 0.084 ;
    END
  END xbi[77]
  PIN xbi[78]
    DIRECTION INPUT ;
    USE SIGNAL ;
    PORT
      LAYER M5 ;
        RECT  103.392 0 103.416 0.084 ;
    END
  END xbi[78]
  PIN xbi[79]
    DIRECTION INPUT ;
    USE SIGNAL ;
    PORT
      LAYER M5 ;
        RECT  103.536 0 103.56 0.084 ;
    END
  END xbi[79]
  PIN xbi[7]
    DIRECTION INPUT ;
    USE SIGNAL ;
    PORT
      LAYER M5 ;
        RECT  93.168 0 93.192 0.084 ;
    END
  END xbi[7]
  PIN xbi[80]
    DIRECTION INPUT ;
    USE SIGNAL ;
    PORT
      LAYER M5 ;
        RECT  103.68 0 103.704 0.084 ;
    END
  END xbi[80]
  PIN xbi[81]
    DIRECTION INPUT ;
    USE SIGNAL ;
    PORT
      LAYER M5 ;
        RECT  103.824 0 103.848 0.084 ;
    END
  END xbi[81]
  PIN xbi[82]
    DIRECTION INPUT ;
    USE SIGNAL ;
    PORT
      LAYER M5 ;
        RECT  103.968 0 103.992 0.084 ;
    END
  END xbi[82]
  PIN xbi[83]
    DIRECTION INPUT ;
    USE SIGNAL ;
    PORT
      LAYER M5 ;
        RECT  104.112 0 104.136 0.084 ;
    END
  END xbi[83]
  PIN xbi[84]
    DIRECTION INPUT ;
    USE SIGNAL ;
    PORT
      LAYER M5 ;
        RECT  104.256 0 104.28 0.084 ;
    END
  END xbi[84]
  PIN xbi[85]
    DIRECTION INPUT ;
    USE SIGNAL ;
    PORT
      LAYER M5 ;
        RECT  104.4 0 104.424 0.084 ;
    END
  END xbi[85]
  PIN xbi[86]
    DIRECTION INPUT ;
    USE SIGNAL ;
    PORT
      LAYER M5 ;
        RECT  104.544 0 104.568 0.084 ;
    END
  END xbi[86]
  PIN xbi[87]
    DIRECTION INPUT ;
    USE SIGNAL ;
    PORT
      LAYER M5 ;
        RECT  104.688 0 104.712 0.084 ;
    END
  END xbi[87]
  PIN xbi[88]
    DIRECTION INPUT ;
    USE SIGNAL ;
    PORT
      LAYER M5 ;
        RECT  104.832 0 104.856 0.084 ;
    END
  END xbi[88]
  PIN xbi[89]
    DIRECTION INPUT ;
    USE SIGNAL ;
    PORT
      LAYER M5 ;
        RECT  104.976 0 105 0.084 ;
    END
  END xbi[89]
  PIN xbi[8]
    DIRECTION INPUT ;
    USE SIGNAL ;
    PORT
      LAYER M5 ;
        RECT  93.312 0 93.336 0.084 ;
    END
  END xbi[8]
  PIN xbi[90]
    DIRECTION INPUT ;
    USE SIGNAL ;
    PORT
      LAYER M5 ;
        RECT  105.12 0 105.144 0.084 ;
    END
  END xbi[90]
  PIN xbi[91]
    DIRECTION INPUT ;
    USE SIGNAL ;
    PORT
      LAYER M5 ;
        RECT  105.264 0 105.288 0.084 ;
    END
  END xbi[91]
  PIN xbi[92]
    DIRECTION INPUT ;
    USE SIGNAL ;
    PORT
      LAYER M5 ;
        RECT  105.408 0 105.432 0.084 ;
    END
  END xbi[92]
  PIN xbi[93]
    DIRECTION INPUT ;
    USE SIGNAL ;
    PORT
      LAYER M5 ;
        RECT  105.552 0 105.576 0.084 ;
    END
  END xbi[93]
  PIN xbi[94]
    DIRECTION INPUT ;
    USE SIGNAL ;
    PORT
      LAYER M5 ;
        RECT  105.696 0 105.72 0.084 ;
    END
  END xbi[94]
  PIN xbi[95]
    DIRECTION INPUT ;
    USE SIGNAL ;
    PORT
      LAYER M5 ;
        RECT  105.84 0 105.864 0.084 ;
    END
  END xbi[95]
  PIN xbi[96]
    DIRECTION INPUT ;
    USE SIGNAL ;
    PORT
      LAYER M5 ;
        RECT  105.984 0 106.008 0.084 ;
    END
  END xbi[96]
  PIN xbi[97]
    DIRECTION INPUT ;
    USE SIGNAL ;
    PORT
      LAYER M5 ;
        RECT  106.128 0 106.152 0.084 ;
    END
  END xbi[97]
  PIN xbi[98]
    DIRECTION INPUT ;
    USE SIGNAL ;
    PORT
      LAYER M5 ;
        RECT  106.272 0 106.296 0.084 ;
    END
  END xbi[98]
  PIN xbi[99]
    DIRECTION INPUT ;
    USE SIGNAL ;
    PORT
      LAYER M5 ;
        RECT  106.416 0 106.44 0.084 ;
    END
  END xbi[99]
  PIN xbi[9]
    DIRECTION INPUT ;
    USE SIGNAL ;
    PORT
      LAYER M5 ;
        RECT  93.456 0 93.48 0.084 ;
    END
  END xbi[9]
  PIN VDD
    DIRECTION INOUT ;
    USE POWER ;
    PORT
      LAYER M5 ;
        RECT  169.992 2.151 170.112 28.089 ;
        RECT  167.292 2.151 167.412 28.089 ;
        RECT  164.592 2.151 164.712 28.089 ;
        RECT  161.892 2.151 162.012 28.089 ;
        RECT  159.192 2.151 159.312 28.089 ;
        RECT  156.492 2.151 156.612 28.089 ;
        RECT  153.792 2.151 153.912 28.089 ;
        RECT  151.092 2.151 151.212 28.089 ;
        RECT  148.392 2.151 148.512 28.089 ;
        RECT  145.692 2.151 145.812 28.089 ;
        RECT  142.992 2.151 143.112 28.089 ;
        RECT  140.292 2.151 140.412 28.089 ;
        RECT  137.592 2.151 137.712 28.089 ;
        RECT  134.892 2.151 135.012 28.089 ;
        RECT  132.192 2.151 132.312 28.089 ;
        RECT  129.492 2.151 129.612 28.089 ;
        RECT  126.792 2.151 126.912 28.089 ;
        RECT  124.092 2.151 124.212 28.089 ;
        RECT  121.392 2.151 121.512 28.089 ;
        RECT  118.692 2.151 118.812 28.089 ;
        RECT  115.992 2.151 116.112 28.089 ;
        RECT  113.292 2.151 113.412 28.089 ;
        RECT  110.592 2.151 110.712 28.089 ;
        RECT  107.892 2.151 108.012 28.089 ;
        RECT  105.192 2.151 105.312 28.089 ;
        RECT  102.492 2.151 102.612 28.089 ;
        RECT  99.792 2.151 99.912 28.089 ;
        RECT  97.092 2.151 97.212 28.089 ;
        RECT  94.392 2.151 94.512 28.089 ;
        RECT  91.692 2.151 91.812 28.089 ;
        RECT  88.992 2.151 89.112 28.089 ;
        RECT  86.292 2.151 86.412 28.089 ;
        RECT  83.592 2.151 83.712 28.089 ;
        RECT  80.892 2.151 81.012 28.089 ;
        RECT  78.192 2.151 78.312 28.089 ;
        RECT  75.492 2.151 75.612 28.089 ;
        RECT  72.792 2.151 72.912 28.089 ;
        RECT  70.092 2.151 70.212 28.089 ;
        RECT  67.392 2.151 67.512 28.089 ;
        RECT  64.692 2.151 64.812 28.089 ;
        RECT  61.992 2.151 62.112 28.089 ;
        RECT  59.292 2.151 59.412 28.089 ;
        RECT  56.592 2.151 56.712 28.089 ;
        RECT  53.892 2.151 54.012 28.089 ;
        RECT  51.192 2.151 51.312 28.089 ;
        RECT  48.492 2.151 48.612 28.089 ;
        RECT  45.792 2.151 45.912 28.089 ;
        RECT  43.092 2.151 43.212 28.089 ;
        RECT  40.392 2.151 40.512 28.089 ;
        RECT  37.692 2.151 37.812 28.089 ;
        RECT  34.992 2.151 35.112 28.089 ;
        RECT  32.292 2.151 32.412 28.089 ;
        RECT  29.592 2.151 29.712 28.089 ;
        RECT  26.892 2.151 27.012 28.089 ;
        RECT  24.192 2.151 24.312 28.089 ;
        RECT  21.492 2.151 21.612 28.089 ;
        RECT  18.792 2.151 18.912 28.089 ;
        RECT  16.092 2.151 16.212 28.089 ;
        RECT  13.392 2.151 13.512 28.089 ;
        RECT  10.692 2.151 10.812 28.089 ;
        RECT  7.992 2.151 8.112 28.089 ;
        RECT  5.292 2.151 5.412 28.089 ;
        RECT  2.592 2.151 2.712 28.089 ;
    END
  END VDD
  PIN VSS
    DIRECTION INOUT ;
    USE GROUND ;
    PORT
      LAYER M5 ;
        RECT  169.8 2.137 169.92 28.103 ;
        RECT  167.1 2.137 167.22 28.103 ;
        RECT  164.4 2.137 164.52 28.103 ;
        RECT  161.7 2.137 161.82 28.103 ;
        RECT  159 2.137 159.12 28.103 ;
        RECT  156.3 2.137 156.42 28.103 ;
        RECT  153.6 2.137 153.72 28.103 ;
        RECT  150.9 2.137 151.02 28.103 ;
        RECT  148.2 2.137 148.32 28.103 ;
        RECT  145.5 2.137 145.62 28.103 ;
        RECT  142.8 2.137 142.92 28.103 ;
        RECT  140.1 2.137 140.22 28.103 ;
        RECT  137.4 2.137 137.52 28.103 ;
        RECT  134.7 2.137 134.82 28.103 ;
        RECT  132 2.137 132.12 28.103 ;
        RECT  129.3 2.137 129.42 28.103 ;
        RECT  126.6 2.137 126.72 28.103 ;
        RECT  123.9 2.137 124.02 28.103 ;
        RECT  121.2 2.137 121.32 28.103 ;
        RECT  118.5 2.137 118.62 28.103 ;
        RECT  115.8 2.137 115.92 28.103 ;
        RECT  113.1 2.137 113.22 28.103 ;
        RECT  110.4 2.137 110.52 28.103 ;
        RECT  107.7 2.137 107.82 28.103 ;
        RECT  105 2.137 105.12 28.103 ;
        RECT  102.3 2.137 102.42 28.103 ;
        RECT  99.6 2.137 99.72 28.103 ;
        RECT  96.9 2.137 97.02 28.103 ;
        RECT  94.2 2.137 94.32 28.103 ;
        RECT  91.5 2.137 91.62 28.103 ;
        RECT  88.8 2.137 88.92 28.103 ;
        RECT  86.1 2.137 86.22 28.103 ;
        RECT  83.4 2.137 83.52 28.103 ;
        RECT  80.7 2.137 80.82 28.103 ;
        RECT  78 2.137 78.12 28.103 ;
        RECT  75.3 2.137 75.42 28.103 ;
        RECT  72.6 2.137 72.72 28.103 ;
        RECT  69.9 2.137 70.02 28.103 ;
        RECT  67.2 2.137 67.32 28.103 ;
        RECT  64.5 2.137 64.62 28.103 ;
        RECT  61.8 2.137 61.92 28.103 ;
        RECT  59.1 2.137 59.22 28.103 ;
        RECT  56.4 2.137 56.52 28.103 ;
        RECT  53.7 2.137 53.82 28.103 ;
        RECT  51 2.137 51.12 28.103 ;
        RECT  48.3 2.137 48.42 28.103 ;
        RECT  45.6 2.137 45.72 28.103 ;
        RECT  42.9 2.137 43.02 28.103 ;
        RECT  40.2 2.137 40.32 28.103 ;
        RECT  37.5 2.137 37.62 28.103 ;
        RECT  34.8 2.137 34.92 28.103 ;
        RECT  32.1 2.137 32.22 28.103 ;
        RECT  29.4 2.137 29.52 28.103 ;
        RECT  26.7 2.137 26.82 28.103 ;
        RECT  24 2.137 24.12 28.103 ;
        RECT  21.3 2.137 21.42 28.103 ;
        RECT  18.6 2.137 18.72 28.103 ;
        RECT  15.9 2.137 16.02 28.103 ;
        RECT  13.2 2.137 13.32 28.103 ;
        RECT  10.5 2.137 10.62 28.103 ;
        RECT  7.8 2.137 7.92 28.103 ;
        RECT  5.1 2.137 5.22 28.103 ;
        RECT  2.4 2.137 2.52 28.103 ;
    END
  END VSS
  # OT_OBS_CLOSED layer=M5 d_um=1.536 added=130
  OBS
    LAYER RVTN ;
     RECT  2.16 2.16 170.64 2.295 ;
     RECT  2.16 2.565 170.64 2.835 ;
     RECT  2.16 3.105 170.64 3.375 ;
     RECT  2.16 3.645 170.64 3.915 ;
     RECT  2.16 4.185 170.64 4.455 ;
     RECT  2.16 4.725 170.64 4.995 ;
     RECT  2.16 5.265 170.64 5.535 ;
     RECT  2.16 5.805 170.64 6.075 ;
     RECT  2.16 6.345 170.64 6.615 ;
     RECT  2.16 6.885 170.64 7.155 ;
     RECT  2.16 7.425 170.64 7.695 ;
     RECT  2.16 7.965 170.64 8.235 ;
     RECT  2.16 8.505 170.64 8.775 ;
     RECT  2.16 9.045 170.64 9.315 ;
     RECT  2.16 9.585 170.64 9.855 ;
     RECT  2.16 10.125 170.64 10.395 ;
     RECT  2.16 10.665 170.64 10.935 ;
     RECT  2.16 11.205 170.64 11.475 ;
     RECT  2.16 11.745 170.64 12.015 ;
     RECT  2.16 12.285 170.64 12.555 ;
     RECT  2.16 12.825 170.64 13.095 ;
     RECT  2.16 13.365 170.64 13.635 ;
     RECT  2.16 13.905 170.64 14.175 ;
     RECT  2.16 14.445 170.64 14.715 ;
     RECT  2.16 14.985 170.64 15.255 ;
     RECT  2.16 15.525 170.64 15.795 ;
     RECT  2.16 16.065 170.64 16.335 ;
     RECT  2.16 16.605 170.64 16.875 ;
     RECT  2.16 17.145 170.64 17.415 ;
     RECT  2.16 17.685 170.64 17.955 ;
     RECT  2.16 18.225 170.64 18.495 ;
     RECT  2.16 18.765 170.64 19.035 ;
     RECT  2.16 19.305 170.64 19.575 ;
     RECT  2.16 19.845 170.64 20.115 ;
     RECT  2.16 20.385 170.64 20.655 ;
     RECT  2.16 20.925 170.64 21.195 ;
     RECT  2.16 21.465 170.64 21.735 ;
     RECT  2.16 22.005 170.64 22.275 ;
     RECT  2.16 22.545 170.64 22.815 ;
     RECT  2.16 23.085 170.64 23.355 ;
     RECT  2.16 23.625 170.64 23.895 ;
     RECT  2.16 24.165 170.64 24.435 ;
     RECT  2.16 24.705 170.64 24.975 ;
     RECT  2.16 25.245 170.64 25.515 ;
     RECT  2.16 25.785 170.64 26.055 ;
     RECT  2.16 26.325 170.64 26.595 ;
     RECT  2.16 26.865 170.64 27.135 ;
     RECT  2.16 27.405 170.64 27.675 ;
     RECT  2.16 27.945 170.64 28.08 ;
    LAYER RVTP ;
     RECT  2.16 2.295 170.64 2.565 ;
     RECT  2.16 2.835 170.64 3.105 ;
     RECT  2.16 3.375 170.64 3.645 ;
     RECT  2.16 3.915 170.64 4.185 ;
     RECT  2.16 4.455 170.64 4.725 ;
     RECT  2.16 4.995 170.64 5.265 ;
     RECT  2.16 5.535 170.64 5.805 ;
     RECT  2.16 6.075 170.64 6.345 ;
     RECT  2.16 6.615 170.64 6.885 ;
     RECT  2.16 7.155 170.64 7.425 ;
     RECT  2.16 7.695 170.64 7.965 ;
     RECT  2.16 8.235 170.64 8.505 ;
     RECT  2.16 8.775 170.64 9.045 ;
     RECT  2.16 9.315 170.64 9.585 ;
     RECT  2.16 9.855 170.64 10.125 ;
     RECT  2.16 10.395 170.64 10.665 ;
     RECT  2.16 10.935 170.64 11.205 ;
     RECT  2.16 11.475 170.64 11.745 ;
     RECT  2.16 12.015 170.64 12.285 ;
     RECT  2.16 12.555 170.64 12.825 ;
     RECT  2.16 13.095 170.64 13.365 ;
     RECT  2.16 13.635 170.64 13.905 ;
     RECT  2.16 14.175 170.64 14.445 ;
     RECT  2.16 14.715 170.64 14.985 ;
     RECT  2.16 15.255 170.64 15.525 ;
     RECT  2.16 15.795 170.64 16.065 ;
     RECT  2.16 16.335 170.64 16.605 ;
     RECT  2.16 16.875 170.64 17.145 ;
     RECT  2.16 17.415 170.64 17.685 ;
     RECT  2.16 17.955 170.64 18.225 ;
     RECT  2.16 18.495 170.64 18.765 ;
     RECT  2.16 19.035 170.64 19.305 ;
     RECT  2.16 19.575 170.64 19.845 ;
     RECT  2.16 20.115 170.64 20.385 ;
     RECT  2.16 20.655 170.64 20.925 ;
     RECT  2.16 21.195 170.64 21.465 ;
     RECT  2.16 21.735 170.64 22.005 ;
     RECT  2.16 22.275 170.64 22.545 ;
     RECT  2.16 22.815 170.64 23.085 ;
     RECT  2.16 23.355 170.64 23.625 ;
     RECT  2.16 23.895 170.64 24.165 ;
     RECT  2.16 24.435 170.64 24.705 ;
     RECT  2.16 24.975 170.64 25.245 ;
     RECT  2.16 25.515 170.64 25.785 ;
     RECT  2.16 26.055 170.64 26.325 ;
     RECT  2.16 26.595 170.64 26.865 ;
     RECT  2.16 27.135 170.64 27.405 ;
     RECT  2.16 27.675 170.64 27.945 ;
    LAYER M1 ;
     RECT  2.16 2.151 170.64 28.089 ;
    LAYER M2 ;
     RECT  0.103 17.082 2.16 17.1 ;
     RECT  2.16 2.151 60.763 28.089 ;
     RECT  60.763 1.926 62.419 28.089 ;
     RECT  62.419 1.836 69.259 28.089 ;
     RECT  69.259 1.8 74.371 28.089 ;
     RECT  91.867 29.034 92.003 29.052 ;
     RECT  102.127 29.034 102.263 29.052 ;
     RECT  107.455 29.034 107.591 29.052 ;
     RECT  74.371 1.764 145.427 28.089 ;
     RECT  145.427 1.836 150.475 28.089 ;
     RECT  150.475 1.764 164.435 28.089 ;
     RECT  164.435 1.836 169.475 28.089 ;
     RECT  169.475 1.962 170.339 28.089 ;
     RECT  170.339 2.151 170.64 28.089 ;
     RECT  170.64 4.428 170.699 5.526 ;
     RECT  170.64 2.916 170.987 2.934 ;
     RECT  170.699 4.428 171.023 5.364 ;
     RECT  171.023 5.04 171.599 5.364 ;
     RECT  171.599 5.04 171.635 5.256 ;
     RECT  171.635 5.238 171.671 5.256 ;
    LAYER M3 ;
     RECT  169.524 0.475 169.542 0.523 ;
     RECT  92.232 0.091 92.25 0.571 ;
     RECT  169.524 0.523 170.37 0.571 ;
     RECT  169.272 0.571 170.37 0.955 ;
     RECT  169.272 0.955 170.694 1.099 ;
     RECT  171.612 0.091 171.63 1.099 ;
     RECT  87.804 0.571 87.822 1.675 ;
     RECT  100.296 0.523 100.314 1.675 ;
     RECT  87.804 1.675 88.434 1.723 ;
     RECT  89.496 1.099 89.514 1.723 ;
     RECT  91.08 0.091 91.098 1.723 ;
     RECT  92.16 0.571 92.25 1.723 ;
     RECT  93.348 0.091 93.366 1.723 ;
     RECT  94.716 1.147 94.734 1.723 ;
     RECT  99.936 1.675 100.314 1.723 ;
     RECT  109.044 0.571 109.062 1.723 ;
     RECT  123.12 1.147 123.138 1.723 ;
     RECT  144.828 1.147 144.846 1.723 ;
     RECT  147.672 1.675 147.69 1.723 ;
     RECT  151.308 1.147 151.326 1.723 ;
     RECT  159.408 1.531 159.426 1.723 ;
     RECT  169.272 1.099 171.63 1.723 ;
     RECT  143.46 1.723 150.282 1.759 ;
     RECT  151.056 1.723 157.338 1.759 ;
     RECT  92.16 1.723 96.642 1.771 ;
     RECT  97.776 1.723 100.314 1.771 ;
     RECT  109.044 1.723 111.294 1.771 ;
     RECT  112.032 1.723 112.842 1.771 ;
     RECT  113.76 1.723 114.642 1.771 ;
     RECT  115.524 1.723 116.226 1.771 ;
     RECT  117.432 1.723 119.934 1.771 ;
     RECT  120.672 1.723 121.77 1.771 ;
     RECT  122.832 1.723 123.75 1.771 ;
     RECT  140.256 1.723 142.614 1.771 ;
     RECT  143.46 1.759 157.338 1.771 ;
     RECT  158.148 1.723 165.006 1.771 ;
     RECT  165.852 1.723 171.63 1.771 ;
     RECT  117.432 1.771 123.822 1.819 ;
     RECT  124.56 1.723 130.518 1.819 ;
     RECT  137.844 1.723 138.942 1.819 ;
     RECT  140.256 1.771 157.338 1.819 ;
     RECT  135.396 1.723 136.854 1.876 ;
     RECT  97.56 1.771 100.314 1.915 ;
     RECT  101.34 1.723 104.742 1.915 ;
     RECT  105.84 1.723 108.198 1.915 ;
     RECT  137.844 1.819 157.338 1.957 ;
     RECT  158.148 1.771 171.63 1.957 ;
     RECT  92.16 1.771 96.714 1.963 ;
     RECT  97.452 1.915 100.314 1.963 ;
     RECT  131.364 1.723 134.658 1.963 ;
     RECT  135.396 1.876 136.89 1.963 ;
     RECT  137.844 1.957 171.63 1.963 ;
     RECT  91.08 1.723 91.134 1.993 ;
     RECT  92.16 1.963 100.314 1.993 ;
     RECT  131.364 1.963 136.89 2.011 ;
     RECT  137.772 1.963 171.63 2.011 ;
     RECT  117.432 1.819 130.518 2.059 ;
     RECT  86.652 2.029 86.67 2.065 ;
     RECT  87.804 1.723 89.838 2.065 ;
     RECT  90.576 1.993 91.134 2.101 ;
     RECT  91.908 1.993 100.314 2.101 ;
     RECT  101.34 1.915 108.198 2.101 ;
     RECT  62.424 1.831 62.442 2.143 ;
     RECT  69.264 1.795 69.282 2.143 ;
     RECT  86.652 2.065 89.838 2.143 ;
     RECT  90.576 2.101 100.314 2.191 ;
     RECT  101.196 2.101 108.198 2.191 ;
     RECT  109.044 1.771 116.226 2.191 ;
     RECT  117.252 2.059 130.518 2.191 ;
     RECT  86.115 2.143 89.838 2.227 ;
     RECT  90.576 2.191 130.518 2.227 ;
     RECT  131.364 2.011 171.63 2.263 ;
     RECT  86.115 2.227 130.518 2.299 ;
     RECT  131.292 2.263 171.63 2.299 ;
     RECT  60.768 1.921 60.786 2.335 ;
     RECT  61.815 2.143 62.442 2.335 ;
     RECT  64.515 2.143 64.605 2.371 ;
     RECT  2.415 2.143 2.505 2.413 ;
     RECT  5.115 2.143 5.205 2.413 ;
     RECT  7.815 2.143 7.905 2.413 ;
     RECT  10.515 2.143 10.605 2.413 ;
     RECT  13.215 2.143 13.305 2.413 ;
     RECT  15.915 2.143 16.005 2.413 ;
     RECT  18.615 2.143 18.705 2.413 ;
     RECT  21.315 2.143 21.405 2.413 ;
     RECT  24.015 2.143 24.105 2.413 ;
     RECT  26.715 2.143 26.805 2.413 ;
     RECT  29.415 2.143 29.505 2.413 ;
     RECT  32.115 2.143 32.205 2.413 ;
     RECT  34.815 2.143 34.905 2.413 ;
     RECT  37.515 2.143 37.605 2.413 ;
     RECT  40.215 2.143 40.305 2.413 ;
     RECT  42.915 2.143 43.005 2.413 ;
     RECT  45.615 2.143 45.705 2.413 ;
     RECT  48.315 2.143 48.405 2.413 ;
     RECT  51.015 2.143 51.105 2.413 ;
     RECT  53.715 2.143 53.805 2.413 ;
     RECT  56.415 2.143 56.505 2.413 ;
     RECT  59.115 2.143 59.205 2.413 ;
     RECT  67.215 2.143 67.305 2.413 ;
     RECT  69.264 2.143 70.005 2.413 ;
     RECT  72.615 2.143 72.705 2.413 ;
     RECT  75.315 2.143 75.405 2.413 ;
     RECT  78.015 2.143 78.105 2.413 ;
     RECT  80.715 2.143 80.805 2.413 ;
     RECT  83.415 2.143 83.505 2.413 ;
     RECT  60.768 2.335 62.442 2.491 ;
     RECT  74.376 1.759 74.394 2.641 ;
     RECT  75.315 2.413 75.597 2.641 ;
     RECT  86.115 2.299 171.63 2.779 ;
     RECT  83.415 2.413 83.697 2.803 ;
     RECT  59.115 2.413 59.397 2.875 ;
     RECT  69.264 2.413 70.197 3.145 ;
     RECT  72.615 2.413 72.897 3.181 ;
     RECT  86.115 2.779 171.666 3.335 ;
     RECT  114.48 3.335 171.666 3.407 ;
     RECT  82.908 2.803 83.697 3.415 ;
     RECT  53.715 2.413 53.997 3.451 ;
     RECT  82.728 3.415 83.697 3.649 ;
     RECT  53.715 3.451 54.306 3.721 ;
     RECT  58.5 2.875 59.397 3.811 ;
     RECT  82.656 3.649 83.697 3.839 ;
     RECT  86.115 3.335 112.23 3.983 ;
     RECT  45.615 2.413 45.897 4.117 ;
     RECT  49.86 2.911 49.878 4.351 ;
     RECT  51.015 2.413 51.297 4.351 ;
     RECT  86.115 3.983 87.246 4.379 ;
     RECT  164.415 3.407 171.666 4.451 ;
     RECT  69.228 3.145 70.197 4.621 ;
     RECT  53.715 3.721 55.026 4.765 ;
     RECT  86.115 4.379 86.742 4.793 ;
     RECT  86.115 4.793 86.67 4.801 ;
     RECT  88.02 3.983 112.23 4.987 ;
     RECT  86.04 4.801 86.67 5.027 ;
     RECT  171.576 4.451 171.666 5.261 ;
     RECT  67.215 2.413 67.497 5.305 ;
     RECT  171.576 5.261 171.594 5.369 ;
     RECT  72.615 3.181 73.278 5.503 ;
     RECT  74.376 2.641 75.597 5.503 ;
     RECT  164.415 4.451 170.694 5.531 ;
     RECT  87.984 4.987 112.23 5.539 ;
     RECT  164.415 5.531 170.55 5.567 ;
     RECT  66.6 5.305 67.497 5.575 ;
     RECT  87.948 5.539 112.23 5.611 ;
     RECT  87.768 5.611 112.23 5.845 ;
     RECT  81.9 5.467 81.918 5.881 ;
     RECT  82.908 3.839 83.697 5.881 ;
     RECT  66.6 5.575 68.202 5.971 ;
     RECT  69.228 4.621 70.722 5.971 ;
     RECT  49.86 4.351 51.297 6.007 ;
     RECT  86.04 5.027 86.397 6.151 ;
     RECT  78.015 2.413 78.297 6.241 ;
     RECT  53.715 4.765 55.566 6.511 ;
     RECT  56.415 2.413 56.697 6.511 ;
     RECT  60.768 2.491 62.478 6.547 ;
     RECT  45.615 4.117 46.386 6.583 ;
     RECT  78.015 6.241 78.714 6.583 ;
     RECT  66.6 5.971 70.722 6.655 ;
     RECT  60.768 6.547 62.802 6.809 ;
     RECT  72.615 5.503 75.597 7.159 ;
     RECT  66.6 6.655 71.118 7.195 ;
     RECT  72.288 7.159 75.597 7.195 ;
     RECT  52.704 4.693 52.722 7.357 ;
     RECT  81.9 5.881 83.697 7.393 ;
     RECT  84.6 6.691 84.618 7.393 ;
     RECT  64.515 2.371 65.25 7.735 ;
     RECT  80.715 2.413 80.997 7.861 ;
     RECT  81.9 7.393 84.618 7.861 ;
     RECT  52.2 7.357 52.722 7.897 ;
     RECT  53.715 6.511 56.697 7.897 ;
     RECT  78.015 6.583 78.93 7.933 ;
     RECT  66.6 7.195 75.597 8.239 ;
     RECT  76.644 3.379 76.662 8.239 ;
     RECT  86.04 6.151 86.778 8.311 ;
     RECT  87.516 5.845 112.23 8.311 ;
     RECT  57.492 6.043 57.51 8.437 ;
     RECT  58.5 3.811 59.922 8.437 ;
     RECT  86.04 8.311 112.23 8.537 ;
     RECT  77.724 7.933 78.93 8.815 ;
     RECT  79.776 7.123 79.794 8.815 ;
     RECT  114.48 3.407 163.602 8.969 ;
     RECT  114.48 8.969 133.974 9.041 ;
     RECT  45.615 6.583 46.566 9.319 ;
     RECT  86.04 8.537 86.778 9.355 ;
     RECT  87.516 8.537 112.23 9.355 ;
     RECT  60.768 6.809 62.73 9.481 ;
     RECT  80.715 7.861 84.618 9.481 ;
     RECT  57.492 8.437 59.922 10.093 ;
     RECT  60.768 9.481 62.982 10.093 ;
     RECT  57.492 10.093 62.982 10.129 ;
     RECT  63.9 7.735 65.25 10.129 ;
     RECT  52.2 7.897 56.697 10.165 ;
     RECT  57.492 10.129 65.25 10.165 ;
     RECT  66.6 8.239 76.662 10.831 ;
     RECT  113.115 3.335 113.634 10.831 ;
     RECT  114.48 9.041 133.866 10.859 ;
     RECT  134.715 8.969 163.602 11.129 ;
     RECT  80.715 9.481 84.906 11.137 ;
     RECT  86.04 9.355 112.23 11.137 ;
     RECT  66.528 10.831 76.662 11.479 ;
     RECT  77.724 8.815 79.794 11.713 ;
     RECT  114.552 10.859 133.866 11.983 ;
     RECT  80.715 11.137 112.23 11.995 ;
     RECT  113.115 10.831 113.706 11.995 ;
     RECT  80.715 11.995 113.706 12.019 ;
     RECT  114.48 11.983 133.866 12.019 ;
     RECT  77.688 11.713 79.794 12.325 ;
     RECT  80.715 12.019 133.866 12.325 ;
     RECT  164.415 5.567 169.002 12.551 ;
     RECT  49.608 6.007 51.297 12.901 ;
     RECT  66.024 11.479 76.662 12.929 ;
     RECT  157.392 11.129 163.602 12.929 ;
     RECT  45.615 9.319 46.962 13.063 ;
     RECT  77.688 12.325 133.866 13.171 ;
     RECT  48.315 2.413 48.597 13.333 ;
     RECT  49.608 12.901 51.354 13.333 ;
     RECT  134.715 11.129 156.597 13.433 ;
     RECT  164.415 12.551 168.93 13.469 ;
     RECT  77.292 13.171 133.866 13.631 ;
     RECT  52.2 10.165 65.25 13.675 ;
     RECT  66.024 12.929 76.446 13.675 ;
     RECT  157.392 12.929 163.458 13.901 ;
     RECT  159.015 13.901 163.458 14.009 ;
     RECT  77.292 13.631 112.302 14.045 ;
     RECT  48.315 13.333 51.354 14.143 ;
     RECT  52.2 13.675 76.446 14.143 ;
     RECT  113.115 13.631 133.866 14.171 ;
     RECT  113.115 14.171 133.794 14.237 ;
     RECT  114.48 14.237 133.794 14.243 ;
     RECT  48.315 14.143 76.446 14.521 ;
     RECT  77.292 14.045 112.23 14.521 ;
     RECT  134.715 13.433 155.538 14.639 ;
     RECT  0.108 14.587 0.126 14.717 ;
     RECT  134.715 14.639 154.242 15.179 ;
     RECT  157.392 13.901 158.238 15.791 ;
     RECT  133.704 14.243 133.794 15.863 ;
     RECT  114.48 14.243 132.93 15.899 ;
     RECT  164.415 13.469 168.786 16.259 ;
     RECT  135.972 15.179 154.242 16.331 ;
     RECT  44.496 16.267 44.514 16.339 ;
     RECT  155.304 14.639 155.538 16.835 ;
     RECT  0.108 15.595 0.126 17.105 ;
     RECT  164.415 16.259 168.534 17.105 ;
     RECT  131.364 15.899 132.93 17.375 ;
     RECT  162.72 14.009 163.458 17.447 ;
     RECT  155.304 16.835 155.394 17.519 ;
     RECT  165.564 17.105 168.534 17.645 ;
     RECT  157.968 15.791 158.238 17.915 ;
     RECT  163.116 17.447 163.458 17.951 ;
     RECT  155.376 17.519 155.394 18.059 ;
     RECT  133.776 15.863 133.794 18.149 ;
     RECT  135.972 16.331 137.97 18.221 ;
     RECT  11.772 17.041 11.79 18.455 ;
     RECT  138.816 16.331 154.242 18.527 ;
     RECT  163.152 17.951 163.458 18.563 ;
     RECT  24.015 2.413 24.297 18.571 ;
     RECT  137.052 18.221 137.97 18.761 ;
     RECT  137.415 18.761 137.97 19.067 ;
     RECT  163.152 18.563 163.17 19.103 ;
     RECT  159.015 14.009 161.997 19.229 ;
     RECT  165.564 17.645 165.582 19.373 ;
     RECT  48.315 14.521 112.23 19.381 ;
     RECT  113.115 14.237 113.634 19.409 ;
     RECT  114.48 15.899 130.446 19.615 ;
     RECT  114.156 19.615 130.446 19.643 ;
     RECT  157.968 17.915 158.13 19.679 ;
     RECT  138.816 18.527 151.974 19.769 ;
     RECT  169.815 5.567 170.55 19.805 ;
     RECT  166.32 17.645 168.534 19.841 ;
     RECT  138.816 19.769 149.742 19.877 ;
     RECT  135.972 18.221 135.99 19.913 ;
     RECT  48.315 19.381 112.266 20.219 ;
     RECT  138.816 19.877 149.274 20.219 ;
     RECT  160.56 19.229 161.997 20.309 ;
     RECT  138.816 20.219 146.934 20.381 ;
     RECT  153.144 18.527 154.242 20.417 ;
     RECT  148.215 20.219 149.274 20.453 ;
     RECT  150.915 19.769 151.974 20.687 ;
     RECT  138.816 20.381 146.79 20.957 ;
     RECT  138.816 20.957 146.754 20.993 ;
     RECT  119.772 19.643 130.446 21.098 ;
     RECT  113.115 19.409 113.397 21.115 ;
     RECT  114.156 19.643 118.797 21.115 ;
     RECT  23.292 18.571 24.297 21.155 ;
     RECT  45.615 13.063 47.07 21.235 ;
     RECT  119.736 21.098 130.446 21.361 ;
     RECT  138.816 20.993 146.25 21.397 ;
     RECT  45.615 21.235 47.574 21.425 ;
     RECT  48.315 20.219 60.822 21.433 ;
     RECT  138.528 21.397 146.25 21.533 ;
     RECT  113.115 21.115 118.797 21.541 ;
     RECT  119.7 21.361 130.446 21.541 ;
     RECT  138.816 21.533 146.25 21.569 ;
     RECT  113.115 21.541 130.446 21.631 ;
     RECT  61.815 20.219 112.266 21.643 ;
     RECT  113.115 21.631 130.482 21.643 ;
     RECT  61.815 21.643 130.482 21.667 ;
     RECT  149.256 20.453 149.274 21.695 ;
     RECT  47.916 21.433 60.822 21.703 ;
     RECT  61.815 21.667 130.554 21.703 ;
     RECT  47.916 21.703 130.554 21.787 ;
     RECT  140.115 21.569 146.25 22.109 ;
     RECT  47.916 21.787 130.626 22.199 ;
     RECT  45.615 21.425 47.07 22.315 ;
     RECT  47.916 22.199 130.482 22.315 ;
     RECT  141.732 22.109 146.25 22.541 ;
     RECT  45.615 22.315 130.482 22.739 ;
     RECT  166.896 19.841 168.534 22.919 ;
     RECT  138.816 21.569 139.374 23.117 ;
     RECT  153.144 20.417 153.897 23.351 ;
     RECT  141.732 22.541 144.018 23.657 ;
     RECT  166.896 22.919 167.85 23.693 ;
     RECT  150.915 20.687 151.902 23.855 ;
     RECT  139.104 23.117 139.374 23.891 ;
     RECT  131.364 17.375 132.297 23.935 ;
     RECT  141.84 23.657 144.018 24.233 ;
     RECT  139.356 23.891 139.374 24.269 ;
     RECT  45.615 22.739 130.446 24.331 ;
     RECT  131.22 23.935 132.297 24.331 ;
     RECT  142.815 24.233 144.018 24.359 ;
     RECT  142.815 24.359 143.586 24.431 ;
     RECT  45.615 24.331 132.297 24.809 ;
     RECT  167.115 23.693 167.85 24.809 ;
     RECT  145.044 22.541 146.25 24.971 ;
     RECT  158.112 19.679 158.13 25.043 ;
     RECT  141.84 24.233 141.858 25.079 ;
     RECT  45.615 24.809 131.202 25.181 ;
     RECT  161.136 20.309 161.997 25.277 ;
     RECT  145.044 24.971 145.797 25.511 ;
     RECT  45.615 25.181 46.17 26.059 ;
     RECT  46.944 25.181 131.202 26.059 ;
     RECT  45.615 26.059 131.202 26.761 ;
     RECT  45.615 26.761 131.274 27.031 ;
     RECT  44.496 16.339 44.802 27.211 ;
     RECT  44.46 27.211 44.802 27.337 ;
     RECT  45.576 27.031 131.274 27.337 ;
     RECT  44.46 27.337 131.274 27.445 ;
     RECT  132.015 24.809 132.297 27.445 ;
     RECT  42.915 2.413 43.197 27.715 ;
     RECT  44.46 27.445 132.297 27.715 ;
     RECT  2.415 2.413 2.697 27.827 ;
     RECT  5.115 2.413 5.397 27.827 ;
     RECT  7.815 2.413 8.097 27.827 ;
     RECT  10.515 2.413 10.797 27.827 ;
     RECT  13.215 2.413 13.497 27.827 ;
     RECT  15.915 2.413 16.197 27.827 ;
     RECT  18.615 2.413 18.897 27.827 ;
     RECT  21.315 2.413 21.597 27.827 ;
     RECT  24.015 21.155 24.297 27.827 ;
     RECT  26.715 2.413 26.997 27.827 ;
     RECT  29.415 2.413 29.697 27.827 ;
     RECT  32.115 2.413 32.397 27.827 ;
     RECT  34.815 2.413 35.097 27.827 ;
     RECT  37.515 2.413 37.797 27.827 ;
     RECT  40.215 2.413 40.497 27.827 ;
     RECT  42.915 27.715 132.297 27.827 ;
     RECT  134.715 15.179 134.997 27.827 ;
     RECT  137.415 19.067 137.697 27.827 ;
     RECT  140.115 22.109 140.397 27.827 ;
     RECT  142.815 24.431 143.097 27.827 ;
     RECT  145.515 25.511 145.797 27.827 ;
     RECT  148.215 20.453 148.497 27.827 ;
     RECT  150.915 23.855 151.197 27.827 ;
     RECT  153.615 23.351 153.897 27.827 ;
     RECT  156.315 13.433 156.597 27.827 ;
     RECT  159.015 19.229 159.297 27.827 ;
     RECT  161.715 25.277 161.997 27.827 ;
     RECT  164.415 17.105 164.697 27.827 ;
     RECT  167.115 24.809 167.397 27.827 ;
     RECT  169.815 19.805 170.097 27.827 ;
     RECT  42.915 27.827 132.105 27.869 ;
     RECT  59.004 27.869 65.43 27.905 ;
     RECT  130.32 27.869 130.914 27.905 ;
     RECT  63.396 27.905 65.43 27.917 ;
     RECT  130.392 27.905 130.914 27.917 ;
     RECT  42.915 27.869 44.658 27.941 ;
     RECT  53.1 27.869 58.122 27.941 ;
     RECT  59.004 27.905 62.55 27.941 ;
     RECT  63.72 27.917 65.43 27.941 ;
     RECT  67.032 27.869 76.374 27.941 ;
     RECT  77.796 27.869 82.458 27.941 ;
     RECT  83.232 27.869 86.526 27.941 ;
     RECT  87.3 27.869 88.905 27.941 ;
     RECT  90.036 27.869 90.054 27.941 ;
     RECT  90.936 27.869 98.226 27.941 ;
     RECT  99.144 27.869 102.405 27.941 ;
     RECT  103.212 27.869 103.734 27.941 ;
     RECT  105.015 27.869 109.566 27.941 ;
     RECT  110.415 27.869 113.49 27.941 ;
     RECT  115.236 27.869 116.694 27.941 ;
     RECT  118.008 27.869 119.286 27.941 ;
     RECT  120.24 27.869 120.258 27.941 ;
     RECT  121.215 27.869 123.174 27.941 ;
     RECT  123.915 27.869 125.694 27.941 ;
     RECT  42.915 27.941 44.586 27.965 ;
     RECT  55.548 27.941 58.122 27.965 ;
     RECT  72.615 27.941 74.43 27.965 ;
     RECT  77.832 27.941 79.11 27.965 ;
     RECT  79.92 27.941 79.938 27.965 ;
     RECT  90.936 27.941 95.058 27.965 ;
     RECT  105.015 27.941 109.35 27.965 ;
     RECT  112.248 27.941 113.205 27.965 ;
     RECT  126.504 27.869 129.405 27.965 ;
     RECT  94.104 27.965 95.058 27.977 ;
     RECT  128.916 27.965 129.405 27.977 ;
     RECT  130.392 27.917 130.806 27.977 ;
     RECT  45.468 27.869 51.858 28.013 ;
     RECT  90.936 27.965 93.222 28.013 ;
     RECT  45.468 28.013 47.034 28.049 ;
     RECT  88.74 27.941 88.905 28.049 ;
     RECT  47.772 28.013 51.858 28.061 ;
     RECT  103.716 27.941 103.734 28.061 ;
     RECT  2.415 27.827 2.505 28.097 ;
     RECT  5.115 27.827 5.205 28.097 ;
     RECT  7.815 27.827 7.905 28.097 ;
     RECT  10.515 27.827 10.605 28.097 ;
     RECT  13.215 27.827 13.305 28.097 ;
     RECT  15.915 27.827 16.005 28.097 ;
     RECT  18.615 27.827 18.705 28.097 ;
     RECT  21.315 27.827 21.405 28.097 ;
     RECT  24.015 27.827 24.105 28.097 ;
     RECT  26.715 27.827 26.805 28.097 ;
     RECT  29.415 27.827 29.505 28.097 ;
     RECT  32.115 27.827 32.205 28.097 ;
     RECT  34.815 27.827 34.905 28.097 ;
     RECT  37.515 27.827 37.605 28.097 ;
     RECT  40.215 27.827 40.305 28.097 ;
     RECT  42.915 27.965 43.005 28.097 ;
     RECT  45.615 28.049 47.034 28.097 ;
     RECT  47.772 28.061 49.662 28.097 ;
     RECT  50.616 28.061 51.858 28.097 ;
     RECT  55.548 27.965 56.934 28.097 ;
     RECT  59.004 27.941 59.85 28.097 ;
     RECT  61.128 27.941 62.55 28.097 ;
     RECT  64.515 27.941 64.962 28.097 ;
     RECT  67.032 27.941 70.005 28.097 ;
     RECT  72.615 27.965 73.998 28.097 ;
     RECT  75.315 27.941 76.374 28.097 ;
     RECT  77.832 27.965 78.105 28.097 ;
     RECT  80.715 27.941 81.414 28.097 ;
     RECT  83.232 27.941 83.505 28.097 ;
     RECT  85.212 27.941 86.526 28.097 ;
     RECT  88.815 28.049 88.905 28.097 ;
     RECT  94.215 27.977 95.058 28.097 ;
     RECT  99.144 27.941 100.566 28.097 ;
     RECT  101.916 27.941 102.405 28.097 ;
     RECT  105.015 27.965 105.606 28.097 ;
     RECT  107.532 27.965 109.35 28.097 ;
     RECT  110.415 27.941 111.114 28.097 ;
     RECT  112.608 27.965 113.205 28.097 ;
     RECT  115.815 27.941 116.694 28.097 ;
     RECT  118.515 27.941 119.286 28.097 ;
     RECT  121.215 27.941 121.95 28.097 ;
     RECT  123.915 27.941 124.794 28.097 ;
     RECT  128.952 27.977 129.405 28.097 ;
     RECT  132.015 27.869 132.105 28.097 ;
     RECT  134.715 27.827 134.805 28.097 ;
     RECT  137.415 27.827 137.505 28.097 ;
     RECT  140.115 27.827 140.205 28.097 ;
     RECT  142.815 27.827 142.905 28.097 ;
     RECT  145.515 27.827 145.605 28.097 ;
     RECT  148.215 27.827 148.305 28.097 ;
     RECT  150.915 27.827 151.005 28.097 ;
     RECT  153.615 27.827 153.705 28.097 ;
     RECT  156.315 27.827 156.405 28.097 ;
     RECT  159.015 27.827 159.105 28.097 ;
     RECT  161.715 27.827 161.805 28.097 ;
     RECT  164.415 27.827 164.505 28.097 ;
     RECT  167.115 27.827 167.205 28.097 ;
     RECT  169.815 27.827 169.905 28.097 ;
     RECT  61.128 28.097 61.65 28.205 ;
     RECT  56.844 28.097 56.934 28.253 ;
     RECT  67.032 28.097 69.39 28.253 ;
     RECT  105.336 28.097 105.606 28.253 ;
     RECT  130.464 27.977 130.806 28.253 ;
     RECT  130.608 28.253 130.806 28.301 ;
     RECT  128.952 28.097 129.258 28.397 ;
     RECT  130.788 28.301 130.806 28.397 ;
     RECT  64.908 28.097 64.962 28.445 ;
     RECT  126.504 27.965 128.034 28.445 ;
     RECT  129.132 28.397 129.258 28.445 ;
     RECT  43.812 27.965 44.55 28.493 ;
     RECT  47.772 28.097 48.294 28.493 ;
     RECT  50.616 28.097 50.886 28.493 ;
     RECT  62.532 28.097 62.55 28.493 ;
     RECT  105.588 28.253 105.606 28.493 ;
     RECT  106.596 27.965 106.614 28.493 ;
     RECT  126.504 28.445 126.99 28.493 ;
     RECT  129.24 28.445 129.258 28.493 ;
     RECT  50.76 28.493 50.886 28.541 ;
     RECT  51.696 28.097 51.858 28.541 ;
     RECT  53.388 27.941 54.666 28.541 ;
     RECT  59.004 28.097 59.022 28.541 ;
     RECT  64.908 28.445 64.926 28.541 ;
     RECT  71.136 27.941 71.154 28.541 ;
     RECT  73.296 28.097 73.998 28.541 ;
     RECT  75.672 28.097 76.374 28.541 ;
     RECT  77.832 28.097 77.85 28.541 ;
     RECT  81.144 28.097 81.414 28.541 ;
     RECT  83.232 28.097 83.25 28.541 ;
     RECT  85.212 28.097 85.59 28.541 ;
     RECT  86.508 28.097 86.526 28.541 ;
     RECT  87.768 27.941 87.786 28.541 ;
     RECT  91.368 28.013 93.222 28.541 ;
     RECT  99.144 28.097 99.162 28.541 ;
     RECT  100.044 28.097 100.566 28.541 ;
     RECT  101.916 28.097 102.258 28.541 ;
     RECT  108.396 28.097 109.35 28.541 ;
     RECT  111.096 28.097 111.114 28.541 ;
     RECT  114.3 27.869 114.318 28.541 ;
     RECT  116.604 28.097 116.694 28.541 ;
     RECT  119.052 28.097 119.286 28.541 ;
     RECT  121.608 28.097 121.95 28.541 ;
     RECT  122.688 27.941 122.706 28.541 ;
     RECT  124.596 28.097 124.794 28.541 ;
     RECT  56.916 28.253 56.934 28.589 ;
     RECT  81.396 28.541 81.414 28.589 ;
     RECT  96.048 27.941 97.938 28.589 ;
     RECT  109.332 28.541 109.35 28.589 ;
     RECT  91.368 28.541 93.186 28.637 ;
     RECT  108.396 28.541 108.414 28.829 ;
     RECT  126.972 28.493 126.99 28.829 ;
     RECT  107.532 28.097 107.586 29.029 ;
     RECT  102.132 28.541 102.258 29.057 ;
     RECT  107.46 29.029 107.586 29.057 ;
     RECT  49.104 28.097 49.662 29.069 ;
     RECT  51.768 28.541 51.858 29.069 ;
     RECT  53.388 28.541 53.658 29.069 ;
     RECT  55.548 28.097 55.998 29.069 ;
     RECT  58.068 27.965 58.122 29.069 ;
     RECT  63.72 27.941 63.738 29.069 ;
     RECT  67.032 28.253 67.05 29.069 ;
     RECT  68.364 28.253 69.39 29.069 ;
     RECT  79.092 27.965 79.11 29.069 ;
     RECT  82.44 27.941 82.458 29.069 ;
     RECT  85.212 28.541 85.23 29.069 ;
     RECT  97.272 28.589 97.938 29.069 ;
     RECT  107.46 29.057 107.55 29.069 ;
     RECT  124.776 28.541 124.794 29.069 ;
     RECT  50.868 28.541 50.886 29.117 ;
     RECT  94.392 28.097 95.058 29.117 ;
     RECT  107.46 29.069 107.478 29.117 ;
     RECT  49.104 29.069 49.302 29.165 ;
     RECT  49.284 29.165 49.302 29.213 ;
     RECT  53.388 29.069 53.406 29.645 ;
     RECT  55.548 29.069 55.566 29.645 ;
     RECT  59.832 28.097 59.85 29.645 ;
     RECT  61.128 28.205 61.146 29.645 ;
     RECT  91.368 28.637 92.61 29.645 ;
     RECT  96.048 28.589 96.066 29.645 ;
     RECT  112.608 28.097 112.914 29.645 ;
     RECT  45.756 28.097 47.034 29.693 ;
     RECT  51.84 29.069 51.858 29.693 ;
     RECT  91.872 29.645 92.61 29.693 ;
     RECT  102.132 29.057 102.15 29.693 ;
     RECT  112.896 29.645 112.914 29.693 ;
     RECT  125.676 27.941 125.694 29.693 ;
     RECT  116.676 28.541 116.694 29.851 ;
     RECT  46.872 29.693 47.034 29.885 ;
     RECT  92.124 29.693 92.61 30.077 ;
     RECT  45.756 29.693 45.774 30.125 ;
     RECT  47.016 29.885 47.034 30.125 ;
     RECT  58.104 29.069 58.122 30.125 ;
     RECT  73.296 28.541 73.314 30.125 ;
     RECT  75.672 28.541 75.69 30.125 ;
     RECT  92.124 30.077 92.466 30.125 ;
     RECT  95.04 29.117 95.058 30.125 ;
     RECT  97.272 29.069 97.29 30.125 ;
     RECT  116.244 29.851 116.694 30.125 ;
     RECT  128.016 28.445 128.034 30.125 ;
    LAYER M4 ;
     RECT  0.097 14.592 0.137 15.624 ;
     RECT  0.137 14.688 2.408 14.712 ;
     RECT  2.408 2.148 2.512 28.092 ;
     RECT  2.512 2.418 2.704 27.822 ;
     RECT  2.704 14.688 5.108 14.712 ;
     RECT  5.108 2.148 5.212 28.092 ;
     RECT  5.212 2.418 5.404 27.822 ;
     RECT  5.404 14.688 7.808 14.712 ;
     RECT  7.808 2.148 7.912 28.092 ;
     RECT  7.912 2.418 8.104 27.822 ;
     RECT  8.104 14.688 10.508 14.712 ;
     RECT  10.508 2.148 10.612 28.092 ;
     RECT  10.612 2.418 10.804 27.822 ;
     RECT  10.804 14.688 13.208 14.712 ;
     RECT  13.208 2.148 13.312 28.092 ;
     RECT  13.312 2.418 13.504 27.822 ;
     RECT  13.504 14.688 15.908 14.712 ;
     RECT  15.908 2.148 16.012 28.092 ;
     RECT  16.012 2.418 16.204 27.822 ;
     RECT  16.204 14.688 18.608 14.712 ;
     RECT  18.608 2.148 18.712 28.092 ;
     RECT  18.712 2.418 18.904 27.822 ;
     RECT  18.904 14.688 21.308 14.712 ;
     RECT  21.308 2.148 21.412 28.092 ;
     RECT  21.412 2.418 21.604 27.822 ;
     RECT  21.604 14.688 24.008 14.712 ;
     RECT  24.008 2.148 24.112 28.092 ;
     RECT  24.112 2.418 24.304 27.822 ;
     RECT  24.304 14.688 26.708 14.712 ;
     RECT  26.708 2.148 26.812 28.092 ;
     RECT  26.812 2.418 27.004 27.822 ;
     RECT  27.004 14.688 29.408 14.712 ;
     RECT  29.408 2.148 29.512 28.092 ;
     RECT  29.512 2.418 29.704 27.822 ;
     RECT  29.704 14.688 32.108 14.712 ;
     RECT  32.108 2.148 32.212 28.092 ;
     RECT  32.212 2.418 32.404 27.822 ;
     RECT  32.404 14.688 34.808 14.712 ;
     RECT  34.808 2.148 34.912 28.092 ;
     RECT  34.912 2.418 35.104 27.822 ;
     RECT  35.104 14.688 37.508 14.712 ;
     RECT  37.508 2.148 37.612 28.092 ;
     RECT  37.612 2.418 37.804 27.822 ;
     RECT  37.804 14.688 40.208 14.712 ;
     RECT  40.208 2.148 40.312 28.092 ;
     RECT  40.312 2.418 40.504 27.822 ;
     RECT  40.504 14.688 42.908 14.712 ;
     RECT  42.908 2.148 43.012 28.092 ;
     RECT  43.012 2.418 43.204 28.092 ;
     RECT  43.204 27.936 43.717 28.092 ;
     RECT  43.717 27.936 44.867 28.488 ;
     RECT  43.204 14.688 45.608 14.712 ;
     RECT  44.867 27.936 45.608 28.092 ;
     RECT  45.608 2.148 45.712 28.092 ;
     RECT  45.712 2.418 45.904 27.822 ;
     RECT  45.853 29.04 46.105 29.064 ;
     RECT  45.745 30.096 46.105 30.12 ;
     RECT  46.105 29.04 46.547 30.12 ;
     RECT  46.547 29.664 46.691 30.12 ;
     RECT  45.904 24.096 46.892 24.12 ;
     RECT  46.691 29.856 46.901 30.12 ;
     RECT  46.892 23.52 46.933 24.12 ;
     RECT  45.904 27.552 47.036 27.72 ;
     RECT  46.933 23.04 47.041 24.12 ;
     RECT  45.904 25.152 47.041 25.176 ;
     RECT  46.901 30.096 47.045 30.12 ;
     RECT  47.036 27.36 47.18 27.72 ;
     RECT  47.18 27.36 47.266 27.96 ;
     RECT  47.266 27.36 47.509 28.008 ;
     RECT  47.941 21.936 48.121 21.96 ;
     RECT  47.509 27.36 48.305 28.488 ;
     RECT  45.904 14.688 48.308 14.712 ;
     RECT  48.121 21.744 48.308 21.96 ;
     RECT  47.041 23.04 48.308 25.176 ;
     RECT  48.305 27.36 48.308 28.092 ;
     RECT  48.308 2.148 48.412 28.092 ;
     RECT  48.412 2.418 48.604 27.822 ;
     RECT  48.604 21.744 49.169 23.064 ;
     RECT  49.093 29.088 49.273 29.16 ;
     RECT  49.169 21.744 49.385 21.96 ;
     RECT  49.273 29.088 49.589 29.208 ;
     RECT  48.604 26.736 49.811 26.76 ;
     RECT  49.381 27.936 50.053 27.96 ;
     RECT  49.589 29.04 50.243 29.208 ;
     RECT  49.993 24.432 50.245 24.456 ;
     RECT  49.385 21.936 50.353 21.96 ;
     RECT  49.169 23.04 50.353 23.064 ;
     RECT  50.053 27.936 50.605 28.056 ;
     RECT  50.243 29.04 50.605 29.112 ;
     RECT  50.605 26.16 50.869 26.328 ;
     RECT  50.353 21.936 50.965 23.064 ;
     RECT  50.245 24.432 50.965 25.032 ;
     RECT  48.604 14.688 51.008 14.712 ;
     RECT  50.965 21.936 51.008 25.032 ;
     RECT  50.869 26.112 51.008 26.328 ;
     RECT  50.605 27.936 51.008 29.112 ;
     RECT  51.008 2.148 51.112 29.112 ;
     RECT  51.112 2.418 51.304 29.112 ;
     RECT  51.304 23.904 51.365 29.112 ;
     RECT  51.365 25.68 51.725 29.112 ;
     RECT  51.725 29.04 51.781 29.112 ;
     RECT  51.781 29.04 51.797 29.688 ;
     RECT  51.725 25.68 51.869 27.864 ;
     RECT  51.797 29.664 51.869 29.688 ;
     RECT  51.365 23.904 52.433 24.456 ;
     RECT  51.869 25.68 52.499 27.384 ;
     RECT  51.304 21.648 53.053 22.488 ;
     RECT  52.433 23.904 53.053 24.504 ;
     RECT  53.221 29.616 53.413 29.64 ;
     RECT  52.499 25.68 53.557 26.952 ;
     RECT  53.413 29.616 53.629 30.072 ;
     RECT  51.304 14.688 53.708 14.712 ;
     RECT  53.053 21.648 53.708 24.504 ;
     RECT  53.557 25.488 53.708 26.952 ;
     RECT  53.629 29.04 53.708 30.072 ;
     RECT  53.708 2.148 53.713 30.072 ;
     RECT  53.713 2.148 53.812 28.536 ;
     RECT  53.713 29.952 53.843 30.072 ;
     RECT  53.812 2.418 54.004 28.536 ;
     RECT  54.004 21.072 54.179 28.536 ;
     RECT  54.179 21.072 54.227 27.384 ;
     RECT  54.227 23.088 54.275 27.384 ;
     RECT  54.275 23.088 54.461 26.856 ;
     RECT  54.179 28.512 54.677 28.536 ;
     RECT  54.227 21.072 54.713 21.96 ;
     RECT  54.461 23.328 55.187 26.856 ;
     RECT  54.805 29.04 55.381 29.064 ;
     RECT  53.843 30.048 55.381 30.072 ;
     RECT  55.187 23.328 55.397 24.6 ;
     RECT  55.397 23.328 55.477 24.552 ;
     RECT  54.713 21.936 55.717 21.96 ;
     RECT  55.187 25.632 55.861 26.856 ;
     RECT  55.141 27.84 55.861 27.864 ;
     RECT  55.381 29.04 56.009 30.072 ;
     RECT  54.004 14.688 56.408 14.712 ;
     RECT  55.717 21.648 56.408 21.96 ;
     RECT  55.477 22.992 56.408 24.552 ;
     RECT  55.861 25.632 56.408 27.864 ;
     RECT  56.009 29.952 56.435 30.072 ;
     RECT  56.408 2.148 56.512 28.584 ;
     RECT  56.512 2.418 56.704 28.584 ;
     RECT  56.704 21.936 56.945 28.584 ;
     RECT  56.945 21.936 57.491 27.96 ;
     RECT  57.491 21.936 57.521 26.328 ;
     RECT  57.491 27.36 57.587 27.96 ;
     RECT  56.435 30.048 57.973 30.072 ;
     RECT  57.829 29.04 58.117 29.064 ;
     RECT  57.973 30.048 58.117 30.12 ;
     RECT  58.117 29.04 58.133 30.12 ;
     RECT  57.521 21.936 58.22 26.232 ;
     RECT  58.22 21.648 58.261 26.232 ;
     RECT  58.261 21.408 58.597 26.232 ;
     RECT  57.587 27.36 58.597 27.384 ;
     RECT  58.133 29.04 58.837 30.072 ;
     RECT  58.837 28.512 59.027 30.072 ;
     RECT  59.027 28.512 59.033 28.536 ;
     RECT  56.704 14.688 59.108 14.712 ;
     RECT  58.597 21.408 59.108 27.384 ;
     RECT  59.108 2.148 59.212 28.092 ;
     RECT  59.212 2.418 59.404 27.822 ;
     RECT  59.027 29.616 59.861 30.072 ;
     RECT  59.404 21.408 60.005 27.384 ;
     RECT  60.005 21.984 60.709 27.384 ;
     RECT  59.861 30.048 60.997 30.072 ;
     RECT  60.997 29.616 61.157 30.072 ;
     RECT  60.709 21.984 61.621 27.912 ;
     RECT  59.404 14.688 61.808 14.712 ;
     RECT  61.621 21.984 61.808 28.2 ;
     RECT  61.808 2.148 61.912 28.2 ;
     RECT  61.157 29.952 62.051 30.072 ;
     RECT  61.912 2.418 62.104 28.2 ;
     RECT  62.104 21.648 62.237 22.248 ;
     RECT  62.104 23.28 62.243 28.2 ;
     RECT  62.051 30.048 62.291 30.072 ;
     RECT  62.243 27.84 62.437 28.2 ;
     RECT  62.437 27.84 62.561 28.488 ;
     RECT  62.243 23.28 62.627 26.856 ;
     RECT  62.237 21.648 62.677 22.008 ;
     RECT  62.581 29.04 62.723 29.064 ;
     RECT  62.561 27.84 63.065 27.912 ;
     RECT  62.627 23.28 63.277 26.52 ;
     RECT  63.065 27.888 63.425 27.912 ;
     RECT  62.677 21.792 63.493 22.008 ;
     RECT  63.277 23.136 63.493 26.52 ;
     RECT  63.709 29.04 63.793 29.064 ;
     RECT  63.493 21.792 64.357 26.52 ;
     RECT  62.104 2.496 64.508 2.52 ;
     RECT  62.104 14.688 64.508 14.712 ;
     RECT  64.357 21.792 64.508 27.384 ;
     RECT  64.453 28.512 64.508 28.536 ;
     RECT  64.508 2.148 64.612 28.536 ;
     RECT  64.597 29.856 64.741 29.88 ;
     RECT  64.741 29.856 64.789 29.976 ;
     RECT  64.612 2.418 64.804 28.536 ;
     RECT  64.789 29.856 64.931 30.072 ;
     RECT  64.804 28.416 64.937 28.536 ;
     RECT  64.937 28.416 64.973 28.44 ;
     RECT  64.931 29.952 64.979 29.976 ;
     RECT  64.804 21.984 65.027 27.432 ;
     RECT  65.027 21.984 65.405 26.856 ;
     RECT  66.469 30.048 66.517 30.072 ;
     RECT  65.405 23.136 66.613 26.856 ;
     RECT  66.517 29.952 66.659 30.072 ;
     RECT  65.405 21.984 67.129 22.008 ;
     RECT  66.613 23.136 67.129 27.432 ;
     RECT  64.804 2.496 67.208 2.52 ;
     RECT  64.804 14.688 67.208 14.712 ;
     RECT  67.129 21.984 67.208 27.432 ;
     RECT  67.021 29.04 67.208 29.064 ;
     RECT  67.208 2.148 67.235 29.064 ;
     RECT  67.235 2.148 67.312 28.248 ;
     RECT  67.312 2.418 67.504 28.248 ;
     RECT  67.504 21.648 67.709 28.248 ;
     RECT  66.659 30.048 68.387 30.072 ;
     RECT  67.709 21.648 68.537 27.432 ;
     RECT  68.197 29.04 69.401 29.064 ;
     RECT  69.685 30.048 69.733 30.072 ;
     RECT  67.504 2.496 69.908 2.52 ;
     RECT  67.504 14.688 69.908 14.712 ;
     RECT  68.537 21.696 69.908 27.432 ;
     RECT  69.908 2.148 70.012 28.092 ;
     RECT  70.012 2.418 70.204 27.822 ;
     RECT  69.733 29.76 70.501 30.072 ;
     RECT  70.501 29.664 70.691 30.072 ;
     RECT  70.204 21.696 71.021 27.432 ;
     RECT  70.204 14.688 71.201 14.856 ;
     RECT  71.125 28.512 71.267 28.536 ;
     RECT  71.021 21.696 71.749 26.808 ;
     RECT  71.749 21.648 71.881 26.808 ;
     RECT  71.881 21.408 72.469 26.808 ;
     RECT  72.037 30.048 72.469 30.072 ;
     RECT  70.204 2.496 72.608 2.52 ;
     RECT  71.201 14.688 72.608 14.712 ;
     RECT  72.469 21.408 72.608 26.856 ;
     RECT  72.325 28.176 72.608 28.2 ;
     RECT  72.469 29.952 72.707 30.072 ;
     RECT  72.608 2.148 72.712 28.2 ;
     RECT  72.712 2.418 72.851 28.2 ;
     RECT  72.851 2.418 72.904 27.822 ;
     RECT  72.904 21.408 73.081 27.384 ;
     RECT  72.707 30.048 73.237 30.072 ;
     RECT  73.237 30.048 73.325 30.12 ;
     RECT  73.325 30.048 73.811 30.072 ;
     RECT  73.813 28.512 74.009 28.536 ;
     RECT  73.081 21.408 74.077 26.952 ;
     RECT  74.077 21.408 74.245 27.384 ;
     RECT  72.904 2.496 75.308 2.52 ;
     RECT  72.904 14.688 75.308 14.712 ;
     RECT  75.229 20.112 75.308 20.136 ;
     RECT  74.245 21.408 75.308 27.96 ;
     RECT  75.013 30.048 75.397 30.072 ;
     RECT  75.308 2.148 75.412 28.092 ;
     RECT  75.397 30 75.541 30.072 ;
     RECT  75.412 2.418 75.589 28.092 ;
     RECT  75.589 2.418 75.604 28.2 ;
     RECT  75.541 29.616 75.661 30.072 ;
     RECT  75.661 29.616 75.701 30.12 ;
     RECT  75.701 30 75.731 30.12 ;
     RECT  75.731 30.048 75.745 30.12 ;
     RECT  75.604 21.408 75.779 28.2 ;
     RECT  75.604 20.112 75.827 20.328 ;
     RECT  75.779 21.408 75.923 27.528 ;
     RECT  75.923 21.408 75.971 27.432 ;
     RECT  76.261 28.512 76.385 28.536 ;
     RECT  75.971 27.408 76.643 27.432 ;
     RECT  75.971 21.408 77.125 26.184 ;
     RECT  77.125 21.408 77.245 26.232 ;
     RECT  77.557 28.512 77.861 28.536 ;
     RECT  75.604 2.496 78.008 2.52 ;
     RECT  75.604 14.688 78.008 14.712 ;
     RECT  75.827 20.112 78.008 20.136 ;
     RECT  77.245 21.408 78.008 26.808 ;
     RECT  78.008 2.148 78.112 28.092 ;
     RECT  75.745 30.048 78.277 30.072 ;
     RECT  78.112 2.418 78.304 27.96 ;
     RECT  78.277 30 78.419 30.072 ;
     RECT  78.419 30.048 78.515 30.072 ;
     RECT  78.304 20.112 78.796 27.96 ;
     RECT  78.796 20.112 78.941 27.384 ;
     RECT  78.941 21.408 78.949 27.384 ;
     RECT  78.997 29.04 79.121 29.064 ;
     RECT  78.949 21.408 79.139 26.856 ;
     RECT  79.139 21.408 79.381 26.808 ;
     RECT  79.861 27.936 80.341 27.96 ;
     RECT  80.341 27.936 80.437 28.344 ;
     RECT  80.197 30.048 80.485 30.072 ;
     RECT  80.437 27.936 80.581 28.968 ;
     RECT  80.485 30 80.581 30.072 ;
     RECT  78.304 2.496 80.708 2.52 ;
     RECT  78.304 14.688 80.708 14.712 ;
     RECT  78.941 20.112 80.708 20.136 ;
     RECT  79.381 21.408 80.708 26.76 ;
     RECT  80.581 27.936 80.708 30.072 ;
     RECT  80.708 2.148 80.723 30.072 ;
     RECT  80.723 30 80.771 30.072 ;
     RECT  80.723 2.148 80.812 28.584 ;
     RECT  80.771 30 80.915 30.024 ;
     RECT  80.812 2.418 81.004 28.584 ;
     RECT  81.004 28.512 81.173 28.584 ;
     RECT  81.173 28.56 81.425 28.584 ;
     RECT  81.004 21.12 81.965 26.76 ;
     RECT  81.965 21.408 82.213 26.76 ;
     RECT  82.309 28.944 82.429 28.968 ;
     RECT  82.429 28.944 82.513 29.064 ;
     RECT  82.213 21.408 83.029 26.808 ;
     RECT  81.004 2.496 83.408 2.52 ;
     RECT  81.004 14.688 83.408 14.712 ;
     RECT  81.004 20.112 83.408 20.136 ;
     RECT  83.029 21.408 83.408 26.856 ;
     RECT  83.221 28.512 83.408 28.536 ;
     RECT  83.029 30.048 83.507 30.072 ;
     RECT  83.408 2.148 83.512 28.536 ;
     RECT  83.512 2.418 83.704 28.536 ;
     RECT  83.704 21.408 83.893 28.536 ;
     RECT  83.893 21.408 83.939 29.064 ;
     RECT  83.939 29.04 84.035 29.064 ;
     RECT  83.939 21.408 84.881 27.48 ;
     RECT  85.157 29.04 85.241 29.064 ;
     RECT  83.704 2.496 86.108 2.52 ;
     RECT  83.704 14.688 86.108 14.712 ;
     RECT  83.704 20.112 86.108 20.136 ;
     RECT  84.881 21.648 86.108 27.48 ;
     RECT  85.477 28.512 86.108 28.536 ;
     RECT  86.108 2.148 86.212 28.536 ;
     RECT  85.621 30.048 86.341 30.072 ;
     RECT  86.212 2.418 86.404 28.536 ;
     RECT  86.404 28.512 86.485 28.536 ;
     RECT  86.341 29.808 86.485 30.072 ;
     RECT  86.485 28.512 86.723 30.072 ;
     RECT  86.404 8.496 86.825 8.52 ;
     RECT  86.404 21.696 86.861 27.384 ;
     RECT  86.723 30 87.107 30.072 ;
     RECT  86.861 21.696 87.203 26.856 ;
     RECT  86.404 2.496 87.685 2.52 ;
     RECT  87.505 3.936 87.685 3.96 ;
     RECT  86.723 28.512 87.797 28.536 ;
     RECT  87.685 2.496 87.829 3.96 ;
     RECT  87.749 0.576 87.833 0.6 ;
     RECT  87.203 21.696 87.833 26.808 ;
     RECT  87.829 1.776 87.925 3.96 ;
     RECT  87.925 1.728 88.081 3.96 ;
     RECT  87.973 4.992 88.081 5.016 ;
     RECT  88.081 1.728 88.405 5.016 ;
     RECT  88.501 29.04 88.739 29.064 ;
     RECT  88.405 1.68 88.808 5.016 ;
     RECT  86.404 14.688 88.808 14.712 ;
     RECT  86.404 20.112 88.808 20.136 ;
     RECT  87.833 21.696 88.808 26.616 ;
     RECT  88.808 1.68 88.912 28.092 ;
     RECT  87.107 30.048 89.077 30.072 ;
     RECT  88.912 1.68 89.104 27.822 ;
     RECT  89.077 30 89.219 30.072 ;
     RECT  89.219 30.048 89.363 30.072 ;
     RECT  89.104 21.264 89.381 27.336 ;
     RECT  89.104 1.68 89.468 5.688 ;
     RECT  89.468 1.104 89.555 5.688 ;
     RECT  89.104 19.536 89.555 20.136 ;
     RECT  89.104 14.688 89.705 14.808 ;
     RECT  89.381 21.264 89.813 26.28 ;
     RECT  89.555 1.728 89.884 5.688 ;
     RECT  89.813 21.264 89.921 26.232 ;
     RECT  89.705 14.784 90.001 14.808 ;
     RECT  89.921 21.264 90.065 25.8 ;
     RECT  90.065 21.264 90.209 24.84 ;
     RECT  90.133 6.816 90.461 6.84 ;
     RECT  89.381 27.264 90.901 27.336 ;
     RECT  90.901 27.264 90.925 27.96 ;
     RECT  89.884 2.496 91.045 5.688 ;
     RECT  90.901 0.096 91.109 0.12 ;
     RECT  91.045 1.728 91.145 5.688 ;
     RECT  90.209 21.648 91.189 24.84 ;
     RECT  91.189 21.648 91.285 25.752 ;
     RECT  90.925 27.264 91.285 28.008 ;
     RECT  91.285 30.048 91.313 30.072 ;
     RECT  91.285 21.648 91.381 28.008 ;
     RECT  91.313 29.616 91.397 30.072 ;
     RECT  91.145 2.148 91.508 5.688 ;
     RECT  91.033 10.464 91.508 10.488 ;
     RECT  89.555 19.536 91.508 19.56 ;
     RECT  91.381 21.12 91.508 28.008 ;
     RECT  91.508 2.148 91.612 28.092 ;
     RECT  91.612 2.148 91.804 27.822 ;
     RECT  91.804 3.6 91.865 5.016 ;
     RECT  91.397 29.664 91.901 30.072 ;
     RECT  91.804 21.12 92.045 27.336 ;
     RECT  91.901 30.048 92.053 30.072 ;
     RECT  91.865 3.696 92.081 5.016 ;
     RECT  92.149 0.576 92.221 0.6 ;
     RECT  92.221 0.096 92.233 0.6 ;
     RECT  91.804 2.148 92.293 2.52 ;
     RECT  92.081 3.84 92.297 3.864 ;
     RECT  92.053 30.048 92.477 30.12 ;
     RECT  92.081 4.992 92.549 5.016 ;
     RECT  92.477 30.048 92.621 30.072 ;
     RECT  92.917 28.512 93.061 28.536 ;
     RECT  93.061 27.936 93.157 28.536 ;
     RECT  93.157 27.936 93.251 28.632 ;
     RECT  92.233 0.096 93.635 0.12 ;
     RECT  92.045 21.12 93.973 26.76 ;
     RECT  93.251 27.936 93.973 28.344 ;
     RECT  93.637 30.048 94.067 30.072 ;
     RECT  92.293 1.728 94.069 2.52 ;
     RECT  94.069 1.728 94.208 2.808 ;
     RECT  91.804 19.536 94.208 19.56 ;
     RECT  93.973 21.12 94.208 28.344 ;
     RECT  94.208 1.728 94.357 28.344 ;
     RECT  94.357 1.728 94.444 29.112 ;
     RECT  94.444 1.728 94.504 28.344 ;
     RECT  94.504 21.12 94.601 28.344 ;
     RECT  94.601 21.12 94.637 28.2 ;
     RECT  94.504 1.728 94.661 2.904 ;
     RECT  94.597 0.144 94.739 0.168 ;
     RECT  94.661 1.152 94.745 2.904 ;
     RECT  94.645 30.096 95.069 30.12 ;
     RECT  94.745 1.728 95.597 2.904 ;
     RECT  95.941 29.616 96.077 29.64 ;
     RECT  95.597 1.728 96.289 2.952 ;
     RECT  96.373 28.512 96.517 28.536 ;
     RECT  96.517 28.512 96.797 28.584 ;
     RECT  96.797 28.512 96.851 28.536 ;
     RECT  96.289 1.728 96.901 3.048 ;
     RECT  96.901 1.728 96.908 3.144 ;
     RECT  94.504 19.536 96.908 19.56 ;
     RECT  94.637 21.12 96.908 27.384 ;
     RECT  96.085 30.048 96.949 30.072 ;
     RECT  96.908 1.728 97.012 28.092 ;
     RECT  96.949 30.048 97.093 30.12 ;
     RECT  97.012 1.728 97.204 27.822 ;
     RECT  97.204 1.728 97.301 3.336 ;
     RECT  97.093 29.808 97.301 30.12 ;
     RECT  97.301 29.808 97.427 30.072 ;
     RECT  97.301 1.728 97.517 3.144 ;
     RECT  97.813 29.04 97.949 29.064 ;
     RECT  97.517 1.728 98.485 2.904 ;
     RECT  98.485 1.728 98.569 3.096 ;
     RECT  97.204 21.12 99.241 27.48 ;
     RECT  98.677 28.512 99.241 28.536 ;
     RECT  98.437 30.048 99.493 30.072 ;
     RECT  98.569 1.728 99.608 3.048 ;
     RECT  97.204 19.536 99.608 19.56 ;
     RECT  99.241 21.12 99.608 28.536 ;
     RECT  99.397 0.144 99.683 0.168 ;
     RECT  99.493 29.952 99.731 30.072 ;
     RECT  99.608 1.728 99.781 28.536 ;
     RECT  99.781 1.68 99.904 28.536 ;
     RECT  99.904 1.68 99.965 3.048 ;
     RECT  100.285 0.528 100.403 0.552 ;
     RECT  99.904 28.512 100.595 28.536 ;
     RECT  99.904 21.12 100.685 26.856 ;
     RECT  100.685 21.216 100.961 26.856 ;
     RECT  100.961 21.216 101.045 27.384 ;
     RECT  99.965 1.728 101.221 3.048 ;
     RECT  101.269 28.944 101.317 28.968 ;
     RECT  101.221 1.728 101.365 3.096 ;
     RECT  101.317 28.944 101.459 29.064 ;
     RECT  101.045 21.216 102.037 26.856 ;
     RECT  99.731 30.048 102.085 30.072 ;
     RECT  99.904 19.536 102.149 19.56 ;
     RECT  102.133 0.144 102.275 0.168 ;
     RECT  101.365 1.728 102.308 3.384 ;
     RECT  102.149 19.536 102.308 19.944 ;
     RECT  102.037 21.216 102.308 26.952 ;
     RECT  101.905 28.512 102.308 28.536 ;
     RECT  102.308 1.728 102.412 28.536 ;
     RECT  102.412 1.728 102.604 27.822 ;
     RECT  102.604 19.872 102.665 19.896 ;
     RECT  102.604 21.12 102.737 27.384 ;
     RECT  102.085 29.568 102.805 30.072 ;
     RECT  102.805 29.04 102.995 30.072 ;
     RECT  102.995 29.856 103.187 30.072 ;
     RECT  102.604 1.728 103.205 3.144 ;
     RECT  102.737 21.168 103.523 27.384 ;
     RECT  103.523 27.312 103.573 27.384 ;
     RECT  103.573 27.312 103.745 28.056 ;
     RECT  103.813 6.816 103.925 6.84 ;
     RECT  103.205 1.728 104.245 2.904 ;
     RECT  103.523 21.168 104.813 26.232 ;
     RECT  103.745 27.312 104.813 27.336 ;
     RECT  104.245 1.728 104.821 2.952 ;
     RECT  104.813 21.168 104.893 27.336 ;
     RECT  104.821 1.728 105.008 3.336 ;
     RECT  104.893 21.12 105.008 27.336 ;
     RECT  105.008 1.728 105.013 28.092 ;
     RECT  105.253 0.336 105.301 0.36 ;
     RECT  105.013 1.728 105.301 28.248 ;
     RECT  105.301 1.728 105.304 28.488 ;
     RECT  105.301 0.24 105.443 0.36 ;
     RECT  105.304 1.728 105.617 3.576 ;
     RECT  105.304 21.12 105.617 28.488 ;
     RECT  105.617 21.12 106.049 27.96 ;
     RECT  105.617 3.552 106.085 3.576 ;
     RECT  106.049 21.648 106.307 27.96 ;
     RECT  103.187 30.048 106.403 30.072 ;
     RECT  106.307 27.936 106.585 27.96 ;
     RECT  106.585 27.936 106.669 28.488 ;
     RECT  107.173 29.04 107.449 29.064 ;
     RECT  105.617 1.728 107.461 2.52 ;
     RECT  107.461 1.728 107.557 3.096 ;
     RECT  106.307 21.648 107.557 26.856 ;
     RECT  106.669 27.936 107.557 27.96 ;
     RECT  107.449 29.04 107.651 29.112 ;
     RECT  107.557 1.728 107.708 3.336 ;
     RECT  107.557 21.648 107.708 27.96 ;
     RECT  107.461 0.144 107.747 0.168 ;
     RECT  107.708 1.728 107.812 28.824 ;
     RECT  107.812 1.728 108.004 27.822 ;
     RECT  107.749 29.904 108.131 30.072 ;
     RECT  108.131 29.904 108.275 30.024 ;
     RECT  108.275 29.904 108.323 29.928 ;
     RECT  108.004 1.728 108.469 3.144 ;
     RECT  107.812 28.8 108.613 28.824 ;
     RECT  108.004 18.912 108.677 18.936 ;
     RECT  108.613 28.8 108.755 29.064 ;
     RECT  108.004 21.264 108.901 27.822 ;
     RECT  108.901 21.264 108.995 28.584 ;
     RECT  108.995 21.264 109.001 27.384 ;
     RECT  108.853 0.576 109.073 0.6 ;
     RECT  108.995 28.512 109.361 28.584 ;
     RECT  108.469 1.728 109.681 2.952 ;
     RECT  109.813 29.04 109.955 29.064 ;
     RECT  109.909 13.056 110.005 13.08 ;
     RECT  110.005 29.952 110.101 30.024 ;
     RECT  109.001 21.648 110.197 27.384 ;
     RECT  109.681 1.728 110.408 3.096 ;
     RECT  110.005 13.056 110.408 13.656 ;
     RECT  110.197 21.648 110.408 27.624 ;
     RECT  110.408 1.728 110.704 28.536 ;
     RECT  110.704 12 110.801 14.232 ;
     RECT  110.801 12.288 110.873 14.232 ;
     RECT  110.101 29.952 111.059 30.072 ;
     RECT  110.704 28.512 111.125 28.536 ;
     RECT  110.704 21.744 111.457 27.48 ;
     RECT  110.704 1.728 111.841 2.952 ;
     RECT  111.841 1.728 111.925 3.192 ;
     RECT  111.059 30.048 112.021 30.072 ;
     RECT  112.021 29.952 112.069 30.072 ;
     RECT  112.069 28.944 112.259 30.072 ;
     RECT  111.781 27.936 112.501 27.96 ;
     RECT  111.457 21.744 112.561 26.856 ;
     RECT  112.561 21.648 112.597 26.856 ;
     RECT  112.501 27.936 112.597 28.536 ;
     RECT  112.259 29.616 112.637 30.072 ;
     RECT  112.597 21.648 112.673 28.536 ;
     RECT  110.873 12.528 112.885 14.232 ;
     RECT  111.925 1.728 112.933 2.952 ;
     RECT  112.637 29.664 112.979 30.072 ;
     RECT  112.933 1.728 113.108 3.048 ;
     RECT  112.885 12 113.108 14.232 ;
     RECT  112.673 21.648 113.108 28.248 ;
     RECT  112.979 29.904 113.123 30.072 ;
     RECT  113.108 1.728 113.404 28.248 ;
     RECT  113.404 21.12 113.573 27.384 ;
     RECT  113.123 29.904 113.699 30.024 ;
     RECT  113.699 30 113.795 30.024 ;
     RECT  113.573 21.12 114.005 26.856 ;
     RECT  114.085 28.512 114.329 28.536 ;
     RECT  114.005 21.648 114.419 26.856 ;
     RECT  114.661 30.048 114.803 30.072 ;
     RECT  114.805 29.952 114.947 29.976 ;
     RECT  113.404 1.728 114.949 2.952 ;
     RECT  114.949 0.144 115.091 0.168 ;
     RECT  114.419 21.744 115.549 26.856 ;
     RECT  114.949 1.728 115.621 3.096 ;
     RECT  115.549 21.504 115.693 26.856 ;
     RECT  115.621 1.728 115.808 3.336 ;
     RECT  113.404 12 115.808 14.232 ;
     RECT  115.693 21.12 115.808 26.856 ;
     RECT  115.813 29.76 115.957 29.784 ;
     RECT  116.053 0.336 116.101 0.36 ;
     RECT  115.957 29.76 116.101 29.928 ;
     RECT  115.808 1.728 116.104 28.092 ;
     RECT  116.104 21.12 116.149 28.092 ;
     RECT  116.101 29.76 116.233 29.976 ;
     RECT  116.104 1.728 116.237 3.24 ;
     RECT  116.101 0.24 116.243 0.36 ;
     RECT  116.233 29.76 116.243 30.12 ;
     RECT  116.104 13.104 116.245 13.656 ;
     RECT  116.243 29.856 116.273 30.12 ;
     RECT  116.104 11.664 116.291 11.976 ;
     RECT  116.149 21.12 116.291 28.2 ;
     RECT  116.291 11.952 116.309 11.976 ;
     RECT  116.291 21.408 116.339 28.2 ;
     RECT  116.245 13.632 116.417 13.656 ;
     RECT  116.273 29.904 116.435 30.12 ;
     RECT  116.339 21.408 116.483 27.48 ;
     RECT  116.435 30 116.579 30.12 ;
     RECT  116.593 28.512 116.705 28.536 ;
     RECT  116.579 30.048 116.705 30.12 ;
     RECT  116.237 2.064 117.145 3.24 ;
     RECT  117.145 2.064 117.421 3.096 ;
     RECT  116.705 30.048 117.539 30.072 ;
     RECT  117.637 13.392 117.733 13.416 ;
     RECT  117.701 12 117.809 12.024 ;
     RECT  117.733 13.392 117.809 13.656 ;
     RECT  117.541 29.952 117.827 29.976 ;
     RECT  116.483 21.408 117.917 27.384 ;
     RECT  117.829 0.144 117.971 0.168 ;
     RECT  117.917 21.12 118.069 27.384 ;
     RECT  117.421 1.728 118.508 3.096 ;
     RECT  117.809 12 118.508 13.656 ;
     RECT  118.069 21.12 118.508 28.248 ;
     RECT  118.508 1.728 118.804 28.248 ;
     RECT  118.804 21.12 118.931 27.192 ;
     RECT  118.837 28.512 118.981 28.536 ;
     RECT  118.693 30.048 119.075 30.072 ;
     RECT  118.981 28.512 119.123 29.064 ;
     RECT  118.931 21.12 119.233 27.144 ;
     RECT  119.123 28.512 119.315 28.536 ;
     RECT  119.233 21.12 119.341 26.856 ;
     RECT  118.804 1.728 119.737 2.952 ;
     RECT  118.804 12 119.833 12.6 ;
     RECT  119.833 12 119.893 12.648 ;
     RECT  118.804 13.632 119.893 14.04 ;
     RECT  119.893 12 120.035 14.04 ;
     RECT  119.341 21.12 120.445 26.712 ;
     RECT  120.565 30.048 120.709 30.072 ;
     RECT  119.737 1.728 120.777 2.904 ;
     RECT  120.777 1.728 121.045 2.952 ;
     RECT  120.709 29.952 121.045 30.072 ;
     RECT  120.035 12.048 121.093 14.04 ;
     RECT  121.045 1.728 121.208 3.048 ;
     RECT  121.093 12 121.208 14.04 ;
     RECT  120.445 21.12 121.208 27.672 ;
     RECT  121.045 0.144 121.283 0.168 ;
     RECT  121.045 29.904 121.331 30.072 ;
     RECT  121.208 1.728 121.429 28.092 ;
     RECT  121.429 1.728 121.504 28.536 ;
     RECT  121.504 21.408 121.619 28.536 ;
     RECT  121.504 12 121.933 13.608 ;
     RECT  121.619 21.408 122.249 27.48 ;
     RECT  122.249 21.408 122.435 27.384 ;
     RECT  121.331 30.048 122.531 30.072 ;
     RECT  121.933 12.192 122.645 13.608 ;
     RECT  121.619 28.512 122.771 28.536 ;
     RECT  122.645 12.576 122.893 13.608 ;
     RECT  122.893 12.576 122.897 14.184 ;
     RECT  121.504 1.728 123.109 2.904 ;
     RECT  123.109 1.152 123.193 2.904 ;
     RECT  122.435 21.408 123.469 26.856 ;
     RECT  123.193 1.728 123.733 2.904 ;
     RECT  123.733 0.24 123.781 0.264 ;
     RECT  123.733 1.728 123.793 3.048 ;
     RECT  123.793 1.728 123.908 3.336 ;
     RECT  122.897 12.576 123.908 12.792 ;
     RECT  122.897 14.16 123.908 14.184 ;
     RECT  123.469 21.408 123.908 27.768 ;
     RECT  123.685 29.04 123.908 29.064 ;
     RECT  123.781 0.144 124.019 0.264 ;
     RECT  124.019 0.24 124.163 0.264 ;
     RECT  123.908 1.728 124.204 29.064 ;
     RECT  124.204 21.408 124.355 26.808 ;
     RECT  124.355 21.504 124.409 26.808 ;
     RECT  124.204 28.176 124.451 29.064 ;
     RECT  123.493 30.048 124.547 30.072 ;
     RECT  124.451 28.512 124.625 29.064 ;
     RECT  124.625 29.04 124.805 29.064 ;
     RECT  124.409 21.504 124.877 26.76 ;
     RECT  124.204 1.728 124.885 3.192 ;
     RECT  124.877 21.648 125.561 26.76 ;
     RECT  125.561 23.04 125.605 26.76 ;
     RECT  125.665 29.664 125.795 29.688 ;
     RECT  124.204 14.16 125.881 14.184 ;
     RECT  125.605 23.04 126.037 27.672 ;
     RECT  125.881 13.968 126.205 14.184 ;
     RECT  126.205 13.344 126.277 14.184 ;
     RECT  124.885 1.728 126.457 2.904 ;
     RECT  126.457 1.728 126.608 3.144 ;
     RECT  126.277 12.432 126.608 14.184 ;
     RECT  125.561 21.648 126.608 21.816 ;
     RECT  126.037 23.04 126.608 28.488 ;
     RECT  126.608 1.728 126.901 28.488 ;
     RECT  126.901 1.728 126.904 28.824 ;
     RECT  126.904 21.12 127.001 28.824 ;
     RECT  126.181 30.048 127.043 30.072 ;
     RECT  127.001 26.928 127.081 28.488 ;
     RECT  127.001 21.12 127.181 25.8 ;
     RECT  127.181 23.856 127.721 25.8 ;
     RECT  126.904 1.728 128.005 2.952 ;
     RECT  127.765 30.096 128.045 30.12 ;
     RECT  127.081 27.456 128.053 28.488 ;
     RECT  128.053 27.36 128.197 28.488 ;
     RECT  128.197 27.312 128.485 28.488 ;
     RECT  127.181 21.12 128.581 22.776 ;
     RECT  127.721 23.856 128.581 25.08 ;
     RECT  128.005 1.728 128.869 3 ;
     RECT  128.917 29.952 129.061 29.976 ;
     RECT  129.061 29.952 129.107 30.12 ;
     RECT  129.107 30.096 129.203 30.12 ;
     RECT  128.485 26.88 129.269 28.488 ;
     RECT  128.869 1.728 129.308 3.144 ;
     RECT  126.904 12.576 129.308 12.6 ;
     RECT  128.257 13.968 129.308 13.992 ;
     RECT  128.581 21.12 129.308 25.08 ;
     RECT  129.269 26.88 129.308 28.392 ;
     RECT  129.109 0.144 129.347 0.168 ;
     RECT  129.308 1.728 129.604 28.392 ;
     RECT  129.604 21.744 129.701 22.296 ;
     RECT  129.701 21.744 129.809 21.96 ;
     RECT  129.604 26.544 129.953 28.392 ;
     RECT  129.604 23.28 130.097 25.128 ;
     RECT  130.097 23.28 130.133 24.408 ;
     RECT  129.604 12.576 130.169 12.6 ;
     RECT  130.133 23.856 130.169 24.408 ;
     RECT  129.604 1.728 130.205 3.144 ;
     RECT  130.169 24.384 130.241 24.408 ;
     RECT  129.953 27.36 130.529 28.392 ;
     RECT  129.809 21.744 130.637 21.816 ;
     RECT  130.529 27.6 130.817 28.392 ;
     RECT  130.817 27.6 130.925 27.912 ;
     RECT  130.205 1.728 131.245 2.52 ;
     RECT  131.245 1.728 131.677 2.76 ;
     RECT  131.677 1.728 132.008 2.808 ;
     RECT  130.637 21.744 132.008 21.768 ;
     RECT  130.925 27.6 132.008 27.624 ;
     RECT  132.008 1.728 132.112 28.092 ;
     RECT  132.112 1.728 132.304 27.822 ;
     RECT  132.304 1.728 132.473 3.336 ;
     RECT  132.473 1.728 133.729 2.856 ;
     RECT  133.729 1.728 134.708 3.192 ;
     RECT  132.304 21.744 134.708 21.768 ;
     RECT  134.708 1.728 134.812 28.092 ;
     RECT  134.812 1.728 135.004 27.822 ;
     RECT  135.004 1.728 135.203 3.192 ;
     RECT  135.203 1.728 136.181 3.096 ;
     RECT  136.181 1.728 137.408 2.904 ;
     RECT  135.004 21.744 137.408 21.768 ;
     RECT  137.408 1.728 137.512 28.092 ;
     RECT  137.512 1.728 137.704 27.822 ;
     RECT  137.704 1.728 137.945 3.384 ;
     RECT  137.945 1.728 138.949 2.904 ;
     RECT  138.949 1.728 138.953 2.952 ;
     RECT  138.953 1.824 139.477 2.952 ;
     RECT  139.477 1.824 139.561 3.096 ;
     RECT  139.561 1.824 139.849 3.144 ;
     RECT  139.849 1.824 140.108 3.336 ;
     RECT  137.704 21.744 140.108 21.768 ;
     RECT  140.108 1.824 140.197 28.092 ;
     RECT  140.197 1.728 140.212 28.092 ;
     RECT  140.212 1.728 140.404 27.822 ;
     RECT  140.404 1.728 141.757 3.096 ;
     RECT  141.757 1.728 142.645 3.192 ;
     RECT  142.645 1.728 142.808 3.336 ;
     RECT  140.404 21.744 142.808 21.768 ;
     RECT  142.693 0.144 142.835 0.168 ;
     RECT  142.808 1.728 142.912 28.092 ;
     RECT  142.912 1.728 143.104 27.822 ;
     RECT  143.104 1.728 144.085 2.616 ;
     RECT  144.085 1.728 144.173 2.904 ;
     RECT  144.173 1.728 144.773 2.616 ;
     RECT  144.773 1.152 144.857 2.616 ;
     RECT  144.857 1.728 145.508 2.616 ;
     RECT  145.508 1.728 145.612 28.092 ;
     RECT  145.612 1.728 145.804 27.822 ;
     RECT  145.804 1.728 147.397 2.904 ;
     RECT  147.397 1.728 147.541 2.952 ;
     RECT  147.541 1.728 147.644 3.144 ;
     RECT  147.644 1.68 147.731 3.144 ;
     RECT  147.731 1.728 148.208 3.144 ;
     RECT  148.208 1.728 148.312 28.092 ;
     RECT  148.312 1.728 148.504 27.822 ;
     RECT  148.504 1.728 149.171 3.192 ;
     RECT  149.171 1.728 149.897 3.096 ;
     RECT  149.897 1.728 150.908 2.856 ;
     RECT  150.908 1.728 151.012 28.092 ;
     RECT  151.012 1.728 151.141 27.822 ;
     RECT  151.141 1.152 151.204 27.822 ;
     RECT  151.204 1.152 151.337 3.144 ;
     RECT  151.337 1.728 152.201 3.144 ;
     RECT  152.201 1.728 153.608 2.904 ;
     RECT  153.608 1.728 153.712 28.092 ;
     RECT  153.712 1.728 153.904 27.822 ;
     RECT  153.904 1.728 154.937 3.144 ;
     RECT  154.937 1.728 156.181 3.096 ;
     RECT  156.181 1.728 156.308 3.336 ;
     RECT  156.308 1.728 156.412 28.092 ;
     RECT  156.412 1.728 156.604 27.822 ;
     RECT  156.604 1.728 156.737 3.336 ;
     RECT  156.469 0.144 156.755 0.168 ;
     RECT  156.737 1.728 157.889 3.048 ;
     RECT  157.889 1.728 159.008 2.904 ;
     RECT  159.008 1.728 159.061 28.092 ;
     RECT  159.061 1.536 159.112 28.092 ;
     RECT  159.112 1.536 159.304 27.822 ;
     RECT  159.304 1.536 159.437 2.952 ;
     RECT  159.437 1.728 161.077 2.952 ;
     RECT  161.077 1.728 161.708 3.144 ;
     RECT  161.708 1.728 161.812 28.092 ;
     RECT  161.557 0.144 161.843 0.168 ;
     RECT  161.812 1.728 162.004 27.822 ;
     RECT  161.941 0.192 162.131 0.312 ;
     RECT  162.131 0.192 162.227 0.216 ;
     RECT  162.004 1.728 163.073 3.096 ;
     RECT  163.073 1.728 164.408 3.048 ;
     RECT  164.408 1.728 164.512 28.092 ;
     RECT  164.512 1.728 164.704 27.822 ;
     RECT  164.704 1.728 166.373 2.952 ;
     RECT  166.373 1.728 167.108 3.144 ;
     RECT  167.108 1.728 167.212 28.092 ;
     RECT  167.212 1.728 167.404 27.822 ;
     RECT  167.413 0.144 167.555 0.168 ;
     RECT  167.404 1.728 168.577 3.192 ;
     RECT  168.577 1.728 169.297 3.912 ;
     RECT  169.297 1.728 169.373 4.68 ;
     RECT  169.373 1.776 169.441 4.68 ;
     RECT  169.261 0.576 169.513 0.6 ;
     RECT  169.441 1.776 169.808 4.968 ;
     RECT  169.808 1.776 169.912 28.092 ;
     RECT  169.513 0.48 170.005 0.6 ;
     RECT  169.912 1.776 170.104 27.822 ;
     RECT  170.104 1.776 170.201 2.856 ;
     RECT  170.005 0.144 170.243 0.6 ;
     RECT  170.104 3.888 170.309 5.256 ;
     RECT  170.201 2.256 170.339 2.856 ;
     RECT  170.243 0.528 170.413 0.6 ;
     RECT  170.309 4.56 170.417 5.256 ;
     RECT  170.417 4.56 170.489 4.68 ;
     RECT  170.413 0.528 170.524 1.176 ;
     RECT  170.489 4.56 170.771 4.584 ;
     RECT  170.524 0.528 171.491 1.128 ;
     RECT  171.491 0.528 171.557 0.984 ;
     RECT  170.339 2.832 171.637 2.856 ;
     RECT  171.557 0.096 171.641 0.984 ;
     RECT  171.637 2.784 171.779 2.856 ;
     RECT  171.641 0.96 171.923 0.984 ;
     RECT  171.779 2.784 172.067 2.808 ;
    LAYER M5 ;
     RECT  90.912 0.016 91.08 0.131 ;
     RECT  87.792 0.016 89.832 0.611 ;
     RECT  92.16 0.016 130.344 0.611 ;
     RECT  87.936 0.611 89.832 1.763 ;
     RECT  91.056 0.131 91.08 1.763 ;
     RECT  131.424 0.016 172.056 1.763 ;
     RECT  88.08 1.763 89.256 1.811 ;
     RECT  92.304 0.611 130.344 1.811 ;
     RECT  131.712 1.763 172.056 1.811 ;
     RECT  92.304 1.811 129.912 1.859 ;
     RECT  169.008 1.811 172.056 1.859 ;
     RECT  131.712 1.811 167.88 1.907 ;
     RECT  131.712 1.907 152.184 2.003 ;
     RECT  92.304 1.859 129.612 2.099 ;
     RECT  92.304 2.099 92.904 2.137 ;
     RECT  131.712 2.003 132.456 2.147 ;
     RECT  2.4 2.137 2.52 2.151 ;
     RECT  5.1 2.137 5.22 2.151 ;
     RECT  7.8 2.137 7.92 2.151 ;
     RECT  10.5 2.137 10.62 2.151 ;
     RECT  13.2 2.137 13.32 2.151 ;
     RECT  15.9 2.137 16.02 2.151 ;
     RECT  18.6 2.137 18.72 2.151 ;
     RECT  21.3 2.137 21.42 2.151 ;
     RECT  24 2.137 24.12 2.151 ;
     RECT  26.7 2.137 26.82 2.151 ;
     RECT  29.4 2.137 29.52 2.151 ;
     RECT  32.1 2.137 32.22 2.151 ;
     RECT  34.8 2.137 34.92 2.151 ;
     RECT  37.5 2.137 37.62 2.151 ;
     RECT  40.2 2.137 40.32 2.151 ;
     RECT  42.9 2.137 43.02 2.151 ;
     RECT  45.6 2.137 45.72 2.151 ;
     RECT  48.3 2.137 48.42 2.151 ;
     RECT  51 2.137 51.12 2.151 ;
     RECT  53.7 2.137 53.82 2.151 ;
     RECT  56.4 2.137 56.52 2.151 ;
     RECT  59.1 2.137 59.22 2.151 ;
     RECT  61.8 2.137 61.92 2.151 ;
     RECT  64.5 2.137 64.62 2.151 ;
     RECT  67.2 2.137 67.32 2.151 ;
     RECT  69.9 2.137 70.02 2.151 ;
     RECT  72.6 2.137 72.72 2.151 ;
     RECT  75.3 2.137 75.42 2.151 ;
     RECT  78 2.137 78.12 2.151 ;
     RECT  80.7 2.137 80.82 2.151 ;
     RECT  83.4 2.137 83.52 2.151 ;
     RECT  86.1 2.137 86.22 2.151 ;
     RECT  94.08 2.099 129.612 2.243 ;
     RECT  133.872 2.003 152.184 2.243 ;
     RECT  91.5 2.137 92.904 2.291 ;
     RECT  94.08 2.243 97.368 2.291 ;
     RECT  98.352 2.243 129.612 2.291 ;
     RECT  133.872 2.243 143.112 2.291 ;
     RECT  144.096 2.243 152.184 2.291 ;
     RECT  94.08 2.291 94.512 2.819 ;
     RECT  131.712 2.147 132.312 2.819 ;
     RECT  169.152 1.859 172.056 2.819 ;
     RECT  169.152 2.819 171.768 2.867 ;
     RECT  88.8 1.811 89.256 2.915 ;
     RECT  95.616 2.291 97.368 2.915 ;
     RECT  98.352 2.291 106.008 2.915 ;
     RECT  107.472 2.291 124.872 2.915 ;
     RECT  125.856 2.291 129.612 2.915 ;
     RECT  133.872 2.291 140.664 2.915 ;
     RECT  144.096 2.291 144.12 2.915 ;
     RECT  145.5 2.291 149.88 2.915 ;
     RECT  153.168 1.907 153.912 2.915 ;
     RECT  154.896 1.907 167.88 2.915 ;
     RECT  169.152 2.867 170.76 2.915 ;
     RECT  95.616 2.915 97.32 2.963 ;
     RECT  104.256 2.915 106.008 2.963 ;
     RECT  107.472 2.915 108.744 2.963 ;
     RECT  109.728 2.915 121.896 2.963 ;
     RECT  126.6 2.915 129.612 2.963 ;
     RECT  139.056 2.915 140.664 2.963 ;
     RECT  147.408 2.915 149.88 2.963 ;
     RECT  159 2.915 164.712 2.963 ;
     RECT  165.696 2.915 167.544 2.963 ;
     RECT  128.016 2.963 128.04 3.011 ;
     RECT  96.336 2.963 97.32 3.059 ;
     RECT  98.496 2.915 103.128 3.059 ;
     RECT  123.744 2.915 124.872 3.059 ;
     RECT  155.904 2.915 157.656 3.059 ;
     RECT  161.088 2.963 164.712 3.059 ;
     RECT  96.9 3.059 97.32 3.107 ;
     RECT  98.496 3.059 98.52 3.107 ;
     RECT  101.232 3.059 103.128 3.107 ;
     RECT  107.472 2.963 108.456 3.107 ;
     RECT  109.728 2.963 119.016 3.107 ;
     RECT  129.024 2.963 129.612 3.107 ;
     RECT  133.872 2.915 135.912 3.107 ;
     RECT  139.488 2.963 140.664 3.107 ;
     RECT  147.552 2.963 149.88 3.107 ;
     RECT  155.904 3.059 156.612 3.107 ;
     RECT  161.088 3.059 162.84 3.107 ;
     RECT  166.416 2.963 167.544 3.107 ;
     RECT  101.376 3.107 103.128 3.155 ;
     RECT  107.7 3.107 108.456 3.155 ;
     RECT  139.632 3.107 140.412 3.155 ;
     RECT  147.552 3.107 149.16 3.155 ;
     RECT  150.9 2.291 152.184 3.155 ;
     RECT  154.896 2.915 154.92 3.155 ;
     RECT  161.088 3.107 162.012 3.155 ;
     RECT  166.416 3.107 167.412 3.155 ;
     RECT  123.9 3.059 124.872 3.203 ;
     RECT  133.872 3.107 135.192 3.203 ;
     RECT  141.792 2.291 143.112 3.203 ;
     RECT  148.2 3.155 149.16 3.203 ;
     RECT  110.4 3.107 119.016 3.251 ;
     RECT  104.832 2.963 106.008 3.347 ;
     RECT  142.656 3.203 143.112 3.347 ;
     RECT  156.192 3.107 156.612 3.347 ;
     RECT  101.376 3.155 102.612 3.395 ;
     RECT  137.4 2.915 137.928 3.395 ;
     RECT  105 3.347 106.008 3.587 ;
     RECT  169.44 2.915 170.76 4.595 ;
     RECT  91.5 2.291 91.812 5.653 ;
     RECT  117.744 3.251 119.016 12.035 ;
     RECT  117.84 12.035 119.016 12.373 ;
     RECT  120 2.963 121.896 12.373 ;
     RECT  117.84 12.373 121.896 12.517 ;
     RECT  110.4 3.251 116.28 12.563 ;
     RECT  110.4 12.563 114.408 13.045 ;
     RECT  117.84 12.517 121.944 13.381 ;
     RECT  115.488 12.563 116.28 13.621 ;
     RECT  109.92 13.045 114.408 14.197 ;
     RECT  115.392 13.621 116.28 14.197 ;
     RECT  88.8 2.915 89.112 14.773 ;
     RECT  88.8 14.773 89.976 19.571 ;
     RECT  102.3 3.395 102.612 19.909 ;
     RECT  88.8 19.571 89.544 20.147 ;
     RECT  75.3 2.151 75.612 20.293 ;
     RECT  99.6 3.059 99.912 21.109 ;
     RECT  109.92 14.197 116.28 21.155 ;
     RECT  59.1 2.151 59.412 21.397 ;
     RECT  80.7 2.151 81.012 21.397 ;
     RECT  123.9 3.203 124.212 21.397 ;
     RECT  117.648 13.381 121.944 21.491 ;
     RECT  99.6 21.109 100.008 21.493 ;
     RECT  102.192 19.909 102.612 21.539 ;
     RECT  102.3 21.539 102.612 21.589 ;
     RECT  61.8 2.151 62.112 21.637 ;
     RECT  72.6 2.151 72.912 21.637 ;
     RECT  105 3.587 105.312 21.637 ;
     RECT  107.7 3.155 108.012 21.637 ;
     RECT  123.9 21.397 124.344 21.637 ;
     RECT  58.272 21.397 59.412 21.683 ;
     RECT  117.648 21.491 121.512 21.683 ;
     RECT  106.8 21.637 108.012 21.733 ;
     RECT  123.9 21.637 124.728 21.781 ;
     RECT  126.6 2.963 126.912 21.781 ;
     RECT  67.2 2.151 67.512 21.925 ;
     RECT  69.9 2.151 70.212 21.925 ;
     RECT  75.3 20.293 75.816 21.925 ;
     RECT  96.9 3.107 97.212 21.925 ;
     RECT  106.8 21.733 108.6 22.019 ;
     RECT  53.7 2.151 54.012 22.021 ;
     RECT  69.9 21.925 70.68 22.067 ;
     RECT  123.9 21.781 126.912 22.213 ;
     RECT  84.912 21.637 84.936 22.259 ;
     RECT  86.1 2.151 86.412 22.261 ;
     RECT  94.2 2.819 94.512 22.453 ;
     RECT  104.592 21.637 105.312 22.499 ;
     RECT  99.6 21.493 100.296 22.597 ;
     RECT  53.568 22.021 54.012 22.645 ;
     RECT  67.2 21.925 67.608 22.693 ;
     RECT  109.92 21.155 116.232 22.693 ;
     RECT  121.2 21.683 121.512 22.693 ;
     RECT  75.3 21.925 76.632 22.741 ;
     RECT  78 2.151 78.312 22.741 ;
     RECT  83.4 2.151 83.712 22.741 ;
     RECT  94.2 22.453 95.016 22.741 ;
     RECT  96.9 21.925 97.608 22.741 ;
     RECT  109.536 22.693 116.232 22.741 ;
     RECT  123.072 22.213 126.912 22.787 ;
     RECT  91.392 5.653 91.812 22.789 ;
     RECT  109.536 22.741 116.28 22.835 ;
     RECT  117.648 21.683 119.928 22.835 ;
     RECT  94.2 22.741 95.736 22.883 ;
     RECT  90.624 22.789 91.812 22.931 ;
     RECT  56.4 2.151 56.712 22.981 ;
     RECT  68.832 22.453 68.856 22.981 ;
     RECT  69.9 22.067 70.44 22.981 ;
     RECT  105 22.499 105.312 22.981 ;
     RECT  106.8 22.019 108.168 22.981 ;
     RECT  80.592 21.397 81.012 23.221 ;
     RECT  123.9 22.787 126.912 23.267 ;
     RECT  75.3 22.741 78.312 23.269 ;
     RECT  55.488 22.981 56.712 23.317 ;
     RECT  105 22.981 108.168 23.317 ;
     RECT  109.536 22.835 113.64 23.317 ;
     RECT  55.488 23.317 56.808 23.365 ;
     RECT  61.8 21.637 62.664 23.365 ;
     RECT  75.072 23.269 78.312 23.365 ;
     RECT  79.776 23.221 81.012 23.365 ;
     RECT  83.4 22.741 83.928 23.365 ;
     RECT  99.6 22.597 101.112 23.365 ;
     RECT  105 23.317 113.64 23.411 ;
     RECT  99.6 23.365 101.256 23.413 ;
     RECT  117.648 22.835 119.592 23.459 ;
     RECT  102.3 21.589 103.032 23.461 ;
     RECT  46.944 23.029 46.968 23.555 ;
     RECT  68.832 22.981 70.44 23.701 ;
     RECT  71.76 21.637 72.912 23.701 ;
     RECT  118.5 23.459 119.592 23.845 ;
     RECT  53.568 22.645 54.216 23.893 ;
     RECT  59.1 21.683 59.412 23.893 ;
     RECT  68.832 23.701 72.912 23.893 ;
     RECT  75.072 23.365 81.012 23.893 ;
     RECT  82.608 23.365 83.928 23.941 ;
     RECT  86.1 22.261 86.52 23.941 ;
     RECT  87.696 22.741 87.72 23.941 ;
     RECT  105 23.411 111.624 23.941 ;
     RECT  114.768 22.835 116.28 23.941 ;
     RECT  91.392 22.931 91.812 23.987 ;
     RECT  112.896 23.411 113.64 23.987 ;
     RECT  68.832 23.893 81.012 24.083 ;
     RECT  64.5 2.151 64.812 24.085 ;
     RECT  65.808 23.845 65.832 24.085 ;
     RECT  94.2 22.883 95.016 24.229 ;
     RECT  123.9 23.267 124.728 24.323 ;
     RECT  121.104 22.693 121.512 24.325 ;
     RECT  67.2 22.693 67.656 24.373 ;
     RECT  82.512 23.941 83.928 24.373 ;
     RECT  96.9 22.741 97.656 24.421 ;
     RECT  53.04 23.893 54.216 24.469 ;
     RECT  55.488 23.365 58.056 24.469 ;
     RECT  64.5 24.085 65.832 24.469 ;
     RECT  67.2 24.373 67.752 24.469 ;
     RECT  94.08 24.229 95.016 24.469 ;
     RECT  96.24 24.421 97.656 24.469 ;
     RECT  112.944 23.987 113.64 24.469 ;
     RECT  114.768 23.941 117.048 24.469 ;
     RECT  118.5 23.845 119.64 24.469 ;
     RECT  120.72 24.325 121.512 24.469 ;
     RECT  52.464 24.469 58.056 24.515 ;
     RECT  59.1 23.893 60.312 24.517 ;
     RECT  61.44 23.365 62.664 24.517 ;
     RECT  82.176 24.373 83.928 24.517 ;
     RECT  94.08 24.469 97.656 24.517 ;
     RECT  98.88 23.413 101.256 24.517 ;
     RECT  104.88 23.941 111.624 24.517 ;
     RECT  112.944 24.469 117.048 24.517 ;
     RECT  118.128 24.469 121.512 24.517 ;
     RECT  123.9 24.323 124.392 24.517 ;
     RECT  112.944 24.517 121.512 24.613 ;
     RECT  112.944 24.613 121.752 24.805 ;
     RECT  102.3 23.461 103.608 24.853 ;
     RECT  104.688 24.517 111.624 24.853 ;
     RECT  86.1 23.941 87.72 24.901 ;
     RECT  64.5 24.469 67.752 24.949 ;
     RECT  68.832 24.083 76.632 24.949 ;
     RECT  102.3 24.853 111.624 24.997 ;
     RECT  112.944 24.805 122.616 24.997 ;
     RECT  82.176 24.517 84.84 25.045 ;
     RECT  53.472 24.515 58.056 25.093 ;
     RECT  59.1 24.517 62.664 25.093 ;
     RECT  94.08 24.517 101.256 25.093 ;
     RECT  102.3 24.997 111.672 25.093 ;
     RECT  112.848 24.997 122.616 25.093 ;
     RECT  123.6 24.517 124.392 25.093 ;
     RECT  64.5 24.949 76.632 25.285 ;
     RECT  53.472 25.093 62.664 25.333 ;
     RECT  64.032 25.285 76.632 25.333 ;
     RECT  86.1 24.901 87.816 25.429 ;
     RECT  94.08 25.093 124.392 25.621 ;
     RECT  51 2.151 51.312 25.669 ;
     RECT  52.464 24.515 52.488 25.669 ;
     RECT  53.472 25.333 76.632 25.669 ;
     RECT  77.712 24.083 81.012 25.669 ;
     RECT  82.032 25.045 84.84 25.669 ;
     RECT  85.92 25.429 87.816 25.669 ;
     RECT  91.5 23.987 91.812 25.669 ;
     RECT  94.08 25.621 124.872 25.669 ;
     RECT  91.5 25.669 92.232 25.717 ;
     RECT  94.08 25.669 125.064 25.717 ;
     RECT  126.6 23.267 126.912 25.717 ;
     RECT  88.8 20.147 89.112 25.765 ;
     RECT  94.08 25.717 125.496 25.765 ;
     RECT  126.6 25.717 127.032 25.765 ;
     RECT  77.712 25.669 87.816 25.861 ;
     RECT  88.8 25.765 89.544 25.861 ;
     RECT  51 25.669 76.632 25.957 ;
     RECT  77.712 25.861 89.544 25.957 ;
     RECT  51 25.957 89.544 26.101 ;
     RECT  94.08 25.765 127.032 26.101 ;
     RECT  50.88 26.101 89.544 26.197 ;
     RECT  91.2 25.717 92.232 26.197 ;
     RECT  93.792 26.101 127.032 26.197 ;
     RECT  129.3 3.107 129.612 26.869 ;
     RECT  50.784 26.197 89.688 27.253 ;
     RECT  128.496 26.869 129.612 27.301 ;
     RECT  48.3 2.151 48.612 27.349 ;
     RECT  128.208 27.301 129.612 27.349 ;
     RECT  91.2 26.197 127.032 27.445 ;
     RECT  128.064 27.349 129.612 27.445 ;
     RECT  42.9 2.151 43.212 27.925 ;
     RECT  45.6 2.151 45.912 27.925 ;
     RECT  47.088 27.349 48.612 27.925 ;
     RECT  49.776 26.725 49.8 27.925 ;
     RECT  50.784 27.253 89.832 27.925 ;
     RECT  91.2 27.445 129.612 27.925 ;
     RECT  2.4 2.151 2.712 28.089 ;
     RECT  5.1 2.151 5.412 28.089 ;
     RECT  7.8 2.151 8.112 28.089 ;
     RECT  10.5 2.151 10.812 28.089 ;
     RECT  13.2 2.151 13.512 28.089 ;
     RECT  15.9 2.151 16.212 28.089 ;
     RECT  18.6 2.151 18.912 28.089 ;
     RECT  21.3 2.151 21.612 28.089 ;
     RECT  24 2.151 24.312 28.089 ;
     RECT  26.7 2.151 27.012 28.089 ;
     RECT  29.4 2.151 29.712 28.089 ;
     RECT  32.1 2.151 32.412 28.089 ;
     RECT  34.8 2.151 35.112 28.089 ;
     RECT  37.5 2.151 37.812 28.089 ;
     RECT  40.2 2.151 40.512 28.089 ;
     RECT  47.088 27.925 89.832 28.089 ;
     RECT  90.912 27.925 129.612 28.089 ;
     RECT  132 2.819 132.312 28.089 ;
     RECT  134.7 3.203 135.012 28.089 ;
     RECT  137.4 3.395 137.712 28.089 ;
     RECT  140.1 3.155 140.412 28.089 ;
     RECT  142.8 3.347 143.112 28.089 ;
     RECT  145.5 2.915 145.812 28.089 ;
     RECT  148.2 3.203 148.512 28.089 ;
     RECT  150.9 3.155 151.212 28.089 ;
     RECT  153.6 2.915 153.912 28.089 ;
     RECT  156.3 3.347 156.612 28.089 ;
     RECT  159 2.963 159.312 28.089 ;
     RECT  161.7 3.155 162.012 28.089 ;
     RECT  164.4 3.059 164.712 28.089 ;
     RECT  167.1 3.155 167.412 28.089 ;
     RECT  169.8 4.595 170.112 28.089 ;
     RECT  2.4 28.089 2.52 28.103 ;
     RECT  5.1 28.089 5.22 28.103 ;
     RECT  7.8 28.089 7.92 28.103 ;
     RECT  10.5 28.089 10.62 28.103 ;
     RECT  13.2 28.089 13.32 28.103 ;
     RECT  15.9 28.089 16.02 28.103 ;
     RECT  18.6 28.089 18.72 28.103 ;
     RECT  21.3 28.089 21.42 28.103 ;
     RECT  24 28.089 24.12 28.103 ;
     RECT  26.7 28.089 26.82 28.103 ;
     RECT  29.4 28.089 29.52 28.103 ;
     RECT  32.1 28.089 32.22 28.103 ;
     RECT  34.8 28.089 34.92 28.103 ;
     RECT  37.5 28.089 37.62 28.103 ;
     RECT  40.2 28.089 40.32 28.103 ;
     RECT  42.9 27.925 43.608 28.103 ;
     RECT  44.976 27.925 45.912 28.103 ;
     RECT  47.088 28.089 48.42 28.103 ;
     RECT  90.912 28.089 129.42 28.103 ;
     RECT  132 28.089 132.12 28.103 ;
     RECT  134.7 28.089 134.82 28.103 ;
     RECT  137.4 28.089 137.52 28.103 ;
     RECT  140.1 28.089 140.22 28.103 ;
     RECT  142.8 28.089 142.92 28.103 ;
     RECT  145.5 28.089 145.62 28.103 ;
     RECT  148.2 28.089 148.32 28.103 ;
     RECT  150.9 28.089 151.02 28.103 ;
     RECT  153.6 28.089 153.72 28.103 ;
     RECT  156.3 28.089 156.42 28.103 ;
     RECT  159 28.089 159.12 28.103 ;
     RECT  161.7 28.089 161.82 28.103 ;
     RECT  164.4 28.089 164.52 28.103 ;
     RECT  167.1 28.089 167.22 28.103 ;
     RECT  169.8 28.089 169.92 28.103 ;
     RECT  43.584 28.103 43.608 28.453 ;
     RECT  44.976 28.103 45 28.453 ;
     RECT  47.088 28.103 48.12 29.029 ;
     RECT  49.488 28.089 89.832 29.077 ;
     RECT  90.912 28.103 129.192 30.131 ;
     RECT  43.584 28.453 43.752 30.224 ;
     RECT  44.832 28.453 45 30.224 ;
     RECT  46.08 29.029 48.12 30.224 ;
     RECT  49.2 29.077 89.832 30.224 ;
     RECT  90.912 30.131 129.096 30.224 ;
     RECT  89.88 0.016 90.864 0.132 ;
     RECT  91.128 0.016 92.112 0.132 ;
     RECT  130.392 0.016 131.376 0.132 ;
     RECT  90.984 0.131 91.008 0.132 ;
     RECT  89.832 0.132 91.056 1.763 ;
     RECT  91.08 0.132 92.16 0.611 ;
     RECT  130.344 0.132 131.424 1.763 ;
     RECT  91.08 0.611 92.304 1.763 ;
     RECT  91.5 1.763 92.304 2.137 ;
     RECT  130.344 1.763 131.712 1.811 ;
     RECT  167.88 1.811 169.008 1.859 ;
     RECT  167.88 1.859 169.152 2.915 ;
     RECT  152.184 1.907 153.168 2.915 ;
     RECT  153.912 1.907 154.896 3.155 ;
     RECT  132.456 2.003 133.872 2.147 ;
     RECT  92.904 2.099 94.08 2.291 ;
     RECT  97.368 2.243 98.352 2.915 ;
     RECT  143.112 2.243 144.096 2.915 ;
     RECT  94.512 2.291 95.616 2.963 ;
     RECT  106.008 2.291 107.472 3.107 ;
     RECT  124.872 2.291 125.856 2.915 ;
     RECT  140.664 2.291 141.792 3.107 ;
     RECT  144.12 2.291 145.5 2.915 ;
     RECT  149.88 2.291 150.9 3.107 ;
     RECT  97.32 2.915 98.496 3.107 ;
     RECT  103.128 2.915 104.256 2.963 ;
     RECT  108.744 2.915 109.728 2.963 ;
     RECT  135.912 2.915 137.4 3.107 ;
     RECT  137.928 2.915 139.056 2.963 ;
     RECT  152.184 2.915 153.6 3.155 ;
     RECT  154.92 2.915 155.904 3.107 ;
     RECT  157.656 2.915 159 3.059 ;
     RECT  164.712 2.915 165.696 2.963 ;
     RECT  108.456 2.963 109.728 3.107 ;
     RECT  119.016 2.963 120 12.373 ;
     RECT  126.912 2.963 128.016 3.011 ;
     RECT  128.04 2.963 129.024 3.011 ;
     RECT  98.52 3.059 99.6 3.107 ;
     RECT  99.912 3.059 101.232 3.107 ;
     RECT  99.912 3.107 101.376 3.395 ;
     RECT  140.412 3.107 141.792 3.203 ;
     RECT  154.92 3.107 156.192 3.155 ;
     RECT  116.28 3.251 117.744 12.035 ;
     RECT  116.28 12.035 117.84 13.381 ;
     RECT  114.408 12.563 115.488 13.621 ;
     RECT  116.28 13.381 117.648 21.155 ;
     RECT  114.408 13.621 115.392 14.197 ;
     RECT  89.976 14.773 91.392 19.571 ;
     RECT  116.232 21.155 117.648 22.741 ;
     RECT  102.192 21.539 102.3 22.597 ;
     RECT  83.712 21.637 84.912 22.259 ;
     RECT  84.936 21.637 86.1 22.259 ;
     RECT  105.312 21.637 106.8 22.981 ;
     RECT  119.928 21.683 121.2 22.693 ;
     RECT  108.6 21.733 109.92 22.019 ;
     RECT  70.68 21.925 71.76 22.067 ;
     RECT  76.632 21.925 78 22.741 ;
     RECT  108.168 22.019 109.92 22.693 ;
     RECT  70.44 22.067 71.76 23.701 ;
     RECT  83.712 22.259 83.928 22.741 ;
     RECT  67.608 22.453 68.832 22.693 ;
     RECT  68.856 22.453 69.9 22.981 ;
     RECT  104.592 22.499 105 23.461 ;
     RECT  101.112 22.597 102.3 23.365 ;
     RECT  67.656 22.693 68.832 24.373 ;
     RECT  108.168 22.693 109.536 23.317 ;
     RECT  119.928 22.693 121.104 22.835 ;
     RECT  86.52 22.741 87.696 23.941 ;
     RECT  87.72 22.741 88.8 24.901 ;
     RECT  95.736 22.741 96.9 22.883 ;
     RECT  116.28 22.741 117.648 23.459 ;
     RECT  89.112 22.789 90.624 22.931 ;
     RECT  113.64 22.835 114.768 24.469 ;
     RECT  119.592 22.835 121.104 23.845 ;
     RECT  54.216 22.981 55.488 24.469 ;
     RECT  45.912 23.029 46.944 23.555 ;
     RECT  46.968 23.029 48.3 23.555 ;
     RECT  78.312 23.221 79.776 23.365 ;
     RECT  58.056 23.365 59.1 25.093 ;
     RECT  101.256 23.365 102.3 25.093 ;
     RECT  111.624 23.411 112.896 23.987 ;
     RECT  97.656 23.413 98.88 24.517 ;
     RECT  116.28 23.459 118.5 23.941 ;
     RECT  103.608 23.461 105 23.941 ;
     RECT  64.812 23.845 65.808 24.085 ;
     RECT  65.832 23.845 67.2 24.469 ;
     RECT  119.64 23.845 121.104 24.325 ;
     RECT  60.312 23.893 61.44 24.517 ;
     RECT  81.012 23.941 82.512 24.373 ;
     RECT  103.608 23.941 104.88 24.517 ;
     RECT  117.048 23.941 118.5 24.469 ;
     RECT  111.624 23.987 112.944 24.997 ;
     RECT  76.632 24.083 77.712 25.957 ;
     RECT  124.392 24.323 124.728 25.621 ;
     RECT  119.64 24.325 120.72 24.469 ;
     RECT  67.752 24.373 68.832 24.949 ;
     RECT  81.012 24.373 82.176 25.045 ;
     RECT  95.016 24.421 96.24 24.469 ;
     RECT  51.312 24.469 52.464 25.669 ;
     RECT  117.048 24.469 118.128 24.517 ;
     RECT  52.488 24.515 53.472 25.669 ;
     RECT  84.84 24.517 86.1 25.429 ;
     RECT  103.608 24.517 104.688 24.853 ;
     RECT  122.616 24.805 123.6 25.093 ;
     RECT  87.816 24.901 88.8 25.861 ;
     RECT  111.672 24.997 112.848 25.093 ;
     RECT  81.012 25.045 82.032 25.669 ;
     RECT  62.664 25.285 64.032 25.333 ;
     RECT  84.84 25.429 85.92 25.669 ;
     RECT  125.496 25.717 126.6 25.765 ;
     RECT  89.688 26.197 91.2 27.253 ;
     RECT  48.612 26.725 49.776 27.925 ;
     RECT  49.8 26.725 50.784 27.925 ;
     RECT  127.032 26.869 128.496 27.301 ;
     RECT  89.832 27.253 91.2 27.925 ;
     RECT  127.032 27.301 128.208 27.349 ;
     RECT  45.912 27.349 47.088 28.103 ;
     RECT  127.032 27.349 128.064 27.445 ;
     RECT  43.608 27.925 44.976 28.453 ;
     RECT  89.832 27.925 90.912 30.108 ;
     RECT  48.42 28.089 49.488 28.103 ;
     RECT  45 28.103 47.088 29.029 ;
     RECT  48.12 28.103 49.488 29.077 ;
     RECT  43.752 28.453 44.832 30.108 ;
     RECT  45 29.029 46.08 30.108 ;
     RECT  48.12 29.077 49.2 30.108 ;
     RECT  43.8 30.108 44.784 30.224 ;
     RECT  45.048 30.108 46.032 30.224 ;
     RECT  48.168 30.108 49.152 30.224 ;
     RECT  89.88 30.108 90.864 30.224 ;
  END
END dsfd_sstn_e0c0_cp1
END LIBRARY
